###############################################################
#  Generated by:      Cadence Innovus 20.13-s083_1
#  OS:                Linux x86_64(Host ID caddyxtra)
#  Generated on:      Thu Jul  8 16:11:33 2021
#  Design:            user_proj_example
#  Command:           write_lef_abstract -specifyTopLayer 6 -PGPinLayers {5 6} -noCutObs -stripePin results/user_proj_example.lef
###############################################################

VERSION 5.8 ;

BUSBITCHARS "[]" ;
DIVIDERCHAR "/" ;

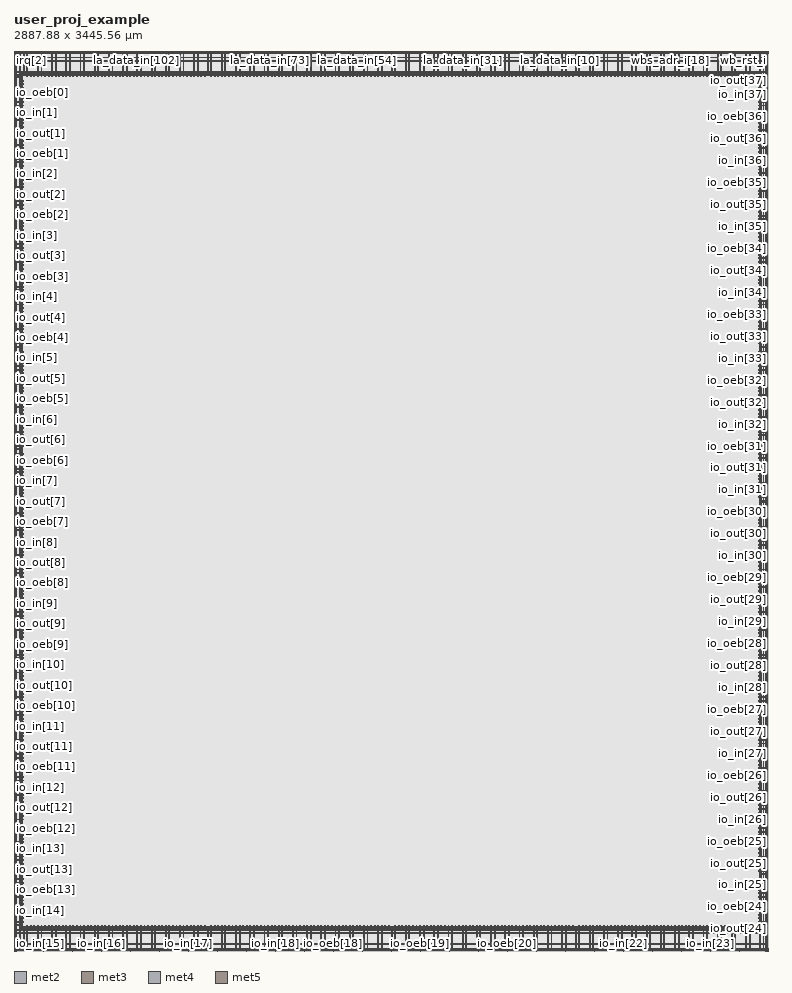
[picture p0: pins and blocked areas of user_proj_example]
MACRO user_proj_example
  CLASS BLOCK ;
  SIZE 2887.880000 BY 3445.560000 ;
  FOREIGN user_proj_example 0.000000 0.000000 ;
  ORIGIN 0 0 ;
  SYMMETRY X Y R90 ;
  PIN wb_clk_i
    DIRECTION INPUT ;
    USE SIGNAL ;
    ANTENNAPARTIALMETALAREA 0.238 LAYER met2  ;
    ANTENNAPARTIALMETALSIDEAREA 1.029 LAYER met2  ;
    ANTENNAPARTIALCUTAREA 0.04 LAYER via2  ;
    ANTENNAPARTIALMETALAREA 4.3968 LAYER met3  ;
    ANTENNAPARTIALMETALSIDEAREA 23.92 LAYER met3  ;
    ANTENNAMODEL OXIDE1 ;
    ANTENNAGATEAREA 1.152 LAYER met3  ;
    ANTENNAMAXAREACAR 6.23974 LAYER met3  ;
    ANTENNAMAXSIDEAREACAR 30.9826 LAYER met3  ;
    ANTENNAMAXCUTCAR 0.0793403 LAYER via3  ;
    PORT
      LAYER met2 ;
        RECT 2887.120000 3445.075000 2887.260000 3445.560000 ;
    END
  END wb_clk_i
  PIN wb_rst_i
    DIRECTION INPUT ;
    USE SIGNAL ;
    ANTENNAPARTIALMETALAREA 6.1835 LAYER met2  ;
    ANTENNAPARTIALMETALSIDEAREA 30.6915 LAYER met2  ;
    ANTENNAMODEL OXIDE1 ;
    ANTENNAGATEAREA 0.2475 LAYER met2  ;
    ANTENNAMAXAREACAR 26.3535 LAYER met2  ;
    ANTENNAMAXSIDEAREACAR 127.879 LAYER met2  ;
    ANTENNAMAXCUTCAR 0.207677 LAYER via2  ;
    PORT
      LAYER met2 ;
        RECT 2881.600000 3445.075000 2881.740000 3445.560000 ;
    END
  END wb_rst_i
  PIN wbs_stb_i
    DIRECTION INPUT ;
    USE SIGNAL ;
    ANTENNAPARTIALMETALAREA 2.4471 LAYER met2  ;
    ANTENNAPARTIALMETALSIDEAREA 12.1275 LAYER met2  ;
    ANTENNAMODEL OXIDE1 ;
    ANTENNAGATEAREA 0.2475 LAYER met2  ;
    ANTENNAMAXAREACAR 10.919 LAYER met2  ;
    ANTENNAMAXSIDEAREACAR 52.6263 LAYER met2  ;
    ANTENNAMAXCUTCAR 0.207677 LAYER via2  ;
    PORT
      LAYER met2 ;
        RECT 2863.660000 3445.075000 2863.800000 3445.560000 ;
    END
  END wbs_stb_i
  PIN wbs_cyc_i
    DIRECTION INPUT ;
    USE SIGNAL ;
    ANTENNAPARTIALMETALAREA 2.5759 LAYER met2  ;
    ANTENNAPARTIALMETALSIDEAREA 12.7715 LAYER met2  ;
    ANTENNAMODEL OXIDE1 ;
    ANTENNAGATEAREA 0.2475 LAYER met2  ;
    ANTENNAMAXAREACAR 13.2879 LAYER met2  ;
    ANTENNAMAXSIDEAREACAR 64.3515 LAYER met2  ;
    ANTENNAMAXCUTCAR 0.207677 LAYER via2  ;
    PORT
      LAYER met2 ;
        RECT 2869.640000 3445.075000 2869.780000 3445.560000 ;
    END
  END wbs_cyc_i
  PIN wbs_we_i
    DIRECTION INPUT ;
    USE SIGNAL ;
    ANTENNAPARTIALMETALAREA 2.5393 LAYER met2  ;
    ANTENNAPARTIALMETALSIDEAREA 12.3095 LAYER met2  ;
    ANTENNAMODEL OXIDE1 ;
    ANTENNAGATEAREA 0.126 LAYER met2  ;
    ANTENNAMAXAREACAR 22.6571 LAYER met2  ;
    ANTENNAMAXSIDEAREACAR 103.889 LAYER met2  ;
    ANTENNAPARTIALCUTAREA 0.04 LAYER via2  ;
    ANTENNAMAXCUTCAR 0.725397 LAYER via2  ;
    ANTENNAPARTIALMETALAREA 1.6368 LAYER met3  ;
    ANTENNAPARTIALMETALSIDEAREA 9.2 LAYER met3  ;
    ANTENNAGATEAREA 0.252 LAYER met3  ;
    ANTENNAMAXAREACAR 29.1524 LAYER met3  ;
    ANTENNAMAXSIDEAREACAR 140.397 LAYER met3  ;
    ANTENNAMAXCUTCAR 0.725397 LAYER via3  ;
    PORT
      LAYER met2 ;
        RECT 2858.140000 3445.075000 2858.280000 3445.560000 ;
    END
  END wbs_we_i
  PIN wbs_sel_i[3]
    DIRECTION INPUT ;
    USE SIGNAL ;
    PORT
      LAYER met2 ;
        RECT 2764.300000 3445.075000 2764.440000 3445.560000 ;
    END
  END wbs_sel_i[3]
  PIN wbs_sel_i[2]
    DIRECTION INPUT ;
    USE SIGNAL ;
    PORT
      LAYER met2 ;
        RECT 2787.760000 3445.075000 2787.900000 3445.560000 ;
    END
  END wbs_sel_i[2]
  PIN wbs_sel_i[1]
    DIRECTION INPUT ;
    USE SIGNAL ;
    PORT
      LAYER met2 ;
        RECT 2811.220000 3445.075000 2811.360000 3445.560000 ;
    END
  END wbs_sel_i[1]
  PIN wbs_sel_i[0]
    DIRECTION INPUT ;
    USE SIGNAL ;
    PORT
      LAYER met2 ;
        RECT 2834.680000 3445.075000 2834.820000 3445.560000 ;
    END
  END wbs_sel_i[0]
  PIN wbs_dat_i[31]
    DIRECTION INPUT ;
    USE SIGNAL ;
    ANTENNAPARTIALMETALAREA 2.3827 LAYER met2  ;
    ANTENNAPARTIALMETALSIDEAREA 11.8055 LAYER met2  ;
    ANTENNAMODEL OXIDE1 ;
    ANTENNAGATEAREA 0.126 LAYER met2  ;
    ANTENNAMAXAREACAR 31.0548 LAYER met2  ;
    ANTENNAMAXSIDEAREACAR 149.754 LAYER met2  ;
    ANTENNAMAXCUTCAR 0.407937 LAYER via2  ;
    PORT
      LAYER met2 ;
        RECT 2277.160000 3445.075000 2277.300000 3445.560000 ;
    END
  END wbs_dat_i[31]
  PIN wbs_dat_i[30]
    DIRECTION INPUT ;
    USE SIGNAL ;
    ANTENNAPARTIALMETALAREA 2.4919 LAYER met2  ;
    ANTENNAPARTIALMETALSIDEAREA 12.3515 LAYER met2  ;
    ANTENNAMODEL OXIDE1 ;
    ANTENNAGATEAREA 0.126 LAYER met2  ;
    ANTENNAMAXAREACAR 28.5845 LAYER met2  ;
    ANTENNAMAXSIDEAREACAR 133.508 LAYER met2  ;
    ANTENNAMAXCUTCAR 0.407937 LAYER via2  ;
    PORT
      LAYER met2 ;
        RECT 2294.640000 3445.075000 2294.780000 3445.560000 ;
    END
  END wbs_dat_i[30]
  PIN wbs_dat_i[29]
    DIRECTION INPUT ;
    USE SIGNAL ;
    ANTENNAPARTIALMETALAREA 3.4663 LAYER met2  ;
    ANTENNAPARTIALMETALSIDEAREA 17.2235 LAYER met2  ;
    ANTENNAMODEL OXIDE1 ;
    ANTENNAGATEAREA 0.126 LAYER met2  ;
    ANTENNAMAXAREACAR 53.9436 LAYER met2  ;
    ANTENNAMAXSIDEAREACAR 264.198 LAYER met2  ;
    ANTENNAMAXCUTCAR 0.407937 LAYER via2  ;
    PORT
      LAYER met2 ;
        RECT 2312.120000 3445.075000 2312.260000 3445.560000 ;
    END
  END wbs_dat_i[29]
  PIN wbs_dat_i[28]
    DIRECTION INPUT ;
    USE SIGNAL ;
    ANTENNAPARTIALMETALAREA 2.1111 LAYER met2  ;
    ANTENNAPARTIALMETALSIDEAREA 10.4475 LAYER met2  ;
    ANTENNAMODEL OXIDE1 ;
    ANTENNAGATEAREA 0.126 LAYER met2  ;
    ANTENNAMAXAREACAR 23.1687 LAYER met2  ;
    ANTENNAMAXSIDEAREACAR 102.921 LAYER met2  ;
    ANTENNAMAXCUTCAR 0.407937 LAYER via2  ;
    PORT
      LAYER met2 ;
        RECT 2329.600000 3445.075000 2329.740000 3445.560000 ;
    END
  END wbs_dat_i[28]
  PIN wbs_dat_i[27]
    DIRECTION INPUT ;
    USE SIGNAL ;
    ANTENNAPARTIALMETALAREA 2.2539 LAYER met2  ;
    ANTENNAPARTIALMETALSIDEAREA 11.1615 LAYER met2  ;
    ANTENNAMODEL OXIDE1 ;
    ANTENNAGATEAREA 0.126 LAYER met2  ;
    ANTENNAMAXAREACAR 19.9254 LAYER met2  ;
    ANTENNAMAXSIDEAREACAR 94.6429 LAYER met2  ;
    ANTENNAMAXCUTCAR 0.407937 LAYER via2  ;
    PORT
      LAYER met2 ;
        RECT 2347.540000 3445.075000 2347.680000 3445.560000 ;
    END
  END wbs_dat_i[27]
  PIN wbs_dat_i[26]
    DIRECTION INPUT ;
    USE SIGNAL ;
    ANTENNAPARTIALMETALAREA 2.2539 LAYER met2  ;
    ANTENNAPARTIALMETALSIDEAREA 11.1615 LAYER met2  ;
    ANTENNAMODEL OXIDE1 ;
    ANTENNAGATEAREA 0.126 LAYER met2  ;
    ANTENNAMAXAREACAR 19.9254 LAYER met2  ;
    ANTENNAMAXSIDEAREACAR 94.6429 LAYER met2  ;
    ANTENNAMAXCUTCAR 0.407937 LAYER via2  ;
    PORT
      LAYER met2 ;
        RECT 2365.020000 3445.075000 2365.160000 3445.560000 ;
    END
  END wbs_dat_i[26]
  PIN wbs_dat_i[25]
    DIRECTION INPUT ;
    USE SIGNAL ;
    ANTENNAPARTIALMETALAREA 2.1755 LAYER met2  ;
    ANTENNAPARTIALMETALSIDEAREA 10.7695 LAYER met2  ;
    ANTENNAMODEL OXIDE1 ;
    ANTENNAGATEAREA 0.126 LAYER met2  ;
    ANTENNAMAXAREACAR 23.6798 LAYER met2  ;
    ANTENNAMAXSIDEAREACAR 105.476 LAYER met2  ;
    ANTENNAMAXCUTCAR 0.407937 LAYER via2  ;
    PORT
      LAYER met2 ;
        RECT 2382.500000 3445.075000 2382.640000 3445.560000 ;
    END
  END wbs_dat_i[25]
  PIN wbs_dat_i[24]
    DIRECTION INPUT ;
    USE SIGNAL ;
    ANTENNAPARTIALMETALAREA 2.1111 LAYER met2  ;
    ANTENNAPARTIALMETALSIDEAREA 10.4475 LAYER met2  ;
    ANTENNAMODEL OXIDE1 ;
    ANTENNAGATEAREA 0.126 LAYER met2  ;
    ANTENNAMAXAREACAR 20.7282 LAYER met2  ;
    ANTENNAMAXSIDEAREACAR 91.254 LAYER met2  ;
    ANTENNAMAXCUTCAR 0.407937 LAYER via2  ;
    PORT
      LAYER met2 ;
        RECT 2400.440000 3445.075000 2400.580000 3445.560000 ;
    END
  END wbs_dat_i[24]
  PIN wbs_dat_i[23]
    DIRECTION INPUT ;
    USE SIGNAL ;
    ANTENNAPARTIALMETALAREA 2.1111 LAYER met2  ;
    ANTENNAPARTIALMETALSIDEAREA 10.4475 LAYER met2  ;
    ANTENNAMODEL OXIDE1 ;
    ANTENNAGATEAREA 0.126 LAYER met2  ;
    ANTENNAMAXAREACAR 21.6353 LAYER met2  ;
    ANTENNAMAXSIDEAREACAR 95.254 LAYER met2  ;
    ANTENNAMAXCUTCAR 0.407937 LAYER via2  ;
    PORT
      LAYER met2 ;
        RECT 2417.920000 3445.075000 2418.060000 3445.560000 ;
    END
  END wbs_dat_i[23]
  PIN wbs_dat_i[22]
    DIRECTION INPUT ;
    USE SIGNAL ;
    ANTENNAPARTIALMETALAREA 2.8139 LAYER met2  ;
    ANTENNAPARTIALMETALSIDEAREA 13.9615 LAYER met2  ;
    ANTENNAMODEL OXIDE1 ;
    ANTENNAGATEAREA 0.126 LAYER met2  ;
    ANTENNAMAXAREACAR 27.3179 LAYER met2  ;
    ANTENNAMAXSIDEAREACAR 127.175 LAYER met2  ;
    ANTENNAMAXCUTCAR 0.407937 LAYER via2  ;
    PORT
      LAYER met2 ;
        RECT 2435.400000 3445.075000 2435.540000 3445.560000 ;
    END
  END wbs_dat_i[22]
  PIN wbs_dat_i[21]
    DIRECTION INPUT ;
    USE SIGNAL ;
    ANTENNAPARTIALMETALAREA 2.4919 LAYER met2  ;
    ANTENNAPARTIALMETALSIDEAREA 12.3515 LAYER met2  ;
    ANTENNAMODEL OXIDE1 ;
    ANTENNAGATEAREA 0.126 LAYER met2  ;
    ANTENNAMAXAREACAR 24.2512 LAYER met2  ;
    ANTENNAMAXSIDEAREACAR 111.841 LAYER met2  ;
    ANTENNAMAXCUTCAR 0.407937 LAYER via2  ;
    PORT
      LAYER met2 ;
        RECT 2452.880000 3445.075000 2453.020000 3445.560000 ;
    END
  END wbs_dat_i[21]
  PIN wbs_dat_i[20]
    DIRECTION INPUT ;
    USE SIGNAL ;
    ANTENNAPARTIALMETALAREA 2.5395 LAYER met2  ;
    ANTENNAPARTIALMETALSIDEAREA 12.5895 LAYER met2  ;
    ANTENNAMODEL OXIDE1 ;
    ANTENNAGATEAREA 0.126 LAYER met2  ;
    ANTENNAMAXAREACAR 23.6103 LAYER met2  ;
    ANTENNAMAXSIDEAREACAR 112.532 LAYER met2  ;
    ANTENNAMAXCUTCAR 0.407937 LAYER via2  ;
    PORT
      LAYER met2 ;
        RECT 2470.820000 3445.075000 2470.960000 3445.560000 ;
    END
  END wbs_dat_i[20]
  PIN wbs_dat_i[19]
    DIRECTION INPUT ;
    USE SIGNAL ;
    ANTENNAPARTIALMETALAREA 2.4135 LAYER met2  ;
    ANTENNAPARTIALMETALSIDEAREA 11.9595 LAYER met2  ;
    ANTENNAMODEL OXIDE1 ;
    ANTENNAGATEAREA 0.126 LAYER met2  ;
    ANTENNAMAXAREACAR 23.1179 LAYER met2  ;
    ANTENNAMAXSIDEAREACAR 106.175 LAYER met2  ;
    ANTENNAMAXCUTCAR 0.407937 LAYER via2  ;
    PORT
      LAYER met2 ;
        RECT 2488.300000 3445.075000 2488.440000 3445.560000 ;
    END
  END wbs_dat_i[19]
  PIN wbs_dat_i[18]
    DIRECTION INPUT ;
    USE SIGNAL ;
    ANTENNAPARTIALMETALAREA 2.6515 LAYER met2  ;
    ANTENNAPARTIALMETALSIDEAREA 13.1495 LAYER met2  ;
    ANTENNAMODEL OXIDE1 ;
    ANTENNAGATEAREA 0.126 LAYER met2  ;
    ANTENNAMAXAREACAR 23.477 LAYER met2  ;
    ANTENNAMAXSIDEAREACAR 111.865 LAYER met2  ;
    ANTENNAMAXCUTCAR 0.407937 LAYER via2  ;
    PORT
      LAYER met2 ;
        RECT 2505.780000 3445.075000 2505.920000 3445.560000 ;
    END
  END wbs_dat_i[18]
  PIN wbs_dat_i[17]
    DIRECTION INPUT ;
    USE SIGNAL ;
    ANTENNAPARTIALMETALAREA 2.2539 LAYER met2  ;
    ANTENNAPARTIALMETALSIDEAREA 11.1615 LAYER met2  ;
    ANTENNAMODEL OXIDE1 ;
    ANTENNAGATEAREA 0.126 LAYER met2  ;
    ANTENNAMAXAREACAR 19.9254 LAYER met2  ;
    ANTENNAMAXSIDEAREACAR 94.6429 LAYER met2  ;
    ANTENNAMAXCUTCAR 0.407937 LAYER via2  ;
    PORT
      LAYER met2 ;
        RECT 2523.260000 3445.075000 2523.400000 3445.560000 ;
    END
  END wbs_dat_i[17]
  PIN wbs_dat_i[16]
    DIRECTION INPUT ;
    USE SIGNAL ;
    ANTENNAPARTIALMETALAREA 2.4919 LAYER met2  ;
    ANTENNAPARTIALMETALSIDEAREA 12.3515 LAYER met2  ;
    ANTENNAMODEL OXIDE1 ;
    ANTENNAGATEAREA 0.126 LAYER met2  ;
    ANTENNAMAXAREACAR 26.8067 LAYER met2  ;
    ANTENNAMAXSIDEAREACAR 124.619 LAYER met2  ;
    ANTENNAMAXCUTCAR 0.407937 LAYER via2  ;
    PORT
      LAYER met2 ;
        RECT 2541.200000 3445.075000 2541.340000 3445.560000 ;
    END
  END wbs_dat_i[16]
  PIN wbs_dat_i[15]
    DIRECTION INPUT ;
    USE SIGNAL ;
    ANTENNAPARTIALMETALAREA 2.1111 LAYER met2  ;
    ANTENNAPARTIALMETALSIDEAREA 10.4475 LAYER met2  ;
    ANTENNAMODEL OXIDE1 ;
    ANTENNAGATEAREA 0.126 LAYER met2  ;
    ANTENNAMAXAREACAR 21.6353 LAYER met2  ;
    ANTENNAMAXSIDEAREACAR 95.254 LAYER met2  ;
    ANTENNAMAXCUTCAR 0.407937 LAYER via2  ;
    PORT
      LAYER met2 ;
        RECT 2558.680000 3445.075000 2558.820000 3445.560000 ;
    END
  END wbs_dat_i[15]
  PIN wbs_dat_i[14]
    DIRECTION INPUT ;
    USE SIGNAL ;
    ANTENNAPARTIALMETALAREA 2.7495 LAYER met2  ;
    ANTENNAPARTIALMETALSIDEAREA 13.6395 LAYER met2  ;
    ANTENNAMODEL OXIDE1 ;
    ANTENNAGATEAREA 0.126 LAYER met2  ;
    ANTENNAMAXAREACAR 25.7845 LAYER met2  ;
    ANTENNAMAXSIDEAREACAR 119.508 LAYER met2  ;
    ANTENNAMAXCUTCAR 0.407937 LAYER via2  ;
    PORT
      LAYER met2 ;
        RECT 2576.160000 3445.075000 2576.300000 3445.560000 ;
    END
  END wbs_dat_i[14]
  PIN wbs_dat_i[13]
    DIRECTION INPUT ;
    USE SIGNAL ;
    ANTENNAPARTIALMETALAREA 2.1111 LAYER met2  ;
    ANTENNAPARTIALMETALSIDEAREA 10.4475 LAYER met2  ;
    ANTENNAMODEL OXIDE1 ;
    ANTENNAGATEAREA 0.126 LAYER met2  ;
    ANTENNAMAXAREACAR 25.2131 LAYER met2  ;
    ANTENNAMAXSIDEAREACAR 113.143 LAYER met2  ;
    ANTENNAMAXCUTCAR 0.407937 LAYER via2  ;
    PORT
      LAYER met2 ;
        RECT 2594.100000 3445.075000 2594.240000 3445.560000 ;
    END
  END wbs_dat_i[13]
  PIN wbs_dat_i[12]
    DIRECTION INPUT ;
    USE SIGNAL ;
    ANTENNAPARTIALMETALAREA 2.2399 LAYER met2  ;
    ANTENNAPARTIALMETALSIDEAREA 11.0915 LAYER met2  ;
    ANTENNAMODEL OXIDE1 ;
    ANTENNAGATEAREA 0.126 LAYER met2  ;
    ANTENNAMAXAREACAR 29.8131 LAYER met2  ;
    ANTENNAMAXSIDEAREACAR 136.143 LAYER met2  ;
    ANTENNAMAXCUTCAR 0.407937 LAYER via2  ;
    PORT
      LAYER met2 ;
        RECT 2611.580000 3445.075000 2611.720000 3445.560000 ;
    END
  END wbs_dat_i[12]
  PIN wbs_dat_i[11]
    DIRECTION INPUT ;
    USE SIGNAL ;
    ANTENNAPARTIALMETALAREA 2.1111 LAYER met2  ;
    ANTENNAPARTIALMETALSIDEAREA 10.4475 LAYER met2  ;
    ANTENNAMODEL OXIDE1 ;
    ANTENNAGATEAREA 0.126 LAYER met2  ;
    ANTENNAMAXAREACAR 21.1242 LAYER met2  ;
    ANTENNAMAXSIDEAREACAR 92.6984 LAYER met2  ;
    ANTENNAMAXCUTCAR 0.407937 LAYER via2  ;
    PORT
      LAYER met2 ;
        RECT 2629.060000 3445.075000 2629.200000 3445.560000 ;
    END
  END wbs_dat_i[11]
  PIN wbs_dat_i[10]
    DIRECTION INPUT ;
    USE SIGNAL ;
    ANTENNAPARTIALMETALAREA 2.4919 LAYER met2  ;
    ANTENNAPARTIALMETALSIDEAREA 12.3515 LAYER met2  ;
    ANTENNAMODEL OXIDE1 ;
    ANTENNAGATEAREA 0.126 LAYER met2  ;
    ANTENNAMAXAREACAR 30.7992 LAYER met2  ;
    ANTENNAMAXSIDEAREACAR 148.476 LAYER met2  ;
    ANTENNAMAXCUTCAR 0.407937 LAYER via2  ;
    PORT
      LAYER met2 ;
        RECT 2646.540000 3445.075000 2646.680000 3445.560000 ;
    END
  END wbs_dat_i[10]
  PIN wbs_dat_i[9]
    DIRECTION INPUT ;
    USE SIGNAL ;
    ANTENNAPARTIALMETALAREA 2.1111 LAYER met2  ;
    ANTENNAPARTIALMETALSIDEAREA 10.4475 LAYER met2  ;
    ANTENNAMODEL OXIDE1 ;
    ANTENNAGATEAREA 0.126 LAYER met2  ;
    ANTENNAMAXAREACAR 23.6798 LAYER met2  ;
    ANTENNAMAXSIDEAREACAR 105.476 LAYER met2  ;
    ANTENNAMAXCUTCAR 0.407937 LAYER via2  ;
    PORT
      LAYER met2 ;
        RECT 2664.480000 3445.075000 2664.620000 3445.560000 ;
    END
  END wbs_dat_i[9]
  PIN wbs_dat_i[8]
    DIRECTION INPUT ;
    USE SIGNAL ;
    ANTENNAPARTIALMETALAREA 2.1111 LAYER met2  ;
    ANTENNAPARTIALMETALSIDEAREA 10.4475 LAYER met2  ;
    ANTENNAMODEL OXIDE1 ;
    ANTENNAGATEAREA 0.126 LAYER met2  ;
    ANTENNAMAXAREACAR 22.6575 LAYER met2  ;
    ANTENNAMAXSIDEAREACAR 100.365 LAYER met2  ;
    ANTENNAMAXCUTCAR 0.407937 LAYER via2  ;
    PORT
      LAYER met2 ;
        RECT 2681.960000 3445.075000 2682.100000 3445.560000 ;
    END
  END wbs_dat_i[8]
  PIN wbs_dat_i[7]
    DIRECTION INPUT ;
    USE SIGNAL ;
    ANTENNAPARTIALMETALAREA 2.1111 LAYER met2  ;
    ANTENNAPARTIALMETALSIDEAREA 10.4475 LAYER met2  ;
    ANTENNAMODEL OXIDE1 ;
    ANTENNAGATEAREA 0.126 LAYER met2  ;
    ANTENNAMAXAREACAR 28.5242 LAYER met2  ;
    ANTENNAMAXSIDEAREACAR 129.698 LAYER met2  ;
    ANTENNAMAXCUTCAR 0.407937 LAYER via2  ;
    PORT
      LAYER met2 ;
        RECT 2699.440000 3445.075000 2699.580000 3445.560000 ;
    END
  END wbs_dat_i[7]
  PIN wbs_dat_i[6]
    DIRECTION INPUT ;
    USE SIGNAL ;
    ANTENNAPARTIALMETALAREA 2.6207 LAYER met2  ;
    ANTENNAPARTIALMETALSIDEAREA 12.9955 LAYER met2  ;
    ANTENNAMODEL OXIDE1 ;
    ANTENNAGATEAREA 0.126 LAYER met2  ;
    ANTENNAMAXAREACAR 26.8067 LAYER met2  ;
    ANTENNAMAXSIDEAREACAR 124.619 LAYER met2  ;
    ANTENNAMAXCUTCAR 0.407937 LAYER via2  ;
    PORT
      LAYER met2 ;
        RECT 2717.380000 3445.075000 2717.520000 3445.560000 ;
    END
  END wbs_dat_i[6]
  PIN wbs_dat_i[5]
    DIRECTION INPUT ;
    USE SIGNAL ;
    ANTENNAPARTIALMETALAREA 2.1111 LAYER met2  ;
    ANTENNAPARTIALMETALSIDEAREA 10.4475 LAYER met2  ;
    ANTENNAMODEL OXIDE1 ;
    ANTENNAGATEAREA 0.126 LAYER met2  ;
    ANTENNAMAXAREACAR 22.1464 LAYER met2  ;
    ANTENNAMAXSIDEAREACAR 97.8095 LAYER met2  ;
    ANTENNAMAXCUTCAR 0.407937 LAYER via2  ;
    PORT
      LAYER met2 ;
        RECT 2734.860000 3445.075000 2735.000000 3445.560000 ;
    END
  END wbs_dat_i[5]
  PIN wbs_dat_i[4]
    DIRECTION INPUT ;
    USE SIGNAL ;
    ANTENNAPARTIALMETALAREA 2.1111 LAYER met2  ;
    ANTENNAPARTIALMETALSIDEAREA 10.4475 LAYER met2  ;
    ANTENNAMODEL OXIDE1 ;
    ANTENNAGATEAREA 0.126 LAYER met2  ;
    ANTENNAMAXAREACAR 21.6353 LAYER met2  ;
    ANTENNAMAXSIDEAREACAR 95.254 LAYER met2  ;
    ANTENNAMAXCUTCAR 0.407937 LAYER via2  ;
    PORT
      LAYER met2 ;
        RECT 2752.340000 3445.075000 2752.480000 3445.560000 ;
    END
  END wbs_dat_i[4]
  PIN wbs_dat_i[3]
    DIRECTION INPUT ;
    USE SIGNAL ;
    ANTENNAPARTIALMETALAREA 6.1079 LAYER met2  ;
    ANTENNAPARTIALMETALSIDEAREA 30.3135 LAYER met2  ;
    ANTENNAMODEL OXIDE1 ;
    ANTENNAGATEAREA 0.252 LAYER met2  ;
    ANTENNAMAXAREACAR 55.1405 LAYER met2  ;
    ANTENNAMAXSIDEAREACAR 265.339 LAYER met2  ;
    ANTENNAMAXCUTCAR 0.586508 LAYER via2  ;
    PORT
      LAYER met2 ;
        RECT 2775.800000 3445.075000 2775.940000 3445.560000 ;
    END
  END wbs_dat_i[3]
  PIN wbs_dat_i[2]
    DIRECTION INPUT ;
    USE SIGNAL ;
    ANTENNAPARTIALMETALAREA 5.5583 LAYER met2  ;
    ANTENNAPARTIALMETALSIDEAREA 27.4575 LAYER met2  ;
    ANTENNAMODEL OXIDE1 ;
    ANTENNAGATEAREA 0.252 LAYER met2  ;
    ANTENNAMAXAREACAR 34.3373 LAYER met2  ;
    ANTENNAMAXSIDEAREACAR 158.296 LAYER met2  ;
    ANTENNAMAXCUTCAR 0.407937 LAYER via2  ;
    PORT
      LAYER met2 ;
        RECT 2799.260000 3445.075000 2799.400000 3445.560000 ;
    END
  END wbs_dat_i[2]
  PIN wbs_dat_i[1]
    DIRECTION INPUT ;
    USE SIGNAL ;
    ANTENNAPARTIALMETALAREA 5.6583 LAYER met2  ;
    ANTENNAPARTIALMETALSIDEAREA 27.9475 LAYER met2  ;
    ANTENNAMODEL OXIDE1 ;
    ANTENNAGATEAREA 0.747 LAYER met2  ;
    ANTENNAMAXAREACAR 63.3128 LAYER met2  ;
    ANTENNAMAXSIDEAREACAR 310.584 LAYER met2  ;
    ANTENNAMAXCUTCAR 0.586508 LAYER via2  ;
    PORT
      LAYER met2 ;
        RECT 2822.720000 3445.075000 2822.860000 3445.560000 ;
    END
  END wbs_dat_i[1]
  PIN wbs_dat_i[0]
    DIRECTION INPUT ;
    USE SIGNAL ;
    ANTENNAPARTIALMETALAREA 6.6027 LAYER met2  ;
    ANTENNAPARTIALMETALSIDEAREA 32.6795 LAYER met2  ;
    ANTENNAMODEL OXIDE1 ;
    ANTENNAGATEAREA 1.368 LAYER met2  ;
    ANTENNAMAXAREACAR 19.5075 LAYER met2  ;
    ANTENNAMAXSIDEAREACAR 92.6703 LAYER met2  ;
    ANTENNAMAXCUTCAR 0.407937 LAYER via2  ;
    PORT
      LAYER met2 ;
        RECT 2846.180000 3445.075000 2846.320000 3445.560000 ;
    END
  END wbs_dat_i[0]
  PIN wbs_adr_i[31]
    DIRECTION INPUT ;
    USE SIGNAL ;
    ANTENNAPARTIALMETALAREA 2.3755 LAYER met2  ;
    ANTENNAPARTIALMETALSIDEAREA 11.6515 LAYER met2  ;
    ANTENNAMODEL OXIDE1 ;
    ANTENNAGATEAREA 0.126 LAYER met2  ;
    ANTENNAMAXAREACAR 21.6187 LAYER met2  ;
    ANTENNAMAXSIDEAREACAR 99.0714 LAYER met2  ;
    ANTENNAMAXCUTCAR 0.407937 LAYER via2  ;
    PORT
      LAYER met2 ;
        RECT 2282.680000 3445.075000 2282.820000 3445.560000 ;
    END
  END wbs_adr_i[31]
  PIN wbs_adr_i[30]
    DIRECTION INPUT ;
    USE SIGNAL ;
    ANTENNAPARTIALMETALAREA 2.2539 LAYER met2  ;
    ANTENNAPARTIALMETALSIDEAREA 11.1615 LAYER met2  ;
    ANTENNAMODEL OXIDE1 ;
    ANTENNAGATEAREA 0.126 LAYER met2  ;
    ANTENNAMAXAREACAR 40.2833 LAYER met2  ;
    ANTENNAMAXSIDEAREACAR 193.365 LAYER met2  ;
    ANTENNAMAXCUTCAR 0.407937 LAYER via2  ;
    PORT
      LAYER met2 ;
        RECT 2300.620000 3445.075000 2300.760000 3445.560000 ;
    END
  END wbs_adr_i[30]
  PIN wbs_adr_i[29]
    DIRECTION INPUT ;
    USE SIGNAL ;
    ANTENNAPARTIALMETALAREA 2.4471 LAYER met2  ;
    ANTENNAPARTIALMETALSIDEAREA 12.1275 LAYER met2  ;
    ANTENNAMODEL OXIDE1 ;
    ANTENNAGATEAREA 0.2475 LAYER met2  ;
    ANTENNAMAXAREACAR 10.9034 LAYER met2  ;
    ANTENNAMAXSIDEAREACAR 52.0727 LAYER met2  ;
    ANTENNAMAXCUTCAR 0.207677 LAYER via2  ;
    PORT
      LAYER met2 ;
        RECT 2318.100000 3445.075000 2318.240000 3445.560000 ;
    END
  END wbs_adr_i[29]
  PIN wbs_adr_i[28]
    DIRECTION INPUT ;
    USE SIGNAL ;
    ANTENNAPARTIALMETALAREA 2.3491 LAYER met2  ;
    ANTENNAPARTIALMETALSIDEAREA 11.6375 LAYER met2  ;
    ANTENNAMODEL OXIDE1 ;
    ANTENNAGATEAREA 0.2475 LAYER met2  ;
    ANTENNAMAXAREACAR 20.0469 LAYER met2  ;
    ANTENNAMAXSIDEAREACAR 98.202 LAYER met2  ;
    ANTENNAMAXCUTCAR 0.207677 LAYER via2  ;
    PORT
      LAYER met2 ;
        RECT 2335.580000 3445.075000 2335.720000 3445.560000 ;
    END
  END wbs_adr_i[28]
  PIN wbs_adr_i[27]
    DIRECTION INPUT ;
    USE SIGNAL ;
    ANTENNAPARTIALMETALAREA 2.2327 LAYER met2  ;
    ANTENNAPARTIALMETALSIDEAREA 10.9375 LAYER met2  ;
    ANTENNAMODEL OXIDE1 ;
    ANTENNAGATEAREA 0.126 LAYER met2  ;
    ANTENNAMAXAREACAR 23.3643 LAYER met2  ;
    ANTENNAMAXSIDEAREACAR 99.0556 LAYER met2  ;
    ANTENNAMAXCUTCAR 0.407937 LAYER via2  ;
    PORT
      LAYER met2 ;
        RECT 2353.520000 3445.075000 2353.660000 3445.560000 ;
    END
  END wbs_adr_i[27]
  PIN wbs_adr_i[26]
    DIRECTION INPUT ;
    USE SIGNAL ;
    ANTENNAPARTIALMETALAREA 2.3491 LAYER met2  ;
    ANTENNAPARTIALMETALSIDEAREA 11.6375 LAYER met2  ;
    ANTENNAMODEL OXIDE1 ;
    ANTENNAGATEAREA 0.126 LAYER met2  ;
    ANTENNAMAXAREACAR 42.5274 LAYER met2  ;
    ANTENNAMAXSIDEAREACAR 200.865 LAYER met2  ;
    ANTENNAMAXCUTCAR 0.407937 LAYER via2  ;
    PORT
      LAYER met2 ;
        RECT 2371.000000 3445.075000 2371.140000 3445.560000 ;
    END
  END wbs_adr_i[26]
  PIN wbs_adr_i[25]
    DIRECTION INPUT ;
    USE SIGNAL ;
    ANTENNAPARTIALMETALAREA 2.1111 LAYER met2  ;
    ANTENNAPARTIALMETALSIDEAREA 10.4475 LAYER met2  ;
    ANTENNAMODEL OXIDE1 ;
    ANTENNAGATEAREA 0.126 LAYER met2  ;
    ANTENNAMAXAREACAR 22.948 LAYER met2  ;
    ANTENNAMAXSIDEAREACAR 97.3095 LAYER met2  ;
    ANTENNAMAXCUTCAR 0.407937 LAYER via2  ;
    PORT
      LAYER met2 ;
        RECT 2388.480000 3445.075000 2388.620000 3445.560000 ;
    END
  END wbs_adr_i[25]
  PIN wbs_adr_i[24]
    DIRECTION INPUT ;
    USE SIGNAL ;
    ANTENNAPARTIALMETALAREA 2.3755 LAYER met2  ;
    ANTENNAPARTIALMETALSIDEAREA 11.6515 LAYER met2  ;
    ANTENNAMODEL OXIDE1 ;
    ANTENNAGATEAREA 0.126 LAYER met2  ;
    ANTENNAMAXAREACAR 28.9425 LAYER met2  ;
    ANTENNAMAXSIDEAREACAR 138.167 LAYER met2  ;
    ANTENNAMAXCUTCAR 0.407937 LAYER via2  ;
    PORT
      LAYER met2 ;
        RECT 2405.960000 3445.075000 2406.100000 3445.560000 ;
    END
  END wbs_adr_i[24]
  PIN wbs_adr_i[23]
    DIRECTION INPUT ;
    USE SIGNAL ;
    ANTENNAPARTIALMETALAREA 2.2327 LAYER met2  ;
    ANTENNAPARTIALMETALSIDEAREA 10.9375 LAYER met2  ;
    ANTENNAMODEL OXIDE1 ;
    ANTENNAGATEAREA 0.126 LAYER met2  ;
    ANTENNAMAXAREACAR 33.1131 LAYER met2  ;
    ANTENNAMAXSIDEAREACAR 147.198 LAYER met2  ;
    ANTENNAMAXCUTCAR 0.407937 LAYER via2  ;
    PORT
      LAYER met2 ;
        RECT 2423.900000 3445.075000 2424.040000 3445.560000 ;
    END
  END wbs_adr_i[23]
  PIN wbs_adr_i[22]
    DIRECTION INPUT ;
    USE SIGNAL ;
    ANTENNAPARTIALMETALAREA 2.2327 LAYER met2  ;
    ANTENNAPARTIALMETALSIDEAREA 10.9375 LAYER met2  ;
    ANTENNAMODEL OXIDE1 ;
    ANTENNAGATEAREA 0.126 LAYER met2  ;
    ANTENNAMAXAREACAR 44.7183 LAYER met2  ;
    ANTENNAMAXSIDEAREACAR 201.381 LAYER met2  ;
    ANTENNAMAXCUTCAR 0.407937 LAYER via2  ;
    PORT
      LAYER met2 ;
        RECT 2441.380000 3445.075000 2441.520000 3445.560000 ;
    END
  END wbs_adr_i[22]
  PIN wbs_adr_i[21]
    DIRECTION INPUT ;
    USE SIGNAL ;
    ANTENNAPARTIALMETALAREA 2.3755 LAYER met2  ;
    ANTENNAPARTIALMETALSIDEAREA 11.6515 LAYER met2  ;
    ANTENNAMODEL OXIDE1 ;
    ANTENNAGATEAREA 0.126 LAYER met2  ;
    ANTENNAMAXAREACAR 20.8798 LAYER met2  ;
    ANTENNAMAXSIDEAREACAR 98.3889 LAYER met2  ;
    ANTENNAMAXCUTCAR 0.407937 LAYER via2  ;
    PORT
      LAYER met2 ;
        RECT 2458.860000 3445.075000 2459.000000 3445.560000 ;
    END
  END wbs_adr_i[21]
  PIN wbs_adr_i[20]
    DIRECTION INPUT ;
    USE SIGNAL ;
    ANTENNAPARTIALMETALAREA 2.5115 LAYER met2  ;
    ANTENNAPARTIALMETALSIDEAREA 12.4495 LAYER met2  ;
    ANTENNAMODEL OXIDE1 ;
    ANTENNAGATEAREA 0.126 LAYER met2  ;
    ANTENNAMAXAREACAR 26.3214 LAYER met2  ;
    ANTENNAMAXSIDEAREACAR 114.778 LAYER met2  ;
    ANTENNAMAXCUTCAR 0.407937 LAYER via2  ;
    PORT
      LAYER met2 ;
        RECT 2476.340000 3445.075000 2476.480000 3445.560000 ;
    END
  END wbs_adr_i[20]
  PIN wbs_adr_i[19]
    DIRECTION INPUT ;
    USE SIGNAL ;
    ANTENNAPARTIALMETALAREA 2.1851 LAYER met2  ;
    ANTENNAPARTIALMETALSIDEAREA 10.6995 LAYER met2  ;
    ANTENNAMODEL OXIDE1 ;
    ANTENNAGATEAREA 0.126 LAYER met2  ;
    ANTENNAMAXAREACAR 33.7575 LAYER met2  ;
    ANTENNAMAXSIDEAREACAR 150.421 LAYER met2  ;
    ANTENNAMAXCUTCAR 0.407937 LAYER via2  ;
    PORT
      LAYER met2 ;
        RECT 2494.280000 3445.075000 2494.420000 3445.560000 ;
    END
  END wbs_adr_i[19]
  PIN wbs_adr_i[18]
    DIRECTION INPUT ;
    USE SIGNAL ;
    ANTENNAPARTIALMETALAREA 2.6875 LAYER met2  ;
    ANTENNAPARTIALMETALSIDEAREA 13.0935 LAYER met2  ;
    ANTENNAMODEL OXIDE1 ;
    ANTENNAGATEAREA 0.126 LAYER met2  ;
    ANTENNAMAXAREACAR 36.0187 LAYER met2  ;
    ANTENNAMAXSIDEAREACAR 172.611 LAYER met2  ;
    ANTENNAMAXCUTCAR 0.407937 LAYER via2  ;
    PORT
      LAYER met2 ;
        RECT 2511.760000 3445.075000 2511.900000 3445.560000 ;
    END
  END wbs_adr_i[18]
  PIN wbs_adr_i[17]
    DIRECTION INPUT ;
    USE SIGNAL ;
    ANTENNAPARTIALMETALAREA 2.4231 LAYER met2  ;
    ANTENNAPARTIALMETALSIDEAREA 11.8895 LAYER met2  ;
    ANTENNAMODEL OXIDE1 ;
    ANTENNAGATEAREA 0.126 LAYER met2  ;
    ANTENNAMAXAREACAR 31.3591 LAYER met2  ;
    ANTENNAMAXSIDEAREACAR 144.087 LAYER met2  ;
    ANTENNAMAXCUTCAR 0.407937 LAYER via2  ;
    PORT
      LAYER met2 ;
        RECT 2529.240000 3445.075000 2529.380000 3445.560000 ;
    END
  END wbs_adr_i[17]
  PIN wbs_adr_i[16]
    DIRECTION INPUT ;
    USE SIGNAL ;
    ANTENNAPARTIALMETALAREA 2.5253 LAYER met2  ;
    ANTENNAPARTIALMETALSIDEAREA 12.4005 LAYER met2  ;
    ANTENNAMODEL OXIDE1 ;
    ANTENNAGATEAREA 0.126 LAYER met2  ;
    ANTENNAMAXAREACAR 22.0687 LAYER met2  ;
    ANTENNAMAXSIDEAREACAR 104.333 LAYER met2  ;
    ANTENNAMAXCUTCAR 0.407937 LAYER via2  ;
    PORT
      LAYER met2 ;
        RECT 2547.180000 3445.075000 2547.320000 3445.560000 ;
    END
  END wbs_adr_i[16]
  PIN wbs_adr_i[15]
    DIRECTION INPUT ;
    USE SIGNAL ;
    ANTENNAPARTIALMETALAREA 2.1111 LAYER met2  ;
    ANTENNAPARTIALMETALSIDEAREA 10.4475 LAYER met2  ;
    ANTENNAMODEL OXIDE1 ;
    ANTENNAGATEAREA 0.126 LAYER met2  ;
    ANTENNAMAXAREACAR 81.3214 LAYER met2  ;
    ANTENNAMAXSIDEAREACAR 389.778 LAYER met2  ;
    ANTENNAMAXCUTCAR 0.407937 LAYER via2  ;
    PORT
      LAYER met2 ;
        RECT 2564.660000 3445.075000 2564.800000 3445.560000 ;
    END
  END wbs_adr_i[15]
  PIN wbs_adr_i[14]
    DIRECTION INPUT ;
    USE SIGNAL ;
    ANTENNAPARTIALMETALAREA 2.2327 LAYER met2  ;
    ANTENNAPARTIALMETALSIDEAREA 10.9375 LAYER met2  ;
    ANTENNAMODEL OXIDE1 ;
    ANTENNAGATEAREA 0.126 LAYER met2  ;
    ANTENNAMAXAREACAR 22.4948 LAYER met2  ;
    ANTENNAMAXSIDEAREACAR 94.6429 LAYER met2  ;
    ANTENNAMAXCUTCAR 0.407937 LAYER via2  ;
    PORT
      LAYER met2 ;
        RECT 2582.140000 3445.075000 2582.280000 3445.560000 ;
    END
  END wbs_adr_i[14]
  PIN wbs_adr_i[13]
    DIRECTION INPUT ;
    USE SIGNAL ;
    ANTENNAPARTIALMETALAREA 3.0517 LAYER met2  ;
    ANTENNAPARTIALMETALSIDEAREA 15.0325 LAYER met2  ;
    ANTENNAMODEL OXIDE1 ;
    ANTENNAGATEAREA 0.126 LAYER met2  ;
    ANTENNAMAXAREACAR 62.4651 LAYER met2  ;
    ANTENNAMAXSIDEAREACAR 298.571 LAYER met2  ;
    ANTENNAMAXCUTCAR 0.407937 LAYER via2  ;
    PORT
      LAYER met2 ;
        RECT 2599.620000 3445.075000 2599.760000 3445.560000 ;
    END
  END wbs_adr_i[13]
  PIN wbs_adr_i[12]
    DIRECTION INPUT ;
    USE SIGNAL ;
    ANTENNAPARTIALMETALAREA 2.3827 LAYER met2  ;
    ANTENNAPARTIALMETALSIDEAREA 11.8055 LAYER met2  ;
    ANTENNAMODEL OXIDE1 ;
    ANTENNAGATEAREA 0.126 LAYER met2  ;
    ANTENNAMAXAREACAR 21.8556 LAYER met2  ;
    ANTENNAMAXSIDEAREACAR 101.349 LAYER met2  ;
    ANTENNAMAXCUTCAR 0.407937 LAYER via2  ;
    PORT
      LAYER met2 ;
        RECT 2617.560000 3445.075000 2617.700000 3445.560000 ;
    END
  END wbs_adr_i[12]
  PIN wbs_adr_i[11]
    DIRECTION INPUT ;
    USE SIGNAL ;
    ANTENNAPARTIALMETALAREA 2.3013 LAYER met2  ;
    ANTENNAPARTIALMETALSIDEAREA 11.2805 LAYER met2  ;
    ANTENNAMODEL OXIDE1 ;
    ANTENNAGATEAREA 0.126 LAYER met2  ;
    ANTENNAMAXAREACAR 30.5909 LAYER met2  ;
    ANTENNAMAXSIDEAREACAR 134.587 LAYER met2  ;
    ANTENNAMAXCUTCAR 0.407937 LAYER via2  ;
    PORT
      LAYER met2 ;
        RECT 2635.040000 3445.075000 2635.180000 3445.560000 ;
    END
  END wbs_adr_i[11]
  PIN wbs_adr_i[10]
    DIRECTION INPUT ;
    USE SIGNAL ;
    ANTENNAPARTIALMETALAREA 2.2327 LAYER met2  ;
    ANTENNAPARTIALMETALSIDEAREA 10.9375 LAYER met2  ;
    ANTENNAMODEL OXIDE1 ;
    ANTENNAGATEAREA 0.126 LAYER met2  ;
    ANTENNAMAXAREACAR 21.5052 LAYER met2  ;
    ANTENNAMAXSIDEAREACAR 94.881 LAYER met2  ;
    ANTENNAMAXCUTCAR 0.407937 LAYER via2  ;
    PORT
      LAYER met2 ;
        RECT 2652.520000 3445.075000 2652.660000 3445.560000 ;
    END
  END wbs_adr_i[10]
  PIN wbs_adr_i[9]
    DIRECTION INPUT ;
    USE SIGNAL ;
    ANTENNAPARTIALMETALAREA 2.2803 LAYER met2  ;
    ANTENNAPARTIALMETALSIDEAREA 11.1755 LAYER met2  ;
    ANTENNAMODEL OXIDE1 ;
    ANTENNAGATEAREA 0.126 LAYER met2  ;
    ANTENNAMAXAREACAR 33.6758 LAYER met2  ;
    ANTENNAMAXSIDEAREACAR 161.833 LAYER met2  ;
    ANTENNAMAXCUTCAR 0.407937 LAYER via2  ;
    PORT
      LAYER met2 ;
        RECT 2670.000000 3445.075000 2670.140000 3445.560000 ;
    END
  END wbs_adr_i[9]
  PIN wbs_adr_i[8]
    DIRECTION INPUT ;
    USE SIGNAL ;
    ANTENNAPARTIALMETALAREA 2.3755 LAYER met2  ;
    ANTENNAPARTIALMETALSIDEAREA 11.6515 LAYER met2  ;
    ANTENNAMODEL OXIDE1 ;
    ANTENNAGATEAREA 0.126 LAYER met2  ;
    ANTENNAMAXAREACAR 20.8798 LAYER met2  ;
    ANTENNAMAXSIDEAREACAR 98.3889 LAYER met2  ;
    ANTENNAMAXCUTCAR 0.407937 LAYER via2  ;
    PORT
      LAYER met2 ;
        RECT 2687.940000 3445.075000 2688.080000 3445.560000 ;
    END
  END wbs_adr_i[8]
  PIN wbs_adr_i[7]
    DIRECTION INPUT ;
    USE SIGNAL ;
    ANTENNAPARTIALMETALAREA 2.1587 LAYER met2  ;
    ANTENNAPARTIALMETALSIDEAREA 10.6855 LAYER met2  ;
    ANTENNAMODEL OXIDE1 ;
    ANTENNAGATEAREA 0.2475 LAYER met2  ;
    ANTENNAMAXAREACAR 22.6627 LAYER met2  ;
    ANTENNAMAXSIDEAREACAR 106.065 LAYER met2  ;
    ANTENNAMAXCUTCAR 0.207677 LAYER via2  ;
    PORT
      LAYER met2 ;
        RECT 2705.420000 3445.075000 2705.560000 3445.560000 ;
    END
  END wbs_adr_i[7]
  PIN wbs_adr_i[6]
    DIRECTION INPUT ;
    USE SIGNAL ;
    ANTENNAPARTIALMETALAREA 2.1111 LAYER met2  ;
    ANTENNAPARTIALMETALSIDEAREA 10.4475 LAYER met2  ;
    ANTENNAMODEL OXIDE1 ;
    ANTENNAGATEAREA 0.2475 LAYER met2  ;
    ANTENNAMAXAREACAR 11.8065 LAYER met2  ;
    ANTENNAMAXSIDEAREACAR 51.1677 LAYER met2  ;
    ANTENNAMAXCUTCAR 0.207677 LAYER via2  ;
    PORT
      LAYER met2 ;
        RECT 2722.900000 3445.075000 2723.040000 3445.560000 ;
    END
  END wbs_adr_i[6]
  PIN wbs_adr_i[5]
    DIRECTION INPUT ;
    USE SIGNAL ;
    ANTENNAPARTIALMETALAREA 2.1851 LAYER met2  ;
    ANTENNAPARTIALMETALSIDEAREA 10.6995 LAYER met2  ;
    ANTENNAMODEL OXIDE1 ;
    ANTENNAGATEAREA 0.2475 LAYER met2  ;
    ANTENNAMAXAREACAR 10.798 LAYER met2  ;
    ANTENNAMAXSIDEAREACAR 47.1232 LAYER met2  ;
    ANTENNAMAXCUTCAR 0.207677 LAYER via2  ;
    PORT
      LAYER met2 ;
        RECT 2740.840000 3445.075000 2740.980000 3445.560000 ;
    END
  END wbs_adr_i[5]
  PIN wbs_adr_i[4]
    DIRECTION INPUT ;
    USE SIGNAL ;
    ANTENNAPARTIALMETALAREA 3.0419 LAYER met2  ;
    ANTENNAPARTIALMETALSIDEAREA 14.9835 LAYER met2  ;
    ANTENNAMODEL OXIDE1 ;
    ANTENNAGATEAREA 0.3735 LAYER met2  ;
    ANTENNAMAXAREACAR 37.4463 LAYER met2  ;
    ANTENNAMAXSIDEAREACAR 167.093 LAYER met2  ;
    ANTENNAMAXCUTCAR 0.586508 LAYER via2  ;
    PORT
      LAYER met2 ;
        RECT 2758.320000 3445.075000 2758.460000 3445.560000 ;
    END
  END wbs_adr_i[4]
  PIN wbs_adr_i[3]
    DIRECTION INPUT ;
    USE SIGNAL ;
    ANTENNAPARTIALMETALAREA 3.3871 LAYER met2  ;
    ANTENNAPARTIALMETALSIDEAREA 16.7195 LAYER met2  ;
    ANTENNAMODEL OXIDE1 ;
    ANTENNAGATEAREA 0.8685 LAYER met2  ;
    ANTENNAMAXAREACAR 9.69365 LAYER met2  ;
    ANTENNAMAXSIDEAREACAR 40.7599 LAYER met2  ;
    ANTENNAMAXCUTCAR 0.289606 LAYER via2  ;
    PORT
      LAYER met2 ;
        RECT 2781.780000 3445.075000 2781.920000 3445.560000 ;
    END
  END wbs_adr_i[3]
  PIN wbs_adr_i[2]
    DIRECTION INPUT ;
    USE SIGNAL ;
    ANTENNAPARTIALMETALAREA 5.3163 LAYER met2  ;
    ANTENNAPARTIALMETALSIDEAREA 25.9035 LAYER met2  ;
    ANTENNAMODEL OXIDE1 ;
    ANTENNAGATEAREA 1.5225 LAYER met2  ;
    ANTENNAMAXAREACAR 36.5799 LAYER met2  ;
    ANTENNAMAXSIDEAREACAR 173.053 LAYER met2  ;
    ANTENNAMAXCUTCAR 0.765079 LAYER via2  ;
    PORT
      LAYER met2 ;
        RECT 2805.240000 3445.075000 2805.380000 3445.560000 ;
    END
  END wbs_adr_i[2]
  PIN wbs_adr_i[1]
    DIRECTION INPUT ;
    USE SIGNAL ;
    ANTENNAPARTIALMETALAREA 2.2327 LAYER met2  ;
    ANTENNAPARTIALMETALSIDEAREA 10.9375 LAYER met2  ;
    ANTENNAMODEL OXIDE1 ;
    ANTENNAGATEAREA 0.126 LAYER met2  ;
    ANTENNAMAXAREACAR 23.7357 LAYER met2  ;
    ANTENNAMAXSIDEAREACAR 105.516 LAYER met2  ;
    ANTENNAMAXCUTCAR 0.407937 LAYER via2  ;
    PORT
      LAYER met2 ;
        RECT 2828.700000 3445.075000 2828.840000 3445.560000 ;
    END
  END wbs_adr_i[1]
  PIN wbs_adr_i[0]
    DIRECTION INPUT ;
    USE SIGNAL ;
    ANTENNAPARTIALMETALAREA 4.8413 LAYER met2  ;
    ANTENNAPARTIALMETALSIDEAREA 23.7545 LAYER met2  ;
    ANTENNAMODEL OXIDE1 ;
    ANTENNAGATEAREA 0.4995 LAYER met2  ;
    ANTENNAMAXAREACAR 32.9947 LAYER met2  ;
    ANTENNAMAXSIDEAREACAR 151.267 LAYER met2  ;
    ANTENNAMAXCUTCAR 0.586508 LAYER via2  ;
    PORT
      LAYER met2 ;
        RECT 2852.160000 3445.075000 2852.300000 3445.560000 ;
    END
  END wbs_adr_i[0]
  PIN wbs_ack_o
    DIRECTION OUTPUT ;
    USE SIGNAL ;
    ANTENNADIFFAREA 0.429 LAYER met2  ;
    ANTENNAPARTIALMETALAREA 4.8707 LAYER met2  ;
    ANTENNAPARTIALMETALSIDEAREA 23.9015 LAYER met2  ;
    ANTENNAMODEL OXIDE1 ;
    ANTENNAGATEAREA 0.3735 LAYER met2  ;
    ANTENNAMAXAREACAR 39.3248 LAYER met2  ;
    ANTENNAMAXSIDEAREACAR 190.093 LAYER met2  ;
    ANTENNAMAXCUTCAR 0.586508 LAYER via2  ;
    PORT
      LAYER met2 ;
        RECT 2875.620000 3445.075000 2875.760000 3445.560000 ;
    END
  END wbs_ack_o
  PIN wbs_dat_o[31]
    DIRECTION OUTPUT ;
    USE SIGNAL ;
    ANTENNADIFFAREA 0.429 LAYER met2  ;
    ANTENNAPARTIALMETALAREA 4.2795 LAYER met2  ;
    ANTENNAPARTIALMETALSIDEAREA 21.1715 LAYER met2  ;
    PORT
      LAYER met2 ;
        RECT 2271.180000 3445.075000 2271.320000 3445.560000 ;
    END
  END wbs_dat_o[31]
  PIN wbs_dat_o[30]
    DIRECTION OUTPUT ;
    USE SIGNAL ;
    ANTENNADIFFAREA 0.429 LAYER met2  ;
    ANTENNAPARTIALMETALAREA 3.0111 LAYER met2  ;
    ANTENNAPARTIALMETALSIDEAREA 14.8295 LAYER met2  ;
    PORT
      LAYER met2 ;
        RECT 2288.660000 3445.075000 2288.800000 3445.560000 ;
    END
  END wbs_dat_o[30]
  PIN wbs_dat_o[29]
    DIRECTION OUTPUT ;
    USE SIGNAL ;
    ANTENNADIFFAREA 0.429 LAYER met2  ;
    ANTENNAPARTIALMETALAREA 3.4913 LAYER met2  ;
    ANTENNAPARTIALMETALSIDEAREA 17.2305 LAYER met2  ;
    PORT
      LAYER met2 ;
        RECT 2306.140000 3445.075000 2306.280000 3445.560000 ;
    END
  END wbs_dat_o[29]
  PIN wbs_dat_o[28]
    DIRECTION OUTPUT ;
    USE SIGNAL ;
    ANTENNADIFFAREA 0.429 LAYER met2  ;
    ANTENNAPARTIALMETALAREA 3.1275 LAYER met2  ;
    ANTENNAPARTIALMETALSIDEAREA 15.5295 LAYER met2  ;
    PORT
      LAYER met2 ;
        RECT 2324.080000 3445.075000 2324.220000 3445.560000 ;
    END
  END wbs_dat_o[28]
  PIN wbs_dat_o[27]
    DIRECTION OUTPUT ;
    USE SIGNAL ;
    ANTENNADIFFAREA 0.429 LAYER met2  ;
    ANTENNAPARTIALMETALAREA 5.9651 LAYER met2  ;
    ANTENNAPARTIALMETALSIDEAREA 29.5995 LAYER met2  ;
    PORT
      LAYER met2 ;
        RECT 2341.560000 3445.075000 2341.700000 3445.560000 ;
    END
  END wbs_dat_o[27]
  PIN wbs_dat_o[26]
    DIRECTION OUTPUT ;
    USE SIGNAL ;
    ANTENNADIFFAREA 0.429 LAYER met2  ;
    ANTENNAPARTIALMETALAREA 3.5725 LAYER met2  ;
    ANTENNAPARTIALMETALSIDEAREA 17.6365 LAYER met2  ;
    PORT
      LAYER met2 ;
        RECT 2359.040000 3445.075000 2359.180000 3445.560000 ;
    END
  END wbs_dat_o[26]
  PIN wbs_dat_o[25]
    DIRECTION OUTPUT ;
    USE SIGNAL ;
    ANTENNADIFFAREA 0.429 LAYER met2  ;
    ANTENNAPARTIALMETALAREA 2.2327 LAYER met2  ;
    ANTENNAPARTIALMETALSIDEAREA 10.9375 LAYER met2  ;
    PORT
      LAYER met2 ;
        RECT 2376.980000 3445.075000 2377.120000 3445.560000 ;
    END
  END wbs_dat_o[25]
  PIN wbs_dat_o[24]
    DIRECTION OUTPUT ;
    USE SIGNAL ;
    ANTENNADIFFAREA 0.429 LAYER met2  ;
    ANTENNAPARTIALMETALAREA 2.4091 LAYER met2  ;
    ANTENNAPARTIALMETALSIDEAREA 11.8195 LAYER met2  ;
    PORT
      LAYER met2 ;
        RECT 2394.460000 3445.075000 2394.600000 3445.560000 ;
    END
  END wbs_dat_o[24]
  PIN wbs_dat_o[23]
    DIRECTION OUTPUT ;
    USE SIGNAL ;
    ANTENNADIFFAREA 0.429 LAYER met2  ;
    ANTENNAPARTIALMETALAREA 3.8231 LAYER met2  ;
    ANTENNAPARTIALMETALSIDEAREA 18.8895 LAYER met2  ;
    PORT
      LAYER met2 ;
        RECT 2411.940000 3445.075000 2412.080000 3445.560000 ;
    END
  END wbs_dat_o[23]
  PIN wbs_dat_o[22]
    DIRECTION OUTPUT ;
    USE SIGNAL ;
    ANTENNADIFFAREA 0.429 LAYER met2  ;
    ANTENNAPARTIALMETALAREA 5.4765 LAYER met2  ;
    ANTENNAPARTIALMETALSIDEAREA 27.1565 LAYER met2  ;
    PORT
      LAYER met2 ;
        RECT 2429.420000 3445.075000 2429.560000 3445.560000 ;
    END
  END wbs_dat_o[22]
  PIN wbs_dat_o[21]
    DIRECTION OUTPUT ;
    USE SIGNAL ;
    ANTENNADIFFAREA 0.429 LAYER met2  ;
    ANTENNAPARTIALMETALAREA 2.7423 LAYER met2  ;
    ANTENNAPARTIALMETALSIDEAREA 13.4855 LAYER met2  ;
    PORT
      LAYER met2 ;
        RECT 2447.360000 3445.075000 2447.500000 3445.560000 ;
    END
  END wbs_dat_o[21]
  PIN wbs_dat_o[20]
    DIRECTION OUTPUT ;
    USE SIGNAL ;
    ANTENNADIFFAREA 0.429 LAYER met2  ;
    ANTENNAPARTIALMETALAREA 7.1103 LAYER met2  ;
    ANTENNAPARTIALMETALSIDEAREA 35.3255 LAYER met2  ;
    PORT
      LAYER met2 ;
        RECT 2464.840000 3445.075000 2464.980000 3445.560000 ;
    END
  END wbs_dat_o[20]
  PIN wbs_dat_o[19]
    DIRECTION OUTPUT ;
    USE SIGNAL ;
    ANTENNADIFFAREA 0.429 LAYER met2  ;
    ANTENNAPARTIALMETALAREA 4.1087 LAYER met2  ;
    ANTENNAPARTIALMETALSIDEAREA 20.3175 LAYER met2  ;
    PORT
      LAYER met2 ;
        RECT 2482.320000 3445.075000 2482.460000 3445.560000 ;
    END
  END wbs_dat_o[19]
  PIN wbs_dat_o[18]
    DIRECTION OUTPUT ;
    USE SIGNAL ;
    ANTENNADIFFAREA 0.429 LAYER met2  ;
    ANTENNAPARTIALMETALAREA 7.2573 LAYER met2  ;
    ANTENNAPARTIALMETALSIDEAREA 36.0605 LAYER met2  ;
    PORT
      LAYER met2 ;
        RECT 2499.800000 3445.075000 2499.940000 3445.560000 ;
    END
  END wbs_dat_o[18]
  PIN wbs_dat_o[17]
    DIRECTION OUTPUT ;
    USE SIGNAL ;
    ANTENNADIFFAREA 0.429 LAYER met2  ;
    ANTENNAPARTIALMETALAREA 6.4747 LAYER met2  ;
    ANTENNAPARTIALMETALSIDEAREA 32.1475 LAYER met2  ;
    PORT
      LAYER met2 ;
        RECT 2517.740000 3445.075000 2517.880000 3445.560000 ;
    END
  END wbs_dat_o[17]
  PIN wbs_dat_o[16]
    DIRECTION OUTPUT ;
    USE SIGNAL ;
    ANTENNADIFFAREA 0.429 LAYER met2  ;
    ANTENNAPARTIALMETALAREA 6.5319 LAYER met2  ;
    ANTENNAPARTIALMETALSIDEAREA 32.3155 LAYER met2  ;
    PORT
      LAYER met2 ;
        RECT 2535.220000 3445.075000 2535.360000 3445.560000 ;
    END
  END wbs_dat_o[16]
  PIN wbs_dat_o[15]
    DIRECTION OUTPUT ;
    USE SIGNAL ;
    ANTENNADIFFAREA 0.429 LAYER met2  ;
    ANTENNAPARTIALMETALAREA 4.5231 LAYER met2  ;
    ANTENNAPARTIALMETALSIDEAREA 22.3895 LAYER met2  ;
    PORT
      LAYER met2 ;
        RECT 2552.700000 3445.075000 2552.840000 3445.560000 ;
    END
  END wbs_dat_o[15]
  PIN wbs_dat_o[14]
    DIRECTION OUTPUT ;
    USE SIGNAL ;
    ANTENNADIFFAREA 0.429 LAYER met2  ;
    ANTENNAPARTIALMETALAREA 3.2403 LAYER met2  ;
    ANTENNAPARTIALMETALSIDEAREA 15.7395 LAYER met2  ;
    PORT
      LAYER met2 ;
        RECT 2570.640000 3445.075000 2570.780000 3445.560000 ;
    END
  END wbs_dat_o[14]
  PIN wbs_dat_o[13]
    DIRECTION OUTPUT ;
    USE SIGNAL ;
    ANTENNADIFFAREA 0.429 LAYER met2  ;
    ANTENNAPARTIALMETALAREA 4.2375 LAYER met2  ;
    ANTENNAPARTIALMETALSIDEAREA 20.9615 LAYER met2  ;
    PORT
      LAYER met2 ;
        RECT 2588.120000 3445.075000 2588.260000 3445.560000 ;
    END
  END wbs_dat_o[13]
  PIN wbs_dat_o[12]
    DIRECTION OUTPUT ;
    USE SIGNAL ;
    ANTENNADIFFAREA 0.429 LAYER met2  ;
    ANTENNAPARTIALMETALAREA 2.6688 LAYER met2  ;
    ANTENNAPARTIALMETALSIDEAREA 13.118 LAYER met2  ;
    PORT
      LAYER met2 ;
        RECT 2605.600000 3445.075000 2605.740000 3445.560000 ;
    END
  END wbs_dat_o[12]
  PIN wbs_dat_o[11]
    DIRECTION OUTPUT ;
    USE SIGNAL ;
    ANTENNADIFFAREA 0.429 LAYER met2  ;
    ANTENNAPARTIALMETALAREA 4.5175 LAYER met2  ;
    ANTENNAPARTIALMETALSIDEAREA 22.3615 LAYER met2  ;
    PORT
      LAYER met2 ;
        RECT 2623.080000 3445.075000 2623.220000 3445.560000 ;
    END
  END wbs_dat_o[11]
  PIN wbs_dat_o[10]
    DIRECTION OUTPUT ;
    USE SIGNAL ;
    ANTENNADIFFAREA 0.429 LAYER met2  ;
    ANTENNAPARTIALMETALAREA 5.9791 LAYER met2  ;
    ANTENNAPARTIALMETALSIDEAREA 29.6695 LAYER met2  ;
    PORT
      LAYER met2 ;
        RECT 2641.020000 3445.075000 2641.160000 3445.560000 ;
    END
  END wbs_dat_o[10]
  PIN wbs_dat_o[9]
    DIRECTION OUTPUT ;
    USE SIGNAL ;
    ANTENNAPARTIALMETALAREA 0.7826 LAYER met2  ;
    ANTENNAPARTIALMETALSIDEAREA 3.752 LAYER met2  ;
    ANTENNAPARTIALCUTAREA 0.04 LAYER via2  ;
    ANTENNAPARTIALMETALAREA 1.20625 LAYER met3  ;
    ANTENNAPARTIALMETALSIDEAREA 6.888 LAYER met3  ;
    ANTENNAPARTIALCUTAREA 0.04 LAYER via3  ;
    ANTENNADIFFAREA 0.429 LAYER met4  ;
    ANTENNAPARTIALMETALAREA 6.8256 LAYER met4  ;
    ANTENNAPARTIALMETALSIDEAREA 37.344 LAYER met4  ;
    PORT
      LAYER met2 ;
        RECT 2658.500000 3445.075000 2658.640000 3445.560000 ;
    END
  END wbs_dat_o[9]
  PIN wbs_dat_o[8]
    DIRECTION OUTPUT ;
    USE SIGNAL ;
    ANTENNAPARTIALMETALAREA 0.5479 LAYER met2  ;
    ANTENNAPARTIALMETALSIDEAREA 2.4605 LAYER met2  ;
    ANTENNAPARTIALCUTAREA 0.04 LAYER via2  ;
    ANTENNAPARTIALMETALAREA 0.331 LAYER met3  ;
    ANTENNAPARTIALMETALSIDEAREA 2.232 LAYER met3  ;
    ANTENNAPARTIALCUTAREA 0.04 LAYER via3  ;
    ANTENNADIFFAREA 0.429 LAYER met4  ;
    ANTENNAPARTIALMETALAREA 1.2168 LAYER met4  ;
    ANTENNAPARTIALMETALSIDEAREA 6.96 LAYER met4  ;
    PORT
      LAYER met2 ;
        RECT 2675.980000 3445.075000 2676.120000 3445.560000 ;
    END
  END wbs_dat_o[8]
  PIN wbs_dat_o[7]
    DIRECTION OUTPUT ;
    USE SIGNAL ;
    ANTENNADIFFAREA 0.3406 LAYER met2  ;
    ANTENNAPARTIALMETALAREA 7.4407 LAYER met2  ;
    ANTENNAPARTIALMETALSIDEAREA 36.9775 LAYER met2  ;
    PORT
      LAYER met2 ;
        RECT 2693.460000 3445.075000 2693.600000 3445.560000 ;
    END
  END wbs_dat_o[7]
  PIN wbs_dat_o[6]
    DIRECTION OUTPUT ;
    USE SIGNAL ;
    ANTENNAPARTIALMETALAREA 6.5684 LAYER met2  ;
    ANTENNAPARTIALMETALSIDEAREA 32.445 LAYER met2  ;
    ANTENNAPARTIALCUTAREA 0.04 LAYER via2  ;
    ANTENNADIFFAREA 0.429 LAYER met3  ;
    ANTENNAPARTIALMETALAREA 6.7428 LAYER met3  ;
    ANTENNAPARTIALMETALSIDEAREA 36.432 LAYER met3  ;
    PORT
      LAYER met2 ;
        RECT 2711.400000 3445.075000 2711.540000 3445.560000 ;
    END
  END wbs_dat_o[6]
  PIN wbs_dat_o[5]
    DIRECTION OUTPUT ;
    USE SIGNAL ;
    ANTENNADIFFAREA 0.3406 LAYER met2  ;
    ANTENNAPARTIALMETALAREA 2.9943 LAYER met2  ;
    ANTENNAPARTIALMETALSIDEAREA 14.7455 LAYER met2  ;
    PORT
      LAYER met2 ;
        RECT 2728.880000 3445.075000 2729.020000 3445.560000 ;
    END
  END wbs_dat_o[5]
  PIN wbs_dat_o[4]
    DIRECTION OUTPUT ;
    USE SIGNAL ;
    ANTENNADIFFAREA 0.3406 LAYER met2  ;
    ANTENNAPARTIALMETALAREA 3.1159 LAYER met2  ;
    ANTENNAPARTIALMETALSIDEAREA 15.2355 LAYER met2  ;
    PORT
      LAYER met2 ;
        RECT 2746.360000 3445.075000 2746.500000 3445.560000 ;
    END
  END wbs_dat_o[4]
  PIN wbs_dat_o[3]
    DIRECTION OUTPUT ;
    USE SIGNAL ;
    ANTENNADIFFAREA 0.3406 LAYER met2  ;
    ANTENNAPARTIALMETALAREA 6.8023 LAYER met2  ;
    ANTENNAPARTIALMETALSIDEAREA 33.7855 LAYER met2  ;
    PORT
      LAYER met2 ;
        RECT 2769.820000 3445.075000 2769.960000 3445.560000 ;
    END
  END wbs_dat_o[3]
  PIN wbs_dat_o[2]
    DIRECTION OUTPUT ;
    USE SIGNAL ;
    ANTENNADIFFAREA 0.3406 LAYER met2  ;
    ANTENNAPARTIALMETALAREA 5.2173 LAYER met2  ;
    ANTENNAPARTIALMETALSIDEAREA 25.7425 LAYER met2  ;
    PORT
      LAYER met2 ;
        RECT 2793.280000 3445.075000 2793.420000 3445.560000 ;
    END
  END wbs_dat_o[2]
  PIN wbs_dat_o[1]
    DIRECTION OUTPUT ;
    USE SIGNAL ;
    ANTENNADIFFAREA 0.3406 LAYER met2  ;
    ANTENNAPARTIALMETALAREA 5.6723 LAYER met2  ;
    ANTENNAPARTIALMETALSIDEAREA 28.0175 LAYER met2  ;
    PORT
      LAYER met2 ;
        RECT 2816.740000 3445.075000 2816.880000 3445.560000 ;
    END
  END wbs_dat_o[1]
  PIN wbs_dat_o[0]
    DIRECTION OUTPUT ;
    USE SIGNAL ;
    ANTENNADIFFAREA 0.3406 LAYER met2  ;
    ANTENNAPARTIALMETALAREA 0.7781 LAYER met2  ;
    ANTENNAPARTIALMETALSIDEAREA 3.6645 LAYER met2  ;
    PORT
      LAYER met2 ;
        RECT 2840.200000 3445.075000 2840.340000 3445.560000 ;
    END
  END wbs_dat_o[0]
  PIN la_data_in[127]
    DIRECTION INPUT ;
    USE SIGNAL ;
    PORT
      LAYER met2 ;
        RECT 29.140000 3445.075000 29.280000 3445.560000 ;
    END
  END la_data_in[127]
  PIN la_data_in[126]
    DIRECTION INPUT ;
    USE SIGNAL ;
    PORT
      LAYER met2 ;
        RECT 47.080000 3445.075000 47.220000 3445.560000 ;
    END
  END la_data_in[126]
  PIN la_data_in[125]
    DIRECTION INPUT ;
    USE SIGNAL ;
    PORT
      LAYER met2 ;
        RECT 64.560000 3445.075000 64.700000 3445.560000 ;
    END
  END la_data_in[125]
  PIN la_data_in[124]
    DIRECTION INPUT ;
    USE SIGNAL ;
    PORT
      LAYER met2 ;
        RECT 82.040000 3445.075000 82.180000 3445.560000 ;
    END
  END la_data_in[124]
  PIN la_data_in[123]
    DIRECTION INPUT ;
    USE SIGNAL ;
    PORT
      LAYER met2 ;
        RECT 99.520000 3445.075000 99.660000 3445.560000 ;
    END
  END la_data_in[123]
  PIN la_data_in[122]
    DIRECTION INPUT ;
    USE SIGNAL ;
    PORT
      LAYER met2 ;
        RECT 117.460000 3445.075000 117.600000 3445.560000 ;
    END
  END la_data_in[122]
  PIN la_data_in[121]
    DIRECTION INPUT ;
    USE SIGNAL ;
    PORT
      LAYER met2 ;
        RECT 134.940000 3445.075000 135.080000 3445.560000 ;
    END
  END la_data_in[121]
  PIN la_data_in[120]
    DIRECTION INPUT ;
    USE SIGNAL ;
    PORT
      LAYER met2 ;
        RECT 152.420000 3445.075000 152.560000 3445.560000 ;
    END
  END la_data_in[120]
  PIN la_data_in[119]
    DIRECTION INPUT ;
    USE SIGNAL ;
    PORT
      LAYER met2 ;
        RECT 169.900000 3445.075000 170.040000 3445.560000 ;
    END
  END la_data_in[119]
  PIN la_data_in[118]
    DIRECTION INPUT ;
    USE SIGNAL ;
    PORT
      LAYER met2 ;
        RECT 187.840000 3445.075000 187.980000 3445.560000 ;
    END
  END la_data_in[118]
  PIN la_data_in[117]
    DIRECTION INPUT ;
    USE SIGNAL ;
    PORT
      LAYER met2 ;
        RECT 205.320000 3445.075000 205.460000 3445.560000 ;
    END
  END la_data_in[117]
  PIN la_data_in[116]
    DIRECTION INPUT ;
    USE SIGNAL ;
    PORT
      LAYER met2 ;
        RECT 222.800000 3445.075000 222.940000 3445.560000 ;
    END
  END la_data_in[116]
  PIN la_data_in[115]
    DIRECTION INPUT ;
    USE SIGNAL ;
    PORT
      LAYER met2 ;
        RECT 240.740000 3445.075000 240.880000 3445.560000 ;
    END
  END la_data_in[115]
  PIN la_data_in[114]
    DIRECTION INPUT ;
    USE SIGNAL ;
    PORT
      LAYER met2 ;
        RECT 258.220000 3445.075000 258.360000 3445.560000 ;
    END
  END la_data_in[114]
  PIN la_data_in[113]
    DIRECTION INPUT ;
    USE SIGNAL ;
    PORT
      LAYER met2 ;
        RECT 275.700000 3445.075000 275.840000 3445.560000 ;
    END
  END la_data_in[113]
  PIN la_data_in[112]
    DIRECTION INPUT ;
    USE SIGNAL ;
    PORT
      LAYER met2 ;
        RECT 293.180000 3445.075000 293.320000 3445.560000 ;
    END
  END la_data_in[112]
  PIN la_data_in[111]
    DIRECTION INPUT ;
    USE SIGNAL ;
    PORT
      LAYER met2 ;
        RECT 311.120000 3445.075000 311.260000 3445.560000 ;
    END
  END la_data_in[111]
  PIN la_data_in[110]
    DIRECTION INPUT ;
    USE SIGNAL ;
    PORT
      LAYER met2 ;
        RECT 328.600000 3445.075000 328.740000 3445.560000 ;
    END
  END la_data_in[110]
  PIN la_data_in[109]
    DIRECTION INPUT ;
    USE SIGNAL ;
    PORT
      LAYER met2 ;
        RECT 346.080000 3445.075000 346.220000 3445.560000 ;
    END
  END la_data_in[109]
  PIN la_data_in[108]
    DIRECTION INPUT ;
    USE SIGNAL ;
    PORT
      LAYER met2 ;
        RECT 364.020000 3445.075000 364.160000 3445.560000 ;
    END
  END la_data_in[108]
  PIN la_data_in[107]
    DIRECTION INPUT ;
    USE SIGNAL ;
    PORT
      LAYER met2 ;
        RECT 381.500000 3445.075000 381.640000 3445.560000 ;
    END
  END la_data_in[107]
  PIN la_data_in[106]
    DIRECTION INPUT ;
    USE SIGNAL ;
    PORT
      LAYER met2 ;
        RECT 398.980000 3445.075000 399.120000 3445.560000 ;
    END
  END la_data_in[106]
  PIN la_data_in[105]
    DIRECTION INPUT ;
    USE SIGNAL ;
    PORT
      LAYER met2 ;
        RECT 416.460000 3445.075000 416.600000 3445.560000 ;
    END
  END la_data_in[105]
  PIN la_data_in[104]
    DIRECTION INPUT ;
    USE SIGNAL ;
    PORT
      LAYER met2 ;
        RECT 434.400000 3445.075000 434.540000 3445.560000 ;
    END
  END la_data_in[104]
  PIN la_data_in[103]
    DIRECTION INPUT ;
    USE SIGNAL ;
    PORT
      LAYER met2 ;
        RECT 451.880000 3445.075000 452.020000 3445.560000 ;
    END
  END la_data_in[103]
  PIN la_data_in[102]
    DIRECTION INPUT ;
    USE SIGNAL ;
    PORT
      LAYER met2 ;
        RECT 469.360000 3445.075000 469.500000 3445.560000 ;
    END
  END la_data_in[102]
  PIN la_data_in[101]
    DIRECTION INPUT ;
    USE SIGNAL ;
    PORT
      LAYER met2 ;
        RECT 486.840000 3445.075000 486.980000 3445.560000 ;
    END
  END la_data_in[101]
  PIN la_data_in[100]
    DIRECTION INPUT ;
    USE SIGNAL ;
    PORT
      LAYER met2 ;
        RECT 504.780000 3445.075000 504.920000 3445.560000 ;
    END
  END la_data_in[100]
  PIN la_data_in[99]
    DIRECTION INPUT ;
    USE SIGNAL ;
    PORT
      LAYER met2 ;
        RECT 522.260000 3445.075000 522.400000 3445.560000 ;
    END
  END la_data_in[99]
  PIN la_data_in[98]
    DIRECTION INPUT ;
    USE SIGNAL ;
    PORT
      LAYER met2 ;
        RECT 539.740000 3445.075000 539.880000 3445.560000 ;
    END
  END la_data_in[98]
  PIN la_data_in[97]
    DIRECTION INPUT ;
    USE SIGNAL ;
    PORT
      LAYER met2 ;
        RECT 557.680000 3445.075000 557.820000 3445.560000 ;
    END
  END la_data_in[97]
  PIN la_data_in[96]
    DIRECTION INPUT ;
    USE SIGNAL ;
    ANTENNAPARTIALMETALAREA 4.8365 LAYER met2  ;
    ANTENNAPARTIALMETALSIDEAREA 23.8385 LAYER met2  ;
    ANTENNAMODEL OXIDE1 ;
    ANTENNAGATEAREA 0.159 LAYER met2  ;
    ANTENNAMAXAREACAR 33.528 LAYER met2  ;
    ANTENNAMAXSIDEAREACAR 156.39 LAYER met2  ;
    ANTENNAMAXCUTCAR 0.32327 LAYER via2  ;
    PORT
      LAYER met2 ;
        RECT 575.160000 3445.075000 575.300000 3445.560000 ;
    END
  END la_data_in[96]
  PIN la_data_in[95]
    DIRECTION INPUT ;
    USE SIGNAL ;
    PORT
      LAYER met2 ;
        RECT 592.640000 3445.075000 592.780000 3445.560000 ;
    END
  END la_data_in[95]
  PIN la_data_in[94]
    DIRECTION INPUT ;
    USE SIGNAL ;
    PORT
      LAYER met2 ;
        RECT 610.120000 3445.075000 610.260000 3445.560000 ;
    END
  END la_data_in[94]
  PIN la_data_in[93]
    DIRECTION INPUT ;
    USE SIGNAL ;
    PORT
      LAYER met2 ;
        RECT 628.060000 3445.075000 628.200000 3445.560000 ;
    END
  END la_data_in[93]
  PIN la_data_in[92]
    DIRECTION INPUT ;
    USE SIGNAL ;
    PORT
      LAYER met2 ;
        RECT 645.540000 3445.075000 645.680000 3445.560000 ;
    END
  END la_data_in[92]
  PIN la_data_in[91]
    DIRECTION INPUT ;
    USE SIGNAL ;
    PORT
      LAYER met2 ;
        RECT 663.020000 3445.075000 663.160000 3445.560000 ;
    END
  END la_data_in[91]
  PIN la_data_in[90]
    DIRECTION INPUT ;
    USE SIGNAL ;
    PORT
      LAYER met2 ;
        RECT 680.500000 3445.075000 680.640000 3445.560000 ;
    END
  END la_data_in[90]
  PIN la_data_in[89]
    DIRECTION INPUT ;
    USE SIGNAL ;
    PORT
      LAYER met2 ;
        RECT 698.440000 3445.075000 698.580000 3445.560000 ;
    END
  END la_data_in[89]
  PIN la_data_in[88]
    DIRECTION INPUT ;
    USE SIGNAL ;
    PORT
      LAYER met2 ;
        RECT 715.920000 3445.075000 716.060000 3445.560000 ;
    END
  END la_data_in[88]
  PIN la_data_in[87]
    DIRECTION INPUT ;
    USE SIGNAL ;
    PORT
      LAYER met2 ;
        RECT 733.400000 3445.075000 733.540000 3445.560000 ;
    END
  END la_data_in[87]
  PIN la_data_in[86]
    DIRECTION INPUT ;
    USE SIGNAL ;
    PORT
      LAYER met2 ;
        RECT 751.340000 3445.075000 751.480000 3445.560000 ;
    END
  END la_data_in[86]
  PIN la_data_in[85]
    DIRECTION INPUT ;
    USE SIGNAL ;
    PORT
      LAYER met2 ;
        RECT 768.820000 3445.075000 768.960000 3445.560000 ;
    END
  END la_data_in[85]
  PIN la_data_in[84]
    DIRECTION INPUT ;
    USE SIGNAL ;
    PORT
      LAYER met2 ;
        RECT 786.300000 3445.075000 786.440000 3445.560000 ;
    END
  END la_data_in[84]
  PIN la_data_in[83]
    DIRECTION INPUT ;
    USE SIGNAL ;
    PORT
      LAYER met2 ;
        RECT 803.780000 3445.075000 803.920000 3445.560000 ;
    END
  END la_data_in[83]
  PIN la_data_in[82]
    DIRECTION INPUT ;
    USE SIGNAL ;
    PORT
      LAYER met2 ;
        RECT 821.720000 3445.075000 821.860000 3445.560000 ;
    END
  END la_data_in[82]
  PIN la_data_in[81]
    DIRECTION INPUT ;
    USE SIGNAL ;
    PORT
      LAYER met2 ;
        RECT 839.200000 3445.075000 839.340000 3445.560000 ;
    END
  END la_data_in[81]
  PIN la_data_in[80]
    DIRECTION INPUT ;
    USE SIGNAL ;
    PORT
      LAYER met2 ;
        RECT 856.680000 3445.075000 856.820000 3445.560000 ;
    END
  END la_data_in[80]
  PIN la_data_in[79]
    DIRECTION INPUT ;
    USE SIGNAL ;
    PORT
      LAYER met2 ;
        RECT 874.160000 3445.075000 874.300000 3445.560000 ;
    END
  END la_data_in[79]
  PIN la_data_in[78]
    DIRECTION INPUT ;
    USE SIGNAL ;
    PORT
      LAYER met2 ;
        RECT 892.100000 3445.075000 892.240000 3445.560000 ;
    END
  END la_data_in[78]
  PIN la_data_in[77]
    DIRECTION INPUT ;
    USE SIGNAL ;
    PORT
      LAYER met2 ;
        RECT 909.580000 3445.075000 909.720000 3445.560000 ;
    END
  END la_data_in[77]
  PIN la_data_in[76]
    DIRECTION INPUT ;
    USE SIGNAL ;
    PORT
      LAYER met2 ;
        RECT 927.060000 3445.075000 927.200000 3445.560000 ;
    END
  END la_data_in[76]
  PIN la_data_in[75]
    DIRECTION INPUT ;
    USE SIGNAL ;
    PORT
      LAYER met2 ;
        RECT 945.000000 3445.075000 945.140000 3445.560000 ;
    END
  END la_data_in[75]
  PIN la_data_in[74]
    DIRECTION INPUT ;
    USE SIGNAL ;
    PORT
      LAYER met2 ;
        RECT 962.480000 3445.075000 962.620000 3445.560000 ;
    END
  END la_data_in[74]
  PIN la_data_in[73]
    DIRECTION INPUT ;
    USE SIGNAL ;
    PORT
      LAYER met2 ;
        RECT 979.960000 3445.075000 980.100000 3445.560000 ;
    END
  END la_data_in[73]
  PIN la_data_in[72]
    DIRECTION INPUT ;
    USE SIGNAL ;
    PORT
      LAYER met2 ;
        RECT 997.440000 3445.075000 997.580000 3445.560000 ;
    END
  END la_data_in[72]
  PIN la_data_in[71]
    DIRECTION INPUT ;
    USE SIGNAL ;
    PORT
      LAYER met2 ;
        RECT 1015.380000 3445.075000 1015.520000 3445.560000 ;
    END
  END la_data_in[71]
  PIN la_data_in[70]
    DIRECTION INPUT ;
    USE SIGNAL ;
    PORT
      LAYER met2 ;
        RECT 1032.860000 3445.075000 1033.000000 3445.560000 ;
    END
  END la_data_in[70]
  PIN la_data_in[69]
    DIRECTION INPUT ;
    USE SIGNAL ;
    PORT
      LAYER met2 ;
        RECT 1050.340000 3445.075000 1050.480000 3445.560000 ;
    END
  END la_data_in[69]
  PIN la_data_in[68]
    DIRECTION INPUT ;
    USE SIGNAL ;
    PORT
      LAYER met2 ;
        RECT 1067.820000 3445.075000 1067.960000 3445.560000 ;
    END
  END la_data_in[68]
  PIN la_data_in[67]
    DIRECTION INPUT ;
    USE SIGNAL ;
    PORT
      LAYER met2 ;
        RECT 1085.760000 3445.075000 1085.900000 3445.560000 ;
    END
  END la_data_in[67]
  PIN la_data_in[66]
    DIRECTION INPUT ;
    USE SIGNAL ;
    PORT
      LAYER met2 ;
        RECT 1103.240000 3445.075000 1103.380000 3445.560000 ;
    END
  END la_data_in[66]
  PIN la_data_in[65]
    DIRECTION INPUT ;
    USE SIGNAL ;
    PORT
      LAYER met2 ;
        RECT 1120.720000 3445.075000 1120.860000 3445.560000 ;
    END
  END la_data_in[65]
  PIN la_data_in[64]
    DIRECTION INPUT ;
    USE SIGNAL ;
    PORT
      LAYER met2 ;
        RECT 1138.660000 3445.075000 1138.800000 3445.560000 ;
    END
  END la_data_in[64]
  PIN la_data_in[63]
    DIRECTION INPUT ;
    USE SIGNAL ;
    PORT
      LAYER met2 ;
        RECT 1156.140000 3445.075000 1156.280000 3445.560000 ;
    END
  END la_data_in[63]
  PIN la_data_in[62]
    DIRECTION INPUT ;
    USE SIGNAL ;
    PORT
      LAYER met2 ;
        RECT 1173.620000 3445.075000 1173.760000 3445.560000 ;
    END
  END la_data_in[62]
  PIN la_data_in[61]
    DIRECTION INPUT ;
    USE SIGNAL ;
    PORT
      LAYER met2 ;
        RECT 1191.100000 3445.075000 1191.240000 3445.560000 ;
    END
  END la_data_in[61]
  PIN la_data_in[60]
    DIRECTION INPUT ;
    USE SIGNAL ;
    PORT
      LAYER met2 ;
        RECT 1209.040000 3445.075000 1209.180000 3445.560000 ;
    END
  END la_data_in[60]
  PIN la_data_in[59]
    DIRECTION INPUT ;
    USE SIGNAL ;
    PORT
      LAYER met2 ;
        RECT 1226.520000 3445.075000 1226.660000 3445.560000 ;
    END
  END la_data_in[59]
  PIN la_data_in[58]
    DIRECTION INPUT ;
    USE SIGNAL ;
    PORT
      LAYER met2 ;
        RECT 1244.000000 3445.075000 1244.140000 3445.560000 ;
    END
  END la_data_in[58]
  PIN la_data_in[57]
    DIRECTION INPUT ;
    USE SIGNAL ;
    PORT
      LAYER met2 ;
        RECT 1261.480000 3445.075000 1261.620000 3445.560000 ;
    END
  END la_data_in[57]
  PIN la_data_in[56]
    DIRECTION INPUT ;
    USE SIGNAL ;
    PORT
      LAYER met2 ;
        RECT 1279.420000 3445.075000 1279.560000 3445.560000 ;
    END
  END la_data_in[56]
  PIN la_data_in[55]
    DIRECTION INPUT ;
    USE SIGNAL ;
    PORT
      LAYER met2 ;
        RECT 1296.900000 3445.075000 1297.040000 3445.560000 ;
    END
  END la_data_in[55]
  PIN la_data_in[54]
    DIRECTION INPUT ;
    USE SIGNAL ;
    PORT
      LAYER met2 ;
        RECT 1314.380000 3445.075000 1314.520000 3445.560000 ;
    END
  END la_data_in[54]
  PIN la_data_in[53]
    DIRECTION INPUT ;
    USE SIGNAL ;
    PORT
      LAYER met2 ;
        RECT 1332.320000 3445.075000 1332.460000 3445.560000 ;
    END
  END la_data_in[53]
  PIN la_data_in[52]
    DIRECTION INPUT ;
    USE SIGNAL ;
    PORT
      LAYER met2 ;
        RECT 1349.800000 3445.075000 1349.940000 3445.560000 ;
    END
  END la_data_in[52]
  PIN la_data_in[51]
    DIRECTION INPUT ;
    USE SIGNAL ;
    PORT
      LAYER met2 ;
        RECT 1367.280000 3445.075000 1367.420000 3445.560000 ;
    END
  END la_data_in[51]
  PIN la_data_in[50]
    DIRECTION INPUT ;
    USE SIGNAL ;
    PORT
      LAYER met2 ;
        RECT 1384.760000 3445.075000 1384.900000 3445.560000 ;
    END
  END la_data_in[50]
  PIN la_data_in[49]
    DIRECTION INPUT ;
    USE SIGNAL ;
    PORT
      LAYER met2 ;
        RECT 1402.700000 3445.075000 1402.840000 3445.560000 ;
    END
  END la_data_in[49]
  PIN la_data_in[48]
    DIRECTION INPUT ;
    USE SIGNAL ;
    PORT
      LAYER met2 ;
        RECT 1420.180000 3445.075000 1420.320000 3445.560000 ;
    END
  END la_data_in[48]
  PIN la_data_in[47]
    DIRECTION INPUT ;
    USE SIGNAL ;
    PORT
      LAYER met2 ;
        RECT 1437.660000 3445.075000 1437.800000 3445.560000 ;
    END
  END la_data_in[47]
  PIN la_data_in[46]
    DIRECTION INPUT ;
    USE SIGNAL ;
    PORT
      LAYER met2 ;
        RECT 1455.600000 3445.075000 1455.740000 3445.560000 ;
    END
  END la_data_in[46]
  PIN la_data_in[45]
    DIRECTION INPUT ;
    USE SIGNAL ;
    PORT
      LAYER met2 ;
        RECT 1473.080000 3445.075000 1473.220000 3445.560000 ;
    END
  END la_data_in[45]
  PIN la_data_in[44]
    DIRECTION INPUT ;
    USE SIGNAL ;
    PORT
      LAYER met2 ;
        RECT 1490.560000 3445.075000 1490.700000 3445.560000 ;
    END
  END la_data_in[44]
  PIN la_data_in[43]
    DIRECTION INPUT ;
    USE SIGNAL ;
    PORT
      LAYER met2 ;
        RECT 1508.040000 3445.075000 1508.180000 3445.560000 ;
    END
  END la_data_in[43]
  PIN la_data_in[42]
    DIRECTION INPUT ;
    USE SIGNAL ;
    PORT
      LAYER met2 ;
        RECT 1525.980000 3445.075000 1526.120000 3445.560000 ;
    END
  END la_data_in[42]
  PIN la_data_in[41]
    DIRECTION INPUT ;
    USE SIGNAL ;
    PORT
      LAYER met2 ;
        RECT 1543.460000 3445.075000 1543.600000 3445.560000 ;
    END
  END la_data_in[41]
  PIN la_data_in[40]
    DIRECTION INPUT ;
    USE SIGNAL ;
    PORT
      LAYER met2 ;
        RECT 1560.940000 3445.075000 1561.080000 3445.560000 ;
    END
  END la_data_in[40]
  PIN la_data_in[39]
    DIRECTION INPUT ;
    USE SIGNAL ;
    PORT
      LAYER met2 ;
        RECT 1578.420000 3445.075000 1578.560000 3445.560000 ;
    END
  END la_data_in[39]
  PIN la_data_in[38]
    DIRECTION INPUT ;
    USE SIGNAL ;
    PORT
      LAYER met2 ;
        RECT 1596.360000 3445.075000 1596.500000 3445.560000 ;
    END
  END la_data_in[38]
  PIN la_data_in[37]
    DIRECTION INPUT ;
    USE SIGNAL ;
    ANTENNAPARTIALMETALAREA 0.3234 LAYER met2  ;
    ANTENNAPARTIALMETALSIDEAREA 1.456 LAYER met2  ;
    ANTENNAPARTIALCUTAREA 0.04 LAYER via2  ;
    ANTENNAPARTIALMETALAREA 100.195 LAYER met3  ;
    ANTENNAPARTIALMETALSIDEAREA 534.84 LAYER met3  ;
    ANTENNAPARTIALCUTAREA 0.04 LAYER via3  ;
    ANTENNAPARTIALMETALAREA 3.6192 LAYER met4  ;
    ANTENNAPARTIALMETALSIDEAREA 21.184 LAYER met4  ;
    ANTENNAMODEL OXIDE1 ;
    ANTENNAGATEAREA 0.1965 LAYER met4  ;
    ANTENNAMAXAREACAR 38.2738 LAYER met4  ;
    ANTENNAMAXSIDEAREACAR 209.13 LAYER met4  ;
    ANTENNAMAXCUTCAR 0.668702 LAYER via4  ;
    PORT
      LAYER met2 ;
        RECT 1613.840000 3445.075000 1613.980000 3445.560000 ;
    END
  END la_data_in[37]
  PIN la_data_in[36]
    DIRECTION INPUT ;
    USE SIGNAL ;
    ANTENNAPARTIALMETALAREA 1.9059 LAYER met2  ;
    ANTENNAPARTIALMETALSIDEAREA 9.2505 LAYER met2  ;
    ANTENNAPARTIALCUTAREA 0.04 LAYER via2  ;
    ANTENNAPARTIALMETALAREA 1.68925 LAYER met3  ;
    ANTENNAPARTIALMETALSIDEAREA 9.464 LAYER met3  ;
    ANTENNAPARTIALCUTAREA 0.04 LAYER via3  ;
    ANTENNAPARTIALMETALAREA 4.4466 LAYER met4  ;
    ANTENNAPARTIALMETALSIDEAREA 24.656 LAYER met4  ;
    ANTENNAMODEL OXIDE1 ;
    ANTENNAGATEAREA 0.159 LAYER met4  ;
    ANTENNAMAXAREACAR 67.5588 LAYER met4  ;
    ANTENNAMAXSIDEAREACAR 360.415 LAYER met4  ;
    ANTENNAMAXCUTCAR 0.826415 LAYER via4  ;
    PORT
      LAYER met2 ;
        RECT 1631.320000 3445.075000 1631.460000 3445.560000 ;
    END
  END la_data_in[36]
  PIN la_data_in[35]
    DIRECTION INPUT ;
    USE SIGNAL ;
    ANTENNAPARTIALMETALAREA 7.2992 LAYER met2  ;
    ANTENNAPARTIALMETALSIDEAREA 36.099 LAYER met2  ;
    ANTENNAPARTIALCUTAREA 0.04 LAYER via2  ;
    ANTENNAPARTIALMETALAREA 10.612 LAYER met3  ;
    ANTENNAPARTIALMETALSIDEAREA 57.064 LAYER met3  ;
    ANTENNAPARTIALCUTAREA 0.04 LAYER via3  ;
    ANTENNAPARTIALMETALAREA 5.1786 LAYER met4  ;
    ANTENNAPARTIALMETALSIDEAREA 28.56 LAYER met4  ;
    ANTENNAMODEL OXIDE1 ;
    ANTENNAGATEAREA 0.213 LAYER met4  ;
    ANTENNAMAXAREACAR 69.5089 LAYER met4  ;
    ANTENNAMAXSIDEAREACAR 369.451 LAYER met4  ;
    ANTENNAMAXCUTCAR 0.616901 LAYER via4  ;
    PORT
      LAYER met2 ;
        RECT 1649.260000 3445.075000 1649.400000 3445.560000 ;
    END
  END la_data_in[35]
  PIN la_data_in[34]
    DIRECTION INPUT ;
    USE SIGNAL ;
    ANTENNAPARTIALMETALAREA 3.9532 LAYER met2  ;
    ANTENNAPARTIALMETALSIDEAREA 19.369 LAYER met2  ;
    ANTENNAPARTIALCUTAREA 0.04 LAYER via2  ;
    ANTENNAPARTIALMETALAREA 72.682 LAYER met3  ;
    ANTENNAPARTIALMETALSIDEAREA 388.104 LAYER met3  ;
    ANTENNAPARTIALCUTAREA 0.04 LAYER via3  ;
    ANTENNAPARTIALMETALAREA 0.6516 LAYER met4  ;
    ANTENNAPARTIALMETALSIDEAREA 4.416 LAYER met4  ;
    ANTENNAMODEL OXIDE1 ;
    ANTENNAGATEAREA 0.213 LAYER met4  ;
    ANTENNAMAXAREACAR 26.8793 LAYER met4  ;
    ANTENNAMAXSIDEAREACAR 143.667 LAYER met4  ;
    ANTENNAMAXCUTCAR 0.616901 LAYER via4  ;
    PORT
      LAYER met2 ;
        RECT 1666.740000 3445.075000 1666.880000 3445.560000 ;
    END
  END la_data_in[34]
  PIN la_data_in[33]
    DIRECTION INPUT ;
    USE SIGNAL ;
    ANTENNAPARTIALMETALAREA 8.6053 LAYER met2  ;
    ANTENNAPARTIALMETALSIDEAREA 42.6825 LAYER met2  ;
    ANTENNAMODEL OXIDE1 ;
    ANTENNAGATEAREA 0.1965 LAYER met2  ;
    ANTENNAMAXAREACAR 56.3471 LAYER met2  ;
    ANTENNAMAXSIDEAREACAR 274.682 LAYER met2  ;
    ANTENNAMAXCUTCAR 0.261578 LAYER via2  ;
    PORT
      LAYER met2 ;
        RECT 1684.220000 3445.075000 1684.360000 3445.560000 ;
    END
  END la_data_in[33]
  PIN la_data_in[32]
    DIRECTION INPUT ;
    USE SIGNAL ;
    ANTENNAPARTIALMETALAREA 7.63 LAYER met2  ;
    ANTENNAPARTIALMETALSIDEAREA 37.786 LAYER met2  ;
    ANTENNAMODEL OXIDE1 ;
    ANTENNAGATEAREA 0.315 LAYER met2  ;
    ANTENNAMAXAREACAR 28.139 LAYER met2  ;
    ANTENNAMAXSIDEAREACAR 134.903 LAYER met2  ;
    ANTENNAMAXCUTCAR 0.163175 LAYER via2  ;
    PORT
      LAYER met2 ;
        RECT 1701.700000 3445.075000 1701.840000 3445.560000 ;
    END
  END la_data_in[32]
  PIN la_data_in[31]
    DIRECTION INPUT ;
    USE SIGNAL ;
    ANTENNAPARTIALMETALAREA 9.0522 LAYER met2  ;
    ANTENNAPARTIALMETALSIDEAREA 44.982 LAYER met2  ;
    ANTENNAPARTIALCUTAREA 0.04 LAYER via2  ;
    ANTENNAPARTIALMETALAREA 78.43 LAYER met3  ;
    ANTENNAPARTIALMETALSIDEAREA 418.76 LAYER met3  ;
    ANTENNAPARTIALCUTAREA 0.04 LAYER via3  ;
    ANTENNAPARTIALMETALAREA 0.6516 LAYER met4  ;
    ANTENNAPARTIALMETALSIDEAREA 4.416 LAYER met4  ;
    ANTENNAMODEL OXIDE1 ;
    ANTENNAGATEAREA 0.315 LAYER met4  ;
    ANTENNAMAXAREACAR 7.81587 LAYER met4  ;
    ANTENNAMAXSIDEAREACAR 39.3111 LAYER met4  ;
    ANTENNAMAXCUTCAR 0.417143 LAYER via4  ;
    PORT
      LAYER met2 ;
        RECT 1719.640000 3445.075000 1719.780000 3445.560000 ;
    END
  END la_data_in[31]
  PIN la_data_in[30]
    DIRECTION INPUT ;
    USE SIGNAL ;
    ANTENNAPARTIALMETALAREA 0.3668 LAYER met2  ;
    ANTENNAPARTIALMETALSIDEAREA 1.673 LAYER met2  ;
    ANTENNAPARTIALCUTAREA 0.04 LAYER via2  ;
    ANTENNAPARTIALMETALAREA 89.248 LAYER met3  ;
    ANTENNAPARTIALMETALSIDEAREA 476.456 LAYER met3  ;
    ANTENNAPARTIALCUTAREA 0.04 LAYER via3  ;
    ANTENNAPARTIALMETALAREA 4.9152 LAYER met4  ;
    ANTENNAPARTIALMETALSIDEAREA 28.096 LAYER met4  ;
    ANTENNAMODEL OXIDE1 ;
    ANTENNAGATEAREA 0.315 LAYER met4  ;
    ANTENNAMAXAREACAR 29.4552 LAYER met4  ;
    ANTENNAMAXSIDEAREACAR 158.232 LAYER met4  ;
    ANTENNAMAXCUTCAR 0.417143 LAYER via4  ;
    PORT
      LAYER met2 ;
        RECT 1737.120000 3445.075000 1737.260000 3445.560000 ;
    END
  END la_data_in[30]
  PIN la_data_in[29]
    DIRECTION INPUT ;
    USE SIGNAL ;
    ANTENNAPARTIALMETALAREA 0.2346 LAYER met2  ;
    ANTENNAPARTIALMETALSIDEAREA 0.987 LAYER met2  ;
    ANTENNAPARTIALCUTAREA 0.04 LAYER via2  ;
    ANTENNAPARTIALMETALAREA 156.57 LAYER met3  ;
    ANTENNAPARTIALMETALSIDEAREA 835.976 LAYER met3  ;
    ANTENNAPARTIALCUTAREA 0.04 LAYER via3  ;
    ANTENNAPARTIALMETALAREA 4.9728 LAYER met4  ;
    ANTENNAPARTIALMETALSIDEAREA 26.992 LAYER met4  ;
    ANTENNAMODEL OXIDE1 ;
    ANTENNAGATEAREA 0.495 LAYER met4  ;
    ANTENNAMAXAREACAR 23.6446 LAYER met4  ;
    ANTENNAMAXSIDEAREACAR 126.44 LAYER met4  ;
    ANTENNAMAXCUTCAR 0.265455 LAYER via4  ;
    PORT
      LAYER met2 ;
        RECT 1754.600000 3445.075000 1754.740000 3445.560000 ;
    END
  END la_data_in[29]
  PIN la_data_in[28]
    DIRECTION INPUT ;
    USE SIGNAL ;
    ANTENNAPARTIALMETALAREA 5.3996 LAYER met2  ;
    ANTENNAPARTIALMETALSIDEAREA 26.719 LAYER met2  ;
    ANTENNAPARTIALCUTAREA 0.04 LAYER via2  ;
    ANTENNAPARTIALMETALAREA 180.648 LAYER met3  ;
    ANTENNAPARTIALMETALSIDEAREA 964.392 LAYER met3  ;
    ANTENNAPARTIALCUTAREA 0.04 LAYER via3  ;
    ANTENNAPARTIALMETALAREA 0.6516 LAYER met4  ;
    ANTENNAPARTIALMETALSIDEAREA 4.416 LAYER met4  ;
    ANTENNAMODEL OXIDE1 ;
    ANTENNAGATEAREA 0.495 LAYER met4  ;
    ANTENNAMAXAREACAR 15.579 LAYER met4  ;
    ANTENNAMAXSIDEAREACAR 80.6242 LAYER met4  ;
    ANTENNAMAXCUTCAR 0.265455 LAYER via4  ;
    PORT
      LAYER met2 ;
        RECT 1772.080000 3445.075000 1772.220000 3445.560000 ;
    END
  END la_data_in[28]
  PIN la_data_in[27]
    DIRECTION INPUT ;
    USE SIGNAL ;
    ANTENNAPARTIALMETALAREA 1.0204 LAYER met2  ;
    ANTENNAPARTIALMETALSIDEAREA 4.823 LAYER met2  ;
    ANTENNAPARTIALCUTAREA 0.04 LAYER via2  ;
    ANTENNAPARTIALMETALAREA 57.232 LAYER met3  ;
    ANTENNAPARTIALMETALSIDEAREA 305.704 LAYER met3  ;
    ANTENNAPARTIALCUTAREA 0.04 LAYER via3  ;
    ANTENNAPARTIALMETALAREA 1.5828 LAYER met4  ;
    ANTENNAPARTIALMETALSIDEAREA 8.912 LAYER met4  ;
    ANTENNAMODEL OXIDE1 ;
    ANTENNAGATEAREA 0.576 LAYER met4  ;
    ANTENNAMAXAREACAR 10.4494 LAYER met4  ;
    ANTENNAMAXSIDEAREACAR 52.3446 LAYER met4  ;
    ANTENNAMAXCUTCAR 0.228125 LAYER via4  ;
    PORT
      LAYER met2 ;
        RECT 1790.020000 3445.075000 1790.160000 3445.560000 ;
    END
  END la_data_in[27]
  PIN la_data_in[26]
    DIRECTION INPUT ;
    USE SIGNAL ;
    ANTENNAPARTIALMETALAREA 10.1708 LAYER met2  ;
    ANTENNAPARTIALMETALSIDEAREA 50.372 LAYER met2  ;
    ANTENNAMODEL OXIDE1 ;
    ANTENNAGATEAREA 1.152 LAYER met2  ;
    ANTENNAMAXAREACAR 11.1847 LAYER met2  ;
    ANTENNAMAXSIDEAREACAR 53.6983 LAYER met2  ;
    ANTENNAMAXCUTCAR 0.0446181 LAYER via2  ;
    PORT
      LAYER met2 ;
        RECT 1807.500000 3445.075000 1807.640000 3445.560000 ;
    END
  END la_data_in[26]
  PIN la_data_in[25]
    DIRECTION INPUT ;
    USE SIGNAL ;
    ANTENNAPARTIALMETALAREA 3.9904 LAYER met2  ;
    ANTENNAPARTIALMETALSIDEAREA 19.824 LAYER met2  ;
    ANTENNAMODEL OXIDE1 ;
    ANTENNAGATEAREA 1.152 LAYER met2  ;
    ANTENNAMAXAREACAR 14.876 LAYER met2  ;
    ANTENNAMAXSIDEAREACAR 72.4622 LAYER met2  ;
    ANTENNAMAXCUTCAR 0.0446181 LAYER via2  ;
    PORT
      LAYER met2 ;
        RECT 1824.980000 3445.075000 1825.120000 3445.560000 ;
    END
  END la_data_in[25]
  PIN la_data_in[24]
    DIRECTION INPUT ;
    USE SIGNAL ;
    ANTENNAPARTIALMETALAREA 1.5226 LAYER met2  ;
    ANTENNAPARTIALMETALSIDEAREA 7.259 LAYER met2  ;
    ANTENNAPARTIALCUTAREA 0.04 LAYER via2  ;
    ANTENNAPARTIALMETALAREA 0.745 LAYER met3  ;
    ANTENNAPARTIALMETALSIDEAREA 4.44 LAYER met3  ;
    ANTENNAPARTIALCUTAREA 0.04 LAYER via3  ;
    ANTENNAPARTIALMETALAREA 1.8684 LAYER met4  ;
    ANTENNAPARTIALMETALSIDEAREA 11.376 LAYER met4  ;
    ANTENNAMODEL OXIDE1 ;
    ANTENNAGATEAREA 1.152 LAYER met4  ;
    ANTENNAMAXAREACAR 6.48635 LAYER met4  ;
    ANTENNAMAXSIDEAREACAR 33.0825 LAYER met4  ;
    ANTENNAMAXCUTCAR 0.114063 LAYER via4  ;
    PORT
      LAYER met2 ;
        RECT 1842.920000 3445.075000 1843.060000 3445.560000 ;
    END
  END la_data_in[24]
  PIN la_data_in[23]
    DIRECTION INPUT ;
    USE SIGNAL ;
    ANTENNAPARTIALMETALAREA 1.5566 LAYER met2  ;
    ANTENNAPARTIALMETALSIDEAREA 7.504 LAYER met2  ;
    ANTENNAPARTIALCUTAREA 0.04 LAYER via2  ;
    ANTENNAPARTIALMETALAREA 101.251 LAYER met3  ;
    ANTENNAPARTIALMETALSIDEAREA 540.472 LAYER met3  ;
    ANTENNAPARTIALCUTAREA 0.04 LAYER via3  ;
    ANTENNAPARTIALMETALAREA 0.6516 LAYER met4  ;
    ANTENNAPARTIALMETALSIDEAREA 4.416 LAYER met4  ;
    ANTENNAMODEL OXIDE1 ;
    ANTENNAGATEAREA 1.152 LAYER met4  ;
    ANTENNAMAXAREACAR 8.09694 LAYER met4  ;
    ANTENNAMAXSIDEAREACAR 40.3108 LAYER met4  ;
    ANTENNAMAXCUTCAR 0.114063 LAYER via4  ;
    PORT
      LAYER met2 ;
        RECT 1860.400000 3445.075000 1860.540000 3445.560000 ;
    END
  END la_data_in[23]
  PIN la_data_in[22]
    DIRECTION INPUT ;
    USE SIGNAL ;
    ANTENNAPARTIALMETALAREA 0.1386 LAYER met2  ;
    ANTENNAPARTIALMETALSIDEAREA 0.532 LAYER met2  ;
    ANTENNAPARTIALCUTAREA 0.04 LAYER via2  ;
    ANTENNAPARTIALMETALAREA 287.818 LAYER met3  ;
    ANTENNAPARTIALMETALSIDEAREA 1535.5 LAYER met3  ;
    ANTENNAPARTIALCUTAREA 0.04 LAYER via3  ;
    ANTENNAPARTIALMETALAREA 0.6516 LAYER met4  ;
    ANTENNAPARTIALMETALSIDEAREA 4.416 LAYER met4  ;
    ANTENNAMODEL OXIDE1 ;
    ANTENNAGATEAREA 1.152 LAYER met4  ;
    ANTENNAMAXAREACAR 8.57463 LAYER met4  ;
    ANTENNAMAXSIDEAREACAR 42.9019 LAYER met4  ;
    ANTENNAMAXCUTCAR 0.114063 LAYER via4  ;
    PORT
      LAYER met2 ;
        RECT 1877.880000 3445.075000 1878.020000 3445.560000 ;
    END
  END la_data_in[22]
  PIN la_data_in[21]
    DIRECTION INPUT ;
    USE SIGNAL ;
    ANTENNAPARTIALMETALAREA 5.4782 LAYER met2  ;
    ANTENNAPARTIALMETALSIDEAREA 27.027 LAYER met2  ;
    ANTENNAMODEL OXIDE1 ;
    ANTENNAGATEAREA 0.315 LAYER met2  ;
    ANTENNAMAXAREACAR 19.8863 LAYER met2  ;
    ANTENNAMAXSIDEAREACAR 95.1667 LAYER met2  ;
    ANTENNAMAXCUTCAR 0.163175 LAYER via2  ;
    PORT
      LAYER met2 ;
        RECT 1895.360000 3445.075000 1895.500000 3445.560000 ;
    END
  END la_data_in[21]
  PIN la_data_in[20]
    DIRECTION INPUT ;
    USE SIGNAL ;
    ANTENNAPARTIALMETALAREA 6.5994 LAYER met2  ;
    ANTENNAPARTIALMETALSIDEAREA 32.718 LAYER met2  ;
    ANTENNAPARTIALCUTAREA 0.04 LAYER via2  ;
    ANTENNAPARTIALMETALAREA 6.679 LAYER met3  ;
    ANTENNAPARTIALMETALSIDEAREA 36.088 LAYER met3  ;
    ANTENNAPARTIALCUTAREA 0.04 LAYER via3  ;
    ANTENNAPARTIALMETALAREA 5.1786 LAYER met4  ;
    ANTENNAPARTIALMETALSIDEAREA 28.56 LAYER met4  ;
    ANTENNAMODEL OXIDE1 ;
    ANTENNAGATEAREA 0.213 LAYER met4  ;
    ANTENNAMAXAREACAR 29.5277 LAYER met4  ;
    ANTENNAMAXSIDEAREACAR 156.549 LAYER met4  ;
    ANTENNAMAXCUTCAR 0.616901 LAYER via4  ;
    PORT
      LAYER met2 ;
        RECT 1913.300000 3445.075000 1913.440000 3445.560000 ;
    END
  END la_data_in[20]
  PIN la_data_in[19]
    DIRECTION INPUT ;
    USE SIGNAL ;
    ANTENNAPARTIALMETALAREA 11.3206 LAYER met2  ;
    ANTENNAPARTIALMETALSIDEAREA 56.357 LAYER met2  ;
    ANTENNAMODEL OXIDE1 ;
    ANTENNAGATEAREA 0.213 LAYER met2  ;
    ANTENNAMAXAREACAR 54.6563 LAYER met2  ;
    ANTENNAMAXSIDEAREACAR 268.261 LAYER met2  ;
    ANTENNAMAXCUTCAR 0.241315 LAYER via2  ;
    PORT
      LAYER met2 ;
        RECT 1930.780000 3445.075000 1930.920000 3445.560000 ;
    END
  END la_data_in[19]
  PIN la_data_in[18]
    DIRECTION INPUT ;
    USE SIGNAL ;
    ANTENNAPARTIALMETALAREA 0.4088 LAYER met2  ;
    ANTENNAPARTIALMETALSIDEAREA 1.883 LAYER met2  ;
    ANTENNAPARTIALCUTAREA 0.04 LAYER via2  ;
    ANTENNAPARTIALMETALAREA 101.482 LAYER met3  ;
    ANTENNAPARTIALMETALSIDEAREA 541.704 LAYER met3  ;
    ANTENNAPARTIALCUTAREA 0.04 LAYER via3  ;
    ANTENNAPARTIALMETALAREA 12.4824 LAYER met4  ;
    ANTENNAPARTIALMETALSIDEAREA 67.984 LAYER met4  ;
    ANTENNAMODEL OXIDE1 ;
    ANTENNAGATEAREA 0.213 LAYER met4  ;
    ANTENNAMAXAREACAR 78.4836 LAYER met4  ;
    ANTENNAMAXSIDEAREACAR 417.92 LAYER met4  ;
    ANTENNAMAXCUTCAR 0.616901 LAYER via4  ;
    PORT
      LAYER met2 ;
        RECT 1948.260000 3445.075000 1948.400000 3445.560000 ;
    END
  END la_data_in[18]
  PIN la_data_in[17]
    DIRECTION INPUT ;
    USE SIGNAL ;
    ANTENNAPARTIALMETALAREA 6.5225 LAYER met2  ;
    ANTENNAPARTIALMETALSIDEAREA 32.144 LAYER met2  ;
    ANTENNAPARTIALCUTAREA 0.04 LAYER via2  ;
    ANTENNAPARTIALMETALAREA 93.595 LAYER met3  ;
    ANTENNAPARTIALMETALSIDEAREA 499.64 LAYER met3  ;
    ANTENNAPARTIALCUTAREA 0.04 LAYER via3  ;
    ANTENNAPARTIALMETALAREA 0.6516 LAYER met4  ;
    ANTENNAPARTIALMETALSIDEAREA 4.416 LAYER met4  ;
    ANTENNAMODEL OXIDE1 ;
    ANTENNAGATEAREA 0.1965 LAYER met4  ;
    ANTENNAMAXAREACAR 21.5532 LAYER met4  ;
    ANTENNAMAXSIDEAREACAR 110.514 LAYER met4  ;
    ANTENNAMAXCUTCAR 0.668702 LAYER via4  ;
    PORT
      LAYER met2 ;
        RECT 1965.740000 3445.075000 1965.880000 3445.560000 ;
    END
  END la_data_in[17]
  PIN la_data_in[16]
    DIRECTION INPUT ;
    USE SIGNAL ;
    ANTENNAPARTIALMETALAREA 2.631 LAYER met2  ;
    ANTENNAPARTIALMETALSIDEAREA 13.027 LAYER met2  ;
    ANTENNAMODEL OXIDE1 ;
    ANTENNAGATEAREA 0.159 LAYER met2  ;
    ANTENNAMAXAREACAR 34.7871 LAYER met2  ;
    ANTENNAMAXSIDEAREACAR 165.009 LAYER met2  ;
    ANTENNAMAXCUTCAR 0.32327 LAYER via2  ;
    PORT
      LAYER met2 ;
        RECT 1983.680000 3445.075000 1983.820000 3445.560000 ;
    END
  END la_data_in[16]
  PIN la_data_in[15]
    DIRECTION INPUT ;
    USE SIGNAL ;
    ANTENNAPARTIALMETALAREA 8.2742 LAYER met2  ;
    ANTENNAPARTIALMETALSIDEAREA 41.125 LAYER met2  ;
    ANTENNAMODEL OXIDE1 ;
    ANTENNAGATEAREA 1.152 LAYER met2  ;
    ANTENNAMAXAREACAR 7.76404 LAYER met2  ;
    ANTENNAMAXSIDEAREACAR 36.7999 LAYER met2  ;
    ANTENNAMAXCUTCAR 0.0446181 LAYER via2  ;
    PORT
      LAYER met2 ;
        RECT 2001.160000 3445.075000 2001.300000 3445.560000 ;
    END
  END la_data_in[15]
  PIN la_data_in[14]
    DIRECTION INPUT ;
    USE SIGNAL ;
    ANTENNAPARTIALMETALAREA 8.3006 LAYER met2  ;
    ANTENNAPARTIALMETALSIDEAREA 41.139 LAYER met2  ;
    ANTENNAMODEL OXIDE1 ;
    ANTENNAGATEAREA 1.152 LAYER met2  ;
    ANTENNAMAXAREACAR 7.74364 LAYER met2  ;
    ANTENNAMAXSIDEAREACAR 36.6541 LAYER met2  ;
    ANTENNAMAXCUTCAR 0.0446181 LAYER via2  ;
    PORT
      LAYER met2 ;
        RECT 2018.640000 3445.075000 2018.780000 3445.560000 ;
    END
  END la_data_in[14]
  PIN la_data_in[13]
    DIRECTION INPUT ;
    USE SIGNAL ;
    ANTENNAPARTIALMETALAREA 7.556 LAYER met2  ;
    ANTENNAPARTIALMETALSIDEAREA 37.534 LAYER met2  ;
    ANTENNAMODEL OXIDE1 ;
    ANTENNAGATEAREA 1.152 LAYER met2  ;
    ANTENNAMAXAREACAR 7.19651 LAYER met2  ;
    ANTENNAMAXSIDEAREACAR 33.9622 LAYER met2  ;
    ANTENNAMAXCUTCAR 0.0446181 LAYER via2  ;
    PORT
      LAYER met2 ;
        RECT 2036.580000 3445.075000 2036.720000 3445.560000 ;
    END
  END la_data_in[13]
  PIN la_data_in[12]
    DIRECTION INPUT ;
    USE SIGNAL ;
    ANTENNAPARTIALMETALAREA 9.3826 LAYER met2  ;
    ANTENNAPARTIALMETALSIDEAREA 46.634 LAYER met2  ;
    ANTENNAPARTIALCUTAREA 0.04 LAYER via2  ;
    ANTENNAPARTIALMETALAREA 22.2298 LAYER met3  ;
    ANTENNAPARTIALMETALSIDEAREA 119.496 LAYER met3  ;
    ANTENNAPARTIALCUTAREA 0.04 LAYER via3  ;
    ANTENNAPARTIALMETALAREA 0.6516 LAYER met4  ;
    ANTENNAPARTIALMETALSIDEAREA 4.416 LAYER met4  ;
    ANTENNAMODEL OXIDE1 ;
    ANTENNAGATEAREA 0.1965 LAYER met4  ;
    ANTENNAMAXAREACAR 22.798 LAYER met4  ;
    ANTENNAMAXSIDEAREACAR 115.17 LAYER met4  ;
    ANTENNAMAXCUTCAR 0.668702 LAYER via4  ;
    PORT
      LAYER met2 ;
        RECT 2054.060000 3445.075000 2054.200000 3445.560000 ;
    END
  END la_data_in[12]
  PIN la_data_in[11]
    DIRECTION INPUT ;
    USE SIGNAL ;
    ANTENNAPARTIALMETALAREA 8.2779 LAYER met2  ;
    ANTENNAPARTIALMETALSIDEAREA 41.1635 LAYER met2  ;
    ANTENNAMODEL OXIDE1 ;
    ANTENNAGATEAREA 0.1965 LAYER met2  ;
    ANTENNAMAXAREACAR 44.8672 LAYER met2  ;
    ANTENNAMAXSIDEAREACAR 215.634 LAYER met2  ;
    ANTENNAMAXCUTCAR 0.261578 LAYER via2  ;
    PORT
      LAYER met2 ;
        RECT 2071.540000 3445.075000 2071.680000 3445.560000 ;
    END
  END la_data_in[11]
  PIN la_data_in[10]
    DIRECTION INPUT ;
    USE SIGNAL ;
    ANTENNAPARTIALMETALAREA 9.4856 LAYER met2  ;
    ANTENNAPARTIALMETALSIDEAREA 47.418 LAYER met2  ;
    ANTENNAMODEL OXIDE1 ;
    ANTENNAGATEAREA 1.152 LAYER met2  ;
    ANTENNAMAXAREACAR 57.7354 LAYER met2  ;
    ANTENNAMAXSIDEAREACAR 286.862 LAYER met2  ;
    ANTENNAMAXCUTCAR 0.0446181 LAYER via2  ;
    PORT
      LAYER met2 ;
        RECT 2089.020000 3445.075000 2089.160000 3445.560000 ;
    END
  END la_data_in[10]
  PIN la_data_in[9]
    DIRECTION INPUT ;
    USE SIGNAL ;
    ANTENNAPARTIALMETALAREA 2.1004 LAYER met2  ;
    ANTENNAPARTIALMETALSIDEAREA 10.374 LAYER met2  ;
    ANTENNAMODEL OXIDE1 ;
    ANTENNAGATEAREA 1.152 LAYER met2  ;
    ANTENNAMAXAREACAR 32.116 LAYER met2  ;
    ANTENNAMAXSIDEAREACAR 158.662 LAYER met2  ;
    ANTENNAMAXCUTCAR 0.0446181 LAYER via2  ;
    PORT
      LAYER met2 ;
        RECT 2106.960000 3445.075000 2107.100000 3445.560000 ;
    END
  END la_data_in[9]
  PIN la_data_in[8]
    DIRECTION INPUT ;
    USE SIGNAL ;
    ANTENNAPARTIALMETALAREA 2.6716 LAYER met2  ;
    ANTENNAPARTIALMETALSIDEAREA 13.23 LAYER met2  ;
    ANTENNAMODEL OXIDE1 ;
    ANTENNAGATEAREA 0.495 LAYER met2  ;
    ANTENNAMAXAREACAR 28.1586 LAYER met2  ;
    ANTENNAMAXSIDEAREACAR 138.781 LAYER met2  ;
    ANTENNAMAXCUTCAR 0.103838 LAYER via2  ;
    PORT
      LAYER met2 ;
        RECT 2124.440000 3445.075000 2124.580000 3445.560000 ;
    END
  END la_data_in[8]
  PIN la_data_in[7]
    DIRECTION INPUT ;
    USE SIGNAL ;
    ANTENNAPARTIALMETALAREA 10.4886 LAYER met2  ;
    ANTENNAPARTIALMETALSIDEAREA 52.164 LAYER met2  ;
    ANTENNAPARTIALCUTAREA 0.04 LAYER via2  ;
    ANTENNAPARTIALMETALAREA 13.0908 LAYER met3  ;
    ANTENNAPARTIALMETALSIDEAREA 70.288 LAYER met3  ;
    ANTENNAMODEL OXIDE1 ;
    ANTENNAGATEAREA 0.1965 LAYER met3  ;
    ANTENNAMAXAREACAR 84.8519 LAYER met3  ;
    ANTENNAMAXSIDEAREACAR 440.361 LAYER met3  ;
    ANTENNAMAXCUTCAR 0.46514 LAYER via3  ;
    PORT
      LAYER met2 ;
        RECT 2141.920000 3445.075000 2142.060000 3445.560000 ;
    END
  END la_data_in[7]
  PIN la_data_in[6]
    DIRECTION INPUT ;
    USE SIGNAL ;
    ANTENNAPARTIALMETALAREA 10.6208 LAYER met2  ;
    ANTENNAPARTIALMETALSIDEAREA 52.976 LAYER met2  ;
    ANTENNAMODEL OXIDE1 ;
    ANTENNAGATEAREA 0.495 LAYER met2  ;
    ANTENNAMAXAREACAR 22.464 LAYER met2  ;
    ANTENNAMAXSIDEAREACAR 109.415 LAYER met2  ;
    ANTENNAMAXCUTCAR 0.103838 LAYER via2  ;
    PORT
      LAYER met2 ;
        RECT 2159.400000 3445.075000 2159.540000 3445.560000 ;
    END
  END la_data_in[6]
  PIN la_data_in[5]
    DIRECTION INPUT ;
    USE SIGNAL ;
    ANTENNAPARTIALMETALAREA 10.6684 LAYER met2  ;
    ANTENNAPARTIALMETALSIDEAREA 53.214 LAYER met2  ;
    ANTENNAMODEL OXIDE1 ;
    ANTENNAGATEAREA 0.495 LAYER met2  ;
    ANTENNAMAXAREACAR 21.9648 LAYER met2  ;
    ANTENNAMAXSIDEAREACAR 108.946 LAYER met2  ;
    ANTENNAMAXCUTCAR 0.103838 LAYER via2  ;
    PORT
      LAYER met2 ;
        RECT 2177.340000 3445.075000 2177.480000 3445.560000 ;
    END
  END la_data_in[5]
  PIN la_data_in[4]
    DIRECTION INPUT ;
    USE SIGNAL ;
    ANTENNAPARTIALMETALAREA 11.4928 LAYER met2  ;
    ANTENNAPARTIALMETALSIDEAREA 57.218 LAYER met2  ;
    ANTENNAMODEL OXIDE1 ;
    ANTENNAGATEAREA 0.495 LAYER met2  ;
    ANTENNAMAXAREACAR 24.3816 LAYER met2  ;
    ANTENNAMAXSIDEAREACAR 120.656 LAYER met2  ;
    ANTENNAMAXCUTCAR 0.103838 LAYER via2  ;
    PORT
      LAYER met2 ;
        RECT 2194.820000 3445.075000 2194.960000 3445.560000 ;
    END
  END la_data_in[4]
  PIN la_data_in[3]
    DIRECTION INPUT ;
    USE SIGNAL ;
    ANTENNAPARTIALMETALAREA 10.3812 LAYER met2  ;
    ANTENNAPARTIALMETALSIDEAREA 51.66 LAYER met2  ;
    ANTENNAMODEL OXIDE1 ;
    ANTENNAGATEAREA 0.315 LAYER met2  ;
    ANTENNAMAXAREACAR 34.0663 LAYER met2  ;
    ANTENNAMAXSIDEAREACAR 166.656 LAYER met2  ;
    ANTENNAMAXCUTCAR 0.163175 LAYER via2  ;
    PORT
      LAYER met2 ;
        RECT 2212.300000 3445.075000 2212.440000 3445.560000 ;
    END
  END la_data_in[3]
  PIN la_data_in[2]
    DIRECTION INPUT ;
    USE SIGNAL ;
    ANTENNAPARTIALMETALAREA 10.2998 LAYER met2  ;
    ANTENNAPARTIALMETALSIDEAREA 51.135 LAYER met2  ;
    ANTENNAMODEL OXIDE1 ;
    ANTENNAGATEAREA 0.315 LAYER met2  ;
    ANTENNAMAXAREACAR 33.8079 LAYER met2  ;
    ANTENNAMAXSIDEAREACAR 164.989 LAYER met2  ;
    ANTENNAMAXCUTCAR 0.163175 LAYER via2  ;
    PORT
      LAYER met2 ;
        RECT 2230.240000 3445.075000 2230.380000 3445.560000 ;
    END
  END la_data_in[2]
  PIN la_data_in[1]
    DIRECTION INPUT ;
    USE SIGNAL ;
    ANTENNAPARTIALMETALAREA 10.716 LAYER met2  ;
    ANTENNAPARTIALMETALSIDEAREA 53.452 LAYER met2  ;
    ANTENNAMODEL OXIDE1 ;
    ANTENNAGATEAREA 0.495 LAYER met2  ;
    ANTENNAMAXAREACAR 71.4455 LAYER met2  ;
    ANTENNAMAXSIDEAREACAR 355.215 LAYER met2  ;
    ANTENNAMAXCUTCAR 0.103838 LAYER via2  ;
    PORT
      LAYER met2 ;
        RECT 2247.720000 3445.075000 2247.860000 3445.560000 ;
    END
  END la_data_in[1]
  PIN la_data_in[0]
    DIRECTION INPUT ;
    USE SIGNAL ;
    ANTENNAPARTIALMETALAREA 3.5814 LAYER met2  ;
    ANTENNAPARTIALMETALSIDEAREA 17.661 LAYER met2  ;
    ANTENNAMODEL OXIDE1 ;
    ANTENNAGATEAREA 0.213 LAYER met2  ;
    ANTENNAMAXAREACAR 20.6728 LAYER met2  ;
    ANTENNAMAXSIDEAREACAR 98.0258 LAYER met2  ;
    ANTENNAMAXCUTCAR 0.241315 LAYER via2  ;
    PORT
      LAYER met2 ;
        RECT 2265.200000 3445.075000 2265.340000 3445.560000 ;
    END
  END la_data_in[0]
  PIN la_data_out[127]
    DIRECTION OUTPUT ;
    USE SIGNAL ;
    ANTENNAPARTIALMETALAREA 1.7303 LAYER met2  ;
    ANTENNAPARTIALMETALSIDEAREA 8.5435 LAYER met2  ;
    PORT
      LAYER met2 ;
        RECT 23.620000 3445.075000 23.760000 3445.560000 ;
    END
  END la_data_out[127]
  PIN la_data_out[126]
    DIRECTION OUTPUT ;
    USE SIGNAL ;
    ANTENNAPARTIALMETALAREA 1.7303 LAYER met2  ;
    ANTENNAPARTIALMETALSIDEAREA 8.5435 LAYER met2  ;
    PORT
      LAYER met2 ;
        RECT 41.100000 3445.075000 41.240000 3445.560000 ;
    END
  END la_data_out[126]
  PIN la_data_out[125]
    DIRECTION OUTPUT ;
    USE SIGNAL ;
    ANTENNAPARTIALMETALAREA 1.7303 LAYER met2  ;
    ANTENNAPARTIALMETALSIDEAREA 8.5435 LAYER met2  ;
    PORT
      LAYER met2 ;
        RECT 58.580000 3445.075000 58.720000 3445.560000 ;
    END
  END la_data_out[125]
  PIN la_data_out[124]
    DIRECTION OUTPUT ;
    USE SIGNAL ;
    ANTENNAPARTIALMETALAREA 1.8731 LAYER met2  ;
    ANTENNAPARTIALMETALSIDEAREA 9.2575 LAYER met2  ;
    PORT
      LAYER met2 ;
        RECT 76.060000 3445.075000 76.200000 3445.560000 ;
    END
  END la_data_out[124]
  PIN la_data_out[123]
    DIRECTION OUTPUT ;
    USE SIGNAL ;
    ANTENNAPARTIALMETALAREA 1.8731 LAYER met2  ;
    ANTENNAPARTIALMETALSIDEAREA 9.2575 LAYER met2  ;
    PORT
      LAYER met2 ;
        RECT 94.000000 3445.075000 94.140000 3445.560000 ;
    END
  END la_data_out[123]
  PIN la_data_out[122]
    DIRECTION OUTPUT ;
    USE SIGNAL ;
    ANTENNAPARTIALMETALAREA 1.8731 LAYER met2  ;
    ANTENNAPARTIALMETALSIDEAREA 9.2575 LAYER met2  ;
    PORT
      LAYER met2 ;
        RECT 111.480000 3445.075000 111.620000 3445.560000 ;
    END
  END la_data_out[122]
  PIN la_data_out[121]
    DIRECTION OUTPUT ;
    USE SIGNAL ;
    ANTENNAPARTIALMETALAREA 1.7303 LAYER met2  ;
    ANTENNAPARTIALMETALSIDEAREA 8.5435 LAYER met2  ;
    PORT
      LAYER met2 ;
        RECT 128.960000 3445.075000 129.100000 3445.560000 ;
    END
  END la_data_out[121]
  PIN la_data_out[120]
    DIRECTION OUTPUT ;
    USE SIGNAL ;
    ANTENNAPARTIALMETALAREA 1.8731 LAYER met2  ;
    ANTENNAPARTIALMETALSIDEAREA 9.2575 LAYER met2  ;
    PORT
      LAYER met2 ;
        RECT 146.440000 3445.075000 146.580000 3445.560000 ;
    END
  END la_data_out[120]
  PIN la_data_out[119]
    DIRECTION OUTPUT ;
    USE SIGNAL ;
    ANTENNAPARTIALMETALAREA 1.8731 LAYER met2  ;
    ANTENNAPARTIALMETALSIDEAREA 9.2575 LAYER met2  ;
    PORT
      LAYER met2 ;
        RECT 164.380000 3445.075000 164.520000 3445.560000 ;
    END
  END la_data_out[119]
  PIN la_data_out[118]
    DIRECTION OUTPUT ;
    USE SIGNAL ;
    ANTENNAPARTIALMETALAREA 1.8731 LAYER met2  ;
    ANTENNAPARTIALMETALSIDEAREA 9.2575 LAYER met2  ;
    PORT
      LAYER met2 ;
        RECT 181.860000 3445.075000 182.000000 3445.560000 ;
    END
  END la_data_out[118]
  PIN la_data_out[117]
    DIRECTION OUTPUT ;
    USE SIGNAL ;
    ANTENNAPARTIALMETALAREA 1.8731 LAYER met2  ;
    ANTENNAPARTIALMETALSIDEAREA 9.2575 LAYER met2  ;
    PORT
      LAYER met2 ;
        RECT 199.340000 3445.075000 199.480000 3445.560000 ;
    END
  END la_data_out[117]
  PIN la_data_out[116]
    DIRECTION OUTPUT ;
    USE SIGNAL ;
    ANTENNAPARTIALMETALAREA 1.8731 LAYER met2  ;
    ANTENNAPARTIALMETALSIDEAREA 9.2575 LAYER met2  ;
    PORT
      LAYER met2 ;
        RECT 217.280000 3445.075000 217.420000 3445.560000 ;
    END
  END la_data_out[116]
  PIN la_data_out[115]
    DIRECTION OUTPUT ;
    USE SIGNAL ;
    ANTENNAPARTIALMETALAREA 1.8731 LAYER met2  ;
    ANTENNAPARTIALMETALSIDEAREA 9.2575 LAYER met2  ;
    PORT
      LAYER met2 ;
        RECT 234.760000 3445.075000 234.900000 3445.560000 ;
    END
  END la_data_out[115]
  PIN la_data_out[114]
    DIRECTION OUTPUT ;
    USE SIGNAL ;
    ANTENNAPARTIALMETALAREA 1.8731 LAYER met2  ;
    ANTENNAPARTIALMETALSIDEAREA 9.2575 LAYER met2  ;
    PORT
      LAYER met2 ;
        RECT 252.240000 3445.075000 252.380000 3445.560000 ;
    END
  END la_data_out[114]
  PIN la_data_out[113]
    DIRECTION OUTPUT ;
    USE SIGNAL ;
    ANTENNAPARTIALMETALAREA 1.9375 LAYER met2  ;
    ANTENNAPARTIALMETALSIDEAREA 9.5795 LAYER met2  ;
    PORT
      LAYER met2 ;
        RECT 269.720000 3445.075000 269.860000 3445.560000 ;
    END
  END la_data_out[113]
  PIN la_data_out[112]
    DIRECTION OUTPUT ;
    USE SIGNAL ;
    ANTENNAPARTIALMETALAREA 1.8731 LAYER met2  ;
    ANTENNAPARTIALMETALSIDEAREA 9.2575 LAYER met2  ;
    PORT
      LAYER met2 ;
        RECT 287.660000 3445.075000 287.800000 3445.560000 ;
    END
  END la_data_out[112]
  PIN la_data_out[111]
    DIRECTION OUTPUT ;
    USE SIGNAL ;
    ANTENNAPARTIALMETALAREA 1.8731 LAYER met2  ;
    ANTENNAPARTIALMETALSIDEAREA 9.2575 LAYER met2  ;
    PORT
      LAYER met2 ;
        RECT 305.140000 3445.075000 305.280000 3445.560000 ;
    END
  END la_data_out[111]
  PIN la_data_out[110]
    DIRECTION OUTPUT ;
    USE SIGNAL ;
    ANTENNAPARTIALMETALAREA 2.2665 LAYER met2  ;
    ANTENNAPARTIALMETALSIDEAREA 11.2245 LAYER met2  ;
    PORT
      LAYER met2 ;
        RECT 322.620000 3445.075000 322.760000 3445.560000 ;
    END
  END la_data_out[110]
  PIN la_data_out[109]
    DIRECTION OUTPUT ;
    USE SIGNAL ;
    ANTENNAPARTIALMETALAREA 1.8731 LAYER met2  ;
    ANTENNAPARTIALMETALSIDEAREA 9.2575 LAYER met2  ;
    PORT
      LAYER met2 ;
        RECT 340.100000 3445.075000 340.240000 3445.560000 ;
    END
  END la_data_out[109]
  PIN la_data_out[108]
    DIRECTION OUTPUT ;
    USE SIGNAL ;
    ANTENNAPARTIALMETALAREA 1.8731 LAYER met2  ;
    ANTENNAPARTIALMETALSIDEAREA 9.2575 LAYER met2  ;
    PORT
      LAYER met2 ;
        RECT 358.040000 3445.075000 358.180000 3445.560000 ;
    END
  END la_data_out[108]
  PIN la_data_out[107]
    DIRECTION OUTPUT ;
    USE SIGNAL ;
    ANTENNAPARTIALMETALAREA 1.7947 LAYER met2  ;
    ANTENNAPARTIALMETALSIDEAREA 8.8655 LAYER met2  ;
    PORT
      LAYER met2 ;
        RECT 375.520000 3445.075000 375.660000 3445.560000 ;
    END
  END la_data_out[107]
  PIN la_data_out[106]
    DIRECTION OUTPUT ;
    USE SIGNAL ;
    ANTENNAPARTIALMETALAREA 1.7303 LAYER met2  ;
    ANTENNAPARTIALMETALSIDEAREA 8.5435 LAYER met2  ;
    PORT
      LAYER met2 ;
        RECT 393.000000 3445.075000 393.140000 3445.560000 ;
    END
  END la_data_out[106]
  PIN la_data_out[105]
    DIRECTION OUTPUT ;
    USE SIGNAL ;
    ANTENNAPARTIALMETALAREA 1.8731 LAYER met2  ;
    ANTENNAPARTIALMETALSIDEAREA 9.2575 LAYER met2  ;
    PORT
      LAYER met2 ;
        RECT 410.940000 3445.075000 411.080000 3445.560000 ;
    END
  END la_data_out[105]
  PIN la_data_out[104]
    DIRECTION OUTPUT ;
    USE SIGNAL ;
    ANTENNAPARTIALMETALAREA 1.8731 LAYER met2  ;
    ANTENNAPARTIALMETALSIDEAREA 9.2575 LAYER met2  ;
    PORT
      LAYER met2 ;
        RECT 428.420000 3445.075000 428.560000 3445.560000 ;
    END
  END la_data_out[104]
  PIN la_data_out[103]
    DIRECTION OUTPUT ;
    USE SIGNAL ;
    ANTENNAPARTIALMETALAREA 1.8731 LAYER met2  ;
    ANTENNAPARTIALMETALSIDEAREA 9.2575 LAYER met2  ;
    PORT
      LAYER met2 ;
        RECT 445.900000 3445.075000 446.040000 3445.560000 ;
    END
  END la_data_out[103]
  PIN la_data_out[102]
    DIRECTION OUTPUT ;
    USE SIGNAL ;
    ANTENNAPARTIALMETALAREA 1.8731 LAYER met2  ;
    ANTENNAPARTIALMETALSIDEAREA 9.2575 LAYER met2  ;
    PORT
      LAYER met2 ;
        RECT 463.380000 3445.075000 463.520000 3445.560000 ;
    END
  END la_data_out[102]
  PIN la_data_out[101]
    DIRECTION OUTPUT ;
    USE SIGNAL ;
    ANTENNAPARTIALMETALAREA 1.8731 LAYER met2  ;
    ANTENNAPARTIALMETALSIDEAREA 9.2575 LAYER met2  ;
    PORT
      LAYER met2 ;
        RECT 481.320000 3445.075000 481.460000 3445.560000 ;
    END
  END la_data_out[101]
  PIN la_data_out[100]
    DIRECTION OUTPUT ;
    USE SIGNAL ;
    ANTENNAPARTIALMETALAREA 1.8731 LAYER met2  ;
    ANTENNAPARTIALMETALSIDEAREA 9.2575 LAYER met2  ;
    PORT
      LAYER met2 ;
        RECT 498.800000 3445.075000 498.940000 3445.560000 ;
    END
  END la_data_out[100]
  PIN la_data_out[99]
    DIRECTION OUTPUT ;
    USE SIGNAL ;
    ANTENNAPARTIALMETALAREA 1.8731 LAYER met2  ;
    ANTENNAPARTIALMETALSIDEAREA 9.2575 LAYER met2  ;
    PORT
      LAYER met2 ;
        RECT 516.280000 3445.075000 516.420000 3445.560000 ;
    END
  END la_data_out[99]
  PIN la_data_out[98]
    DIRECTION OUTPUT ;
    USE SIGNAL ;
    ANTENNAPARTIALMETALAREA 1.8731 LAYER met2  ;
    ANTENNAPARTIALMETALSIDEAREA 9.2575 LAYER met2  ;
    PORT
      LAYER met2 ;
        RECT 533.760000 3445.075000 533.900000 3445.560000 ;
    END
  END la_data_out[98]
  PIN la_data_out[97]
    DIRECTION OUTPUT ;
    USE SIGNAL ;
    ANTENNAPARTIALMETALAREA 1.7303 LAYER met2  ;
    ANTENNAPARTIALMETALSIDEAREA 8.5435 LAYER met2  ;
    PORT
      LAYER met2 ;
        RECT 551.700000 3445.075000 551.840000 3445.560000 ;
    END
  END la_data_out[97]
  PIN la_data_out[96]
    DIRECTION OUTPUT ;
    USE SIGNAL ;
    ANTENNAPARTIALMETALAREA 1.7303 LAYER met2  ;
    ANTENNAPARTIALMETALSIDEAREA 8.5435 LAYER met2  ;
    PORT
      LAYER met2 ;
        RECT 569.180000 3445.075000 569.320000 3445.560000 ;
    END
  END la_data_out[96]
  PIN la_data_out[95]
    DIRECTION OUTPUT ;
    USE SIGNAL ;
    ANTENNAPARTIALMETALAREA 1.7303 LAYER met2  ;
    ANTENNAPARTIALMETALSIDEAREA 8.5435 LAYER met2  ;
    PORT
      LAYER met2 ;
        RECT 586.660000 3445.075000 586.800000 3445.560000 ;
    END
  END la_data_out[95]
  PIN la_data_out[94]
    DIRECTION OUTPUT ;
    USE SIGNAL ;
    ANTENNAPARTIALMETALAREA 1.9375 LAYER met2  ;
    ANTENNAPARTIALMETALSIDEAREA 9.5795 LAYER met2  ;
    PORT
      LAYER met2 ;
        RECT 604.600000 3445.075000 604.740000 3445.560000 ;
    END
  END la_data_out[94]
  PIN la_data_out[93]
    DIRECTION OUTPUT ;
    USE SIGNAL ;
    ANTENNAPARTIALMETALAREA 1.7303 LAYER met2  ;
    ANTENNAPARTIALMETALSIDEAREA 8.5435 LAYER met2  ;
    PORT
      LAYER met2 ;
        RECT 622.080000 3445.075000 622.220000 3445.560000 ;
    END
  END la_data_out[93]
  PIN la_data_out[92]
    DIRECTION OUTPUT ;
    USE SIGNAL ;
    ANTENNAPARTIALMETALAREA 1.7303 LAYER met2  ;
    ANTENNAPARTIALMETALSIDEAREA 8.5435 LAYER met2  ;
    PORT
      LAYER met2 ;
        RECT 639.560000 3445.075000 639.700000 3445.560000 ;
    END
  END la_data_out[92]
  PIN la_data_out[91]
    DIRECTION OUTPUT ;
    USE SIGNAL ;
    ANTENNAPARTIALMETALAREA 2.0523 LAYER met2  ;
    ANTENNAPARTIALMETALSIDEAREA 10.1535 LAYER met2  ;
    PORT
      LAYER met2 ;
        RECT 657.040000 3445.075000 657.180000 3445.560000 ;
    END
  END la_data_out[91]
  PIN la_data_out[90]
    DIRECTION OUTPUT ;
    USE SIGNAL ;
    ANTENNAPARTIALMETALAREA 1.8731 LAYER met2  ;
    ANTENNAPARTIALMETALSIDEAREA 9.2575 LAYER met2  ;
    PORT
      LAYER met2 ;
        RECT 674.980000 3445.075000 675.120000 3445.560000 ;
    END
  END la_data_out[90]
  PIN la_data_out[89]
    DIRECTION OUTPUT ;
    USE SIGNAL ;
    ANTENNAPARTIALMETALAREA 1.7303 LAYER met2  ;
    ANTENNAPARTIALMETALSIDEAREA 8.5435 LAYER met2  ;
    PORT
      LAYER met2 ;
        RECT 692.460000 3445.075000 692.600000 3445.560000 ;
    END
  END la_data_out[89]
  PIN la_data_out[88]
    DIRECTION OUTPUT ;
    USE SIGNAL ;
    ANTENNAPARTIALMETALAREA 1.7303 LAYER met2  ;
    ANTENNAPARTIALMETALSIDEAREA 8.5435 LAYER met2  ;
    PORT
      LAYER met2 ;
        RECT 709.940000 3445.075000 710.080000 3445.560000 ;
    END
  END la_data_out[88]
  PIN la_data_out[87]
    DIRECTION OUTPUT ;
    USE SIGNAL ;
    ANTENNAPARTIALMETALAREA 1.7303 LAYER met2  ;
    ANTENNAPARTIALMETALSIDEAREA 8.5435 LAYER met2  ;
    PORT
      LAYER met2 ;
        RECT 727.880000 3445.075000 728.020000 3445.560000 ;
    END
  END la_data_out[87]
  PIN la_data_out[86]
    DIRECTION OUTPUT ;
    USE SIGNAL ;
    ANTENNAPARTIALMETALAREA 1.9375 LAYER met2  ;
    ANTENNAPARTIALMETALSIDEAREA 9.5795 LAYER met2  ;
    PORT
      LAYER met2 ;
        RECT 745.360000 3445.075000 745.500000 3445.560000 ;
    END
  END la_data_out[86]
  PIN la_data_out[85]
    DIRECTION OUTPUT ;
    USE SIGNAL ;
    ANTENNAPARTIALMETALAREA 1.7303 LAYER met2  ;
    ANTENNAPARTIALMETALSIDEAREA 8.5435 LAYER met2  ;
    PORT
      LAYER met2 ;
        RECT 762.840000 3445.075000 762.980000 3445.560000 ;
    END
  END la_data_out[85]
  PIN la_data_out[84]
    DIRECTION OUTPUT ;
    USE SIGNAL ;
    ANTENNAPARTIALMETALAREA 1.7303 LAYER met2  ;
    ANTENNAPARTIALMETALSIDEAREA 8.5435 LAYER met2  ;
    PORT
      LAYER met2 ;
        RECT 780.320000 3445.075000 780.460000 3445.560000 ;
    END
  END la_data_out[84]
  PIN la_data_out[83]
    DIRECTION OUTPUT ;
    USE SIGNAL ;
    ANTENNAPARTIALMETALAREA 1.8731 LAYER met2  ;
    ANTENNAPARTIALMETALSIDEAREA 9.2575 LAYER met2  ;
    PORT
      LAYER met2 ;
        RECT 798.260000 3445.075000 798.400000 3445.560000 ;
    END
  END la_data_out[83]
  PIN la_data_out[82]
    DIRECTION OUTPUT ;
    USE SIGNAL ;
    ANTENNAPARTIALMETALAREA 1.7303 LAYER met2  ;
    ANTENNAPARTIALMETALSIDEAREA 8.5435 LAYER met2  ;
    PORT
      LAYER met2 ;
        RECT 815.740000 3445.075000 815.880000 3445.560000 ;
    END
  END la_data_out[82]
  PIN la_data_out[81]
    DIRECTION OUTPUT ;
    USE SIGNAL ;
    ANTENNAPARTIALMETALAREA 1.7303 LAYER met2  ;
    ANTENNAPARTIALMETALSIDEAREA 8.5435 LAYER met2  ;
    PORT
      LAYER met2 ;
        RECT 833.220000 3445.075000 833.360000 3445.560000 ;
    END
  END la_data_out[81]
  PIN la_data_out[80]
    DIRECTION OUTPUT ;
    USE SIGNAL ;
    ANTENNAPARTIALMETALAREA 1.7303 LAYER met2  ;
    ANTENNAPARTIALMETALSIDEAREA 8.5435 LAYER met2  ;
    PORT
      LAYER met2 ;
        RECT 850.700000 3445.075000 850.840000 3445.560000 ;
    END
  END la_data_out[80]
  PIN la_data_out[79]
    DIRECTION OUTPUT ;
    USE SIGNAL ;
    ANTENNAPARTIALMETALAREA 1.9375 LAYER met2  ;
    ANTENNAPARTIALMETALSIDEAREA 9.5795 LAYER met2  ;
    PORT
      LAYER met2 ;
        RECT 868.640000 3445.075000 868.780000 3445.560000 ;
    END
  END la_data_out[79]
  PIN la_data_out[78]
    DIRECTION OUTPUT ;
    USE SIGNAL ;
    ANTENNAPARTIALMETALAREA 1.7303 LAYER met2  ;
    ANTENNAPARTIALMETALSIDEAREA 8.5435 LAYER met2  ;
    PORT
      LAYER met2 ;
        RECT 886.120000 3445.075000 886.260000 3445.560000 ;
    END
  END la_data_out[78]
  PIN la_data_out[77]
    DIRECTION OUTPUT ;
    USE SIGNAL ;
    ANTENNAPARTIALMETALAREA 1.7303 LAYER met2  ;
    ANTENNAPARTIALMETALSIDEAREA 8.5435 LAYER met2  ;
    PORT
      LAYER met2 ;
        RECT 903.600000 3445.075000 903.740000 3445.560000 ;
    END
  END la_data_out[77]
  PIN la_data_out[76]
    DIRECTION OUTPUT ;
    USE SIGNAL ;
    ANTENNAPARTIALMETALAREA 1.7303 LAYER met2  ;
    ANTENNAPARTIALMETALSIDEAREA 8.5435 LAYER met2  ;
    PORT
      LAYER met2 ;
        RECT 921.540000 3445.075000 921.680000 3445.560000 ;
    END
  END la_data_out[76]
  PIN la_data_out[75]
    DIRECTION OUTPUT ;
    USE SIGNAL ;
    ANTENNAPARTIALMETALAREA 1.8731 LAYER met2  ;
    ANTENNAPARTIALMETALSIDEAREA 9.2575 LAYER met2  ;
    PORT
      LAYER met2 ;
        RECT 939.020000 3445.075000 939.160000 3445.560000 ;
    END
  END la_data_out[75]
  PIN la_data_out[74]
    DIRECTION OUTPUT ;
    USE SIGNAL ;
    ANTENNAPARTIALMETALAREA 1.7303 LAYER met2  ;
    ANTENNAPARTIALMETALSIDEAREA 8.5435 LAYER met2  ;
    PORT
      LAYER met2 ;
        RECT 956.500000 3445.075000 956.640000 3445.560000 ;
    END
  END la_data_out[74]
  PIN la_data_out[73]
    DIRECTION OUTPUT ;
    USE SIGNAL ;
    ANTENNAPARTIALMETALAREA 1.9375 LAYER met2  ;
    ANTENNAPARTIALMETALSIDEAREA 9.5795 LAYER met2  ;
    PORT
      LAYER met2 ;
        RECT 973.980000 3445.075000 974.120000 3445.560000 ;
    END
  END la_data_out[73]
  PIN la_data_out[72]
    DIRECTION OUTPUT ;
    USE SIGNAL ;
    ANTENNAPARTIALMETALAREA 1.7303 LAYER met2  ;
    ANTENNAPARTIALMETALSIDEAREA 8.5435 LAYER met2  ;
    PORT
      LAYER met2 ;
        RECT 991.920000 3445.075000 992.060000 3445.560000 ;
    END
  END la_data_out[72]
  PIN la_data_out[71]
    DIRECTION OUTPUT ;
    USE SIGNAL ;
    ANTENNAPARTIALMETALAREA 1.9375 LAYER met2  ;
    ANTENNAPARTIALMETALSIDEAREA 9.5795 LAYER met2  ;
    PORT
      LAYER met2 ;
        RECT 1009.400000 3445.075000 1009.540000 3445.560000 ;
    END
  END la_data_out[71]
  PIN la_data_out[70]
    DIRECTION OUTPUT ;
    USE SIGNAL ;
    ANTENNAPARTIALMETALAREA 2.2434 LAYER met2  ;
    ANTENNAPARTIALMETALSIDEAREA 11.109 LAYER met2  ;
    PORT
      LAYER met2 ;
        RECT 1026.880000 3445.075000 1027.020000 3445.560000 ;
    END
  END la_data_out[70]
  PIN la_data_out[69]
    DIRECTION OUTPUT ;
    USE SIGNAL ;
    ANTENNAPARTIALMETALAREA 1.7303 LAYER met2  ;
    ANTENNAPARTIALMETALSIDEAREA 8.5435 LAYER met2  ;
    PORT
      LAYER met2 ;
        RECT 1044.360000 3445.075000 1044.500000 3445.560000 ;
    END
  END la_data_out[69]
  PIN la_data_out[68]
    DIRECTION OUTPUT ;
    USE SIGNAL ;
    ANTENNAPARTIALMETALAREA 1.8731 LAYER met2  ;
    ANTENNAPARTIALMETALSIDEAREA 9.2575 LAYER met2  ;
    PORT
      LAYER met2 ;
        RECT 1062.300000 3445.075000 1062.440000 3445.560000 ;
    END
  END la_data_out[68]
  PIN la_data_out[67]
    DIRECTION OUTPUT ;
    USE SIGNAL ;
    ANTENNAPARTIALMETALAREA 1.7947 LAYER met2  ;
    ANTENNAPARTIALMETALSIDEAREA 8.8655 LAYER met2  ;
    PORT
      LAYER met2 ;
        RECT 1079.780000 3445.075000 1079.920000 3445.560000 ;
    END
  END la_data_out[67]
  PIN la_data_out[66]
    DIRECTION OUTPUT ;
    USE SIGNAL ;
    ANTENNAPARTIALMETALAREA 1.7303 LAYER met2  ;
    ANTENNAPARTIALMETALSIDEAREA 8.5435 LAYER met2  ;
    PORT
      LAYER met2 ;
        RECT 1097.260000 3445.075000 1097.400000 3445.560000 ;
    END
  END la_data_out[66]
  PIN la_data_out[65]
    DIRECTION OUTPUT ;
    USE SIGNAL ;
    ANTENNAPARTIALMETALAREA 1.7303 LAYER met2  ;
    ANTENNAPARTIALMETALSIDEAREA 8.5435 LAYER met2  ;
    PORT
      LAYER met2 ;
        RECT 1115.200000 3445.075000 1115.340000 3445.560000 ;
    END
  END la_data_out[65]
  PIN la_data_out[64]
    DIRECTION OUTPUT ;
    USE SIGNAL ;
    ANTENNAPARTIALMETALAREA 1.9375 LAYER met2  ;
    ANTENNAPARTIALMETALSIDEAREA 9.5795 LAYER met2  ;
    PORT
      LAYER met2 ;
        RECT 1132.680000 3445.075000 1132.820000 3445.560000 ;
    END
  END la_data_out[64]
  PIN la_data_out[63]
    DIRECTION OUTPUT ;
    USE SIGNAL ;
    ANTENNAPARTIALMETALAREA 1.7303 LAYER met2  ;
    ANTENNAPARTIALMETALSIDEAREA 8.5435 LAYER met2  ;
    PORT
      LAYER met2 ;
        RECT 1150.160000 3445.075000 1150.300000 3445.560000 ;
    END
  END la_data_out[63]
  PIN la_data_out[62]
    DIRECTION OUTPUT ;
    USE SIGNAL ;
    ANTENNAPARTIALMETALAREA 1.7303 LAYER met2  ;
    ANTENNAPARTIALMETALSIDEAREA 8.5435 LAYER met2  ;
    PORT
      LAYER met2 ;
        RECT 1167.640000 3445.075000 1167.780000 3445.560000 ;
    END
  END la_data_out[62]
  PIN la_data_out[61]
    DIRECTION OUTPUT ;
    USE SIGNAL ;
    ANTENNAPARTIALMETALAREA 1.7303 LAYER met2  ;
    ANTENNAPARTIALMETALSIDEAREA 8.5435 LAYER met2  ;
    PORT
      LAYER met2 ;
        RECT 1185.580000 3445.075000 1185.720000 3445.560000 ;
    END
  END la_data_out[61]
  PIN la_data_out[60]
    DIRECTION OUTPUT ;
    USE SIGNAL ;
    ANTENNAPARTIALMETALAREA 1.8731 LAYER met2  ;
    ANTENNAPARTIALMETALSIDEAREA 9.2575 LAYER met2  ;
    PORT
      LAYER met2 ;
        RECT 1203.060000 3445.075000 1203.200000 3445.560000 ;
    END
  END la_data_out[60]
  PIN la_data_out[59]
    DIRECTION OUTPUT ;
    USE SIGNAL ;
    ANTENNAPARTIALMETALAREA 1.7303 LAYER met2  ;
    ANTENNAPARTIALMETALSIDEAREA 8.5435 LAYER met2  ;
    PORT
      LAYER met2 ;
        RECT 1220.540000 3445.075000 1220.680000 3445.560000 ;
    END
  END la_data_out[59]
  PIN la_data_out[58]
    DIRECTION OUTPUT ;
    USE SIGNAL ;
    ANTENNAPARTIALMETALAREA 1.7303 LAYER met2  ;
    ANTENNAPARTIALMETALSIDEAREA 8.5435 LAYER met2  ;
    PORT
      LAYER met2 ;
        RECT 1238.020000 3445.075000 1238.160000 3445.560000 ;
    END
  END la_data_out[58]
  PIN la_data_out[57]
    DIRECTION OUTPUT ;
    USE SIGNAL ;
    ANTENNAPARTIALMETALAREA 1.7303 LAYER met2  ;
    ANTENNAPARTIALMETALSIDEAREA 8.5435 LAYER met2  ;
    PORT
      LAYER met2 ;
        RECT 1255.960000 3445.075000 1256.100000 3445.560000 ;
    END
  END la_data_out[57]
  PIN la_data_out[56]
    DIRECTION OUTPUT ;
    USE SIGNAL ;
    ANTENNAPARTIALMETALAREA 1.9375 LAYER met2  ;
    ANTENNAPARTIALMETALSIDEAREA 9.5795 LAYER met2  ;
    PORT
      LAYER met2 ;
        RECT 1273.440000 3445.075000 1273.580000 3445.560000 ;
    END
  END la_data_out[56]
  PIN la_data_out[55]
    DIRECTION OUTPUT ;
    USE SIGNAL ;
    ANTENNAPARTIALMETALAREA 1.7303 LAYER met2  ;
    ANTENNAPARTIALMETALSIDEAREA 8.5435 LAYER met2  ;
    PORT
      LAYER met2 ;
        RECT 1290.920000 3445.075000 1291.060000 3445.560000 ;
    END
  END la_data_out[55]
  PIN la_data_out[54]
    DIRECTION OUTPUT ;
    USE SIGNAL ;
    ANTENNAPARTIALMETALAREA 1.7303 LAYER met2  ;
    ANTENNAPARTIALMETALSIDEAREA 8.5435 LAYER met2  ;
    PORT
      LAYER met2 ;
        RECT 1308.860000 3445.075000 1309.000000 3445.560000 ;
    END
  END la_data_out[54]
  PIN la_data_out[53]
    DIRECTION OUTPUT ;
    USE SIGNAL ;
    ANTENNAPARTIALMETALAREA 1.8731 LAYER met2  ;
    ANTENNAPARTIALMETALSIDEAREA 9.2575 LAYER met2  ;
    PORT
      LAYER met2 ;
        RECT 1326.340000 3445.075000 1326.480000 3445.560000 ;
    END
  END la_data_out[53]
  PIN la_data_out[52]
    DIRECTION OUTPUT ;
    USE SIGNAL ;
    ANTENNAPARTIALMETALAREA 1.7303 LAYER met2  ;
    ANTENNAPARTIALMETALSIDEAREA 8.5435 LAYER met2  ;
    PORT
      LAYER met2 ;
        RECT 1343.820000 3445.075000 1343.960000 3445.560000 ;
    END
  END la_data_out[52]
  PIN la_data_out[51]
    DIRECTION OUTPUT ;
    USE SIGNAL ;
    ANTENNAPARTIALMETALAREA 1.7303 LAYER met2  ;
    ANTENNAPARTIALMETALSIDEAREA 8.5435 LAYER met2  ;
    PORT
      LAYER met2 ;
        RECT 1361.300000 3445.075000 1361.440000 3445.560000 ;
    END
  END la_data_out[51]
  PIN la_data_out[50]
    DIRECTION OUTPUT ;
    USE SIGNAL ;
    ANTENNAPARTIALMETALAREA 1.7303 LAYER met2  ;
    ANTENNAPARTIALMETALSIDEAREA 8.5435 LAYER met2  ;
    PORT
      LAYER met2 ;
        RECT 1379.240000 3445.075000 1379.380000 3445.560000 ;
    END
  END la_data_out[50]
  PIN la_data_out[49]
    DIRECTION OUTPUT ;
    USE SIGNAL ;
    ANTENNAPARTIALMETALAREA 1.9375 LAYER met2  ;
    ANTENNAPARTIALMETALSIDEAREA 9.5795 LAYER met2  ;
    PORT
      LAYER met2 ;
        RECT 1396.720000 3445.075000 1396.860000 3445.560000 ;
    END
  END la_data_out[49]
  PIN la_data_out[48]
    DIRECTION OUTPUT ;
    USE SIGNAL ;
    ANTENNAPARTIALMETALAREA 1.7303 LAYER met2  ;
    ANTENNAPARTIALMETALSIDEAREA 8.5435 LAYER met2  ;
    PORT
      LAYER met2 ;
        RECT 1414.200000 3445.075000 1414.340000 3445.560000 ;
    END
  END la_data_out[48]
  PIN la_data_out[47]
    DIRECTION OUTPUT ;
    USE SIGNAL ;
    ANTENNAPARTIALMETALAREA 1.7303 LAYER met2  ;
    ANTENNAPARTIALMETALSIDEAREA 8.5435 LAYER met2  ;
    PORT
      LAYER met2 ;
        RECT 1431.680000 3445.075000 1431.820000 3445.560000 ;
    END
  END la_data_out[47]
  PIN la_data_out[46]
    DIRECTION OUTPUT ;
    USE SIGNAL ;
    ANTENNAPARTIALMETALAREA 1.7303 LAYER met2  ;
    ANTENNAPARTIALMETALSIDEAREA 8.5435 LAYER met2  ;
    PORT
      LAYER met2 ;
        RECT 1449.620000 3445.075000 1449.760000 3445.560000 ;
    END
  END la_data_out[46]
  PIN la_data_out[45]
    DIRECTION OUTPUT ;
    USE SIGNAL ;
    ANTENNAPARTIALMETALAREA 1.8731 LAYER met2  ;
    ANTENNAPARTIALMETALSIDEAREA 9.2575 LAYER met2  ;
    PORT
      LAYER met2 ;
        RECT 1467.100000 3445.075000 1467.240000 3445.560000 ;
    END
  END la_data_out[45]
  PIN la_data_out[44]
    DIRECTION OUTPUT ;
    USE SIGNAL ;
    ANTENNAPARTIALMETALAREA 1.7303 LAYER met2  ;
    ANTENNAPARTIALMETALSIDEAREA 8.5435 LAYER met2  ;
    PORT
      LAYER met2 ;
        RECT 1484.580000 3445.075000 1484.720000 3445.560000 ;
    END
  END la_data_out[44]
  PIN la_data_out[43]
    DIRECTION OUTPUT ;
    USE SIGNAL ;
    ANTENNAPARTIALMETALAREA 1.7303 LAYER met2  ;
    ANTENNAPARTIALMETALSIDEAREA 8.5435 LAYER met2  ;
    PORT
      LAYER met2 ;
        RECT 1502.520000 3445.075000 1502.660000 3445.560000 ;
    END
  END la_data_out[43]
  PIN la_data_out[42]
    DIRECTION OUTPUT ;
    USE SIGNAL ;
    ANTENNAPARTIALMETALAREA 1.7303 LAYER met2  ;
    ANTENNAPARTIALMETALSIDEAREA 8.5435 LAYER met2  ;
    PORT
      LAYER met2 ;
        RECT 1520.000000 3445.075000 1520.140000 3445.560000 ;
    END
  END la_data_out[42]
  PIN la_data_out[41]
    DIRECTION OUTPUT ;
    USE SIGNAL ;
    ANTENNAPARTIALMETALAREA 1.9375 LAYER met2  ;
    ANTENNAPARTIALMETALSIDEAREA 9.5795 LAYER met2  ;
    PORT
      LAYER met2 ;
        RECT 1537.480000 3445.075000 1537.620000 3445.560000 ;
    END
  END la_data_out[41]
  PIN la_data_out[40]
    DIRECTION OUTPUT ;
    USE SIGNAL ;
    ANTENNAPARTIALMETALAREA 1.7303 LAYER met2  ;
    ANTENNAPARTIALMETALSIDEAREA 8.5435 LAYER met2  ;
    PORT
      LAYER met2 ;
        RECT 1554.960000 3445.075000 1555.100000 3445.560000 ;
    END
  END la_data_out[40]
  PIN la_data_out[39]
    DIRECTION OUTPUT ;
    USE SIGNAL ;
    ANTENNAPARTIALMETALAREA 1.7303 LAYER met2  ;
    ANTENNAPARTIALMETALSIDEAREA 8.5435 LAYER met2  ;
    PORT
      LAYER met2 ;
        RECT 1572.900000 3445.075000 1573.040000 3445.560000 ;
    END
  END la_data_out[39]
  PIN la_data_out[38]
    DIRECTION OUTPUT ;
    USE SIGNAL ;
    ANTENNAPARTIALMETALAREA 1.8731 LAYER met2  ;
    ANTENNAPARTIALMETALSIDEAREA 9.2575 LAYER met2  ;
    PORT
      LAYER met2 ;
        RECT 1590.380000 3445.075000 1590.520000 3445.560000 ;
    END
  END la_data_out[38]
  PIN la_data_out[37]
    DIRECTION OUTPUT ;
    USE SIGNAL ;
    ANTENNAPARTIALMETALAREA 1.7303 LAYER met2  ;
    ANTENNAPARTIALMETALSIDEAREA 8.5435 LAYER met2  ;
    PORT
      LAYER met2 ;
        RECT 1607.860000 3445.075000 1608.000000 3445.560000 ;
    END
  END la_data_out[37]
  PIN la_data_out[36]
    DIRECTION OUTPUT ;
    USE SIGNAL ;
    ANTENNAPARTIALMETALAREA 1.7303 LAYER met2  ;
    ANTENNAPARTIALMETALSIDEAREA 8.5435 LAYER met2  ;
    PORT
      LAYER met2 ;
        RECT 1625.800000 3445.075000 1625.940000 3445.560000 ;
    END
  END la_data_out[36]
  PIN la_data_out[35]
    DIRECTION OUTPUT ;
    USE SIGNAL ;
    ANTENNAPARTIALMETALAREA 1.7303 LAYER met2  ;
    ANTENNAPARTIALMETALSIDEAREA 8.5435 LAYER met2  ;
    PORT
      LAYER met2 ;
        RECT 1643.280000 3445.075000 1643.420000 3445.560000 ;
    END
  END la_data_out[35]
  PIN la_data_out[34]
    DIRECTION OUTPUT ;
    USE SIGNAL ;
    ANTENNAPARTIALMETALAREA 1.8899 LAYER met2  ;
    ANTENNAPARTIALMETALSIDEAREA 9.3415 LAYER met2  ;
    PORT
      LAYER met2 ;
        RECT 1660.760000 3445.075000 1660.900000 3445.560000 ;
    END
  END la_data_out[34]
  PIN la_data_out[33]
    DIRECTION OUTPUT ;
    USE SIGNAL ;
    ANTENNAPARTIALMETALAREA 1.8899 LAYER met2  ;
    ANTENNAPARTIALMETALSIDEAREA 9.3415 LAYER met2  ;
    PORT
      LAYER met2 ;
        RECT 1678.240000 3445.075000 1678.380000 3445.560000 ;
    END
  END la_data_out[33]
  PIN la_data_out[32]
    DIRECTION OUTPUT ;
    USE SIGNAL ;
    ANTENNAPARTIALMETALAREA 1.7303 LAYER met2  ;
    ANTENNAPARTIALMETALSIDEAREA 8.5435 LAYER met2  ;
    PORT
      LAYER met2 ;
        RECT 1696.180000 3445.075000 1696.320000 3445.560000 ;
    END
  END la_data_out[32]
  PIN la_data_out[31]
    DIRECTION OUTPUT ;
    USE SIGNAL ;
    ANTENNAPARTIALMETALAREA 1.7303 LAYER met2  ;
    ANTENNAPARTIALMETALSIDEAREA 8.5435 LAYER met2  ;
    PORT
      LAYER met2 ;
        RECT 1713.660000 3445.075000 1713.800000 3445.560000 ;
    END
  END la_data_out[31]
  PIN la_data_out[30]
    DIRECTION OUTPUT ;
    USE SIGNAL ;
    ANTENNAPARTIALMETALAREA 2.4198 LAYER met2  ;
    ANTENNAPARTIALMETALSIDEAREA 11.991 LAYER met2  ;
    PORT
      LAYER met2 ;
        RECT 1731.140000 3445.075000 1731.280000 3445.560000 ;
    END
  END la_data_out[30]
  PIN la_data_out[29]
    DIRECTION OUTPUT ;
    USE SIGNAL ;
    ANTENNAPARTIALMETALAREA 1.7303 LAYER met2  ;
    ANTENNAPARTIALMETALSIDEAREA 8.5435 LAYER met2  ;
    PORT
      LAYER met2 ;
        RECT 1748.620000 3445.075000 1748.760000 3445.560000 ;
    END
  END la_data_out[29]
  PIN la_data_out[28]
    DIRECTION OUTPUT ;
    USE SIGNAL ;
    ANTENNAPARTIALMETALAREA 1.7303 LAYER met2  ;
    ANTENNAPARTIALMETALSIDEAREA 8.5435 LAYER met2  ;
    PORT
      LAYER met2 ;
        RECT 1766.560000 3445.075000 1766.700000 3445.560000 ;
    END
  END la_data_out[28]
  PIN la_data_out[27]
    DIRECTION OUTPUT ;
    USE SIGNAL ;
    ANTENNAPARTIALMETALAREA 1.8899 LAYER met2  ;
    ANTENNAPARTIALMETALSIDEAREA 9.3415 LAYER met2  ;
    PORT
      LAYER met2 ;
        RECT 1784.040000 3445.075000 1784.180000 3445.560000 ;
    END
  END la_data_out[27]
  PIN la_data_out[26]
    DIRECTION OUTPUT ;
    USE SIGNAL ;
    ANTENNAPARTIALMETALAREA 1.8255 LAYER met2  ;
    ANTENNAPARTIALMETALSIDEAREA 9.0195 LAYER met2  ;
    PORT
      LAYER met2 ;
        RECT 1801.520000 3445.075000 1801.660000 3445.560000 ;
    END
  END la_data_out[26]
  PIN la_data_out[25]
    DIRECTION OUTPUT ;
    USE SIGNAL ;
    ANTENNAPARTIALMETALAREA 1.7303 LAYER met2  ;
    ANTENNAPARTIALMETALSIDEAREA 8.5435 LAYER met2  ;
    PORT
      LAYER met2 ;
        RECT 1819.460000 3445.075000 1819.600000 3445.560000 ;
    END
  END la_data_out[25]
  PIN la_data_out[24]
    DIRECTION OUTPUT ;
    USE SIGNAL ;
    ANTENNAPARTIALMETALAREA 1.7303 LAYER met2  ;
    ANTENNAPARTIALMETALSIDEAREA 8.5435 LAYER met2  ;
    PORT
      LAYER met2 ;
        RECT 1836.940000 3445.075000 1837.080000 3445.560000 ;
    END
  END la_data_out[24]
  PIN la_data_out[23]
    DIRECTION OUTPUT ;
    USE SIGNAL ;
    ANTENNAPARTIALMETALAREA 1.8255 LAYER met2  ;
    ANTENNAPARTIALMETALSIDEAREA 9.0195 LAYER met2  ;
    PORT
      LAYER met2 ;
        RECT 1854.420000 3445.075000 1854.560000 3445.560000 ;
    END
  END la_data_out[23]
  PIN la_data_out[22]
    DIRECTION OUTPUT ;
    USE SIGNAL ;
    ANTENNAPARTIALMETALAREA 1.7303 LAYER met2  ;
    ANTENNAPARTIALMETALSIDEAREA 8.5435 LAYER met2  ;
    PORT
      LAYER met2 ;
        RECT 1871.900000 3445.075000 1872.040000 3445.560000 ;
    END
  END la_data_out[22]
  PIN la_data_out[21]
    DIRECTION OUTPUT ;
    USE SIGNAL ;
    ANTENNAPARTIALMETALAREA 1.7303 LAYER met2  ;
    ANTENNAPARTIALMETALSIDEAREA 8.5435 LAYER met2  ;
    PORT
      LAYER met2 ;
        RECT 1889.840000 3445.075000 1889.980000 3445.560000 ;
    END
  END la_data_out[21]
  PIN la_data_out[20]
    DIRECTION OUTPUT ;
    USE SIGNAL ;
    ANTENNAPARTIALMETALAREA 1.7303 LAYER met2  ;
    ANTENNAPARTIALMETALSIDEAREA 8.5435 LAYER met2  ;
    PORT
      LAYER met2 ;
        RECT 1907.320000 3445.075000 1907.460000 3445.560000 ;
    END
  END la_data_out[20]
  PIN la_data_out[19]
    DIRECTION OUTPUT ;
    USE SIGNAL ;
    ANTENNAPARTIALMETALAREA 1.8899 LAYER met2  ;
    ANTENNAPARTIALMETALSIDEAREA 9.3415 LAYER met2  ;
    PORT
      LAYER met2 ;
        RECT 1924.800000 3445.075000 1924.940000 3445.560000 ;
    END
  END la_data_out[19]
  PIN la_data_out[18]
    DIRECTION OUTPUT ;
    USE SIGNAL ;
    ANTENNAPARTIALMETALAREA 1.7303 LAYER met2  ;
    ANTENNAPARTIALMETALSIDEAREA 8.5435 LAYER met2  ;
    PORT
      LAYER met2 ;
        RECT 1942.280000 3445.075000 1942.420000 3445.560000 ;
    END
  END la_data_out[18]
  PIN la_data_out[17]
    DIRECTION OUTPUT ;
    USE SIGNAL ;
    ANTENNAPARTIALMETALAREA 1.8255 LAYER met2  ;
    ANTENNAPARTIALMETALSIDEAREA 9.0195 LAYER met2  ;
    PORT
      LAYER met2 ;
        RECT 1960.220000 3445.075000 1960.360000 3445.560000 ;
    END
  END la_data_out[17]
  PIN la_data_out[16]
    DIRECTION OUTPUT ;
    USE SIGNAL ;
    ANTENNAPARTIALMETALAREA 1.7303 LAYER met2  ;
    ANTENNAPARTIALMETALSIDEAREA 8.5435 LAYER met2  ;
    PORT
      LAYER met2 ;
        RECT 1977.700000 3445.075000 1977.840000 3445.560000 ;
    END
  END la_data_out[16]
  PIN la_data_out[15]
    DIRECTION OUTPUT ;
    USE SIGNAL ;
    ANTENNAPARTIALMETALAREA 1.8255 LAYER met2  ;
    ANTENNAPARTIALMETALSIDEAREA 9.0195 LAYER met2  ;
    PORT
      LAYER met2 ;
        RECT 1995.180000 3445.075000 1995.320000 3445.560000 ;
    END
  END la_data_out[15]
  PIN la_data_out[14]
    DIRECTION OUTPUT ;
    USE SIGNAL ;
    ANTENNAPARTIALMETALAREA 1.8591 LAYER met2  ;
    ANTENNAPARTIALMETALSIDEAREA 9.1875 LAYER met2  ;
    PORT
      LAYER met2 ;
        RECT 2013.120000 3445.075000 2013.260000 3445.560000 ;
    END
  END la_data_out[14]
  PIN la_data_out[13]
    DIRECTION OUTPUT ;
    USE SIGNAL ;
    ANTENNAPARTIALMETALAREA 1.8255 LAYER met2  ;
    ANTENNAPARTIALMETALSIDEAREA 9.0195 LAYER met2  ;
    PORT
      LAYER met2 ;
        RECT 2030.600000 3445.075000 2030.740000 3445.560000 ;
    END
  END la_data_out[13]
  PIN la_data_out[12]
    DIRECTION OUTPUT ;
    USE SIGNAL ;
    ANTENNAPARTIALMETALAREA 1.7303 LAYER met2  ;
    ANTENNAPARTIALMETALSIDEAREA 8.5435 LAYER met2  ;
    PORT
      LAYER met2 ;
        RECT 2048.080000 3445.075000 2048.220000 3445.560000 ;
    END
  END la_data_out[12]
  PIN la_data_out[11]
    DIRECTION OUTPUT ;
    USE SIGNAL ;
    ANTENNAPARTIALMETALAREA 1.9543 LAYER met2  ;
    ANTENNAPARTIALMETALSIDEAREA 9.6635 LAYER met2  ;
    PORT
      LAYER met2 ;
        RECT 2065.560000 3445.075000 2065.700000 3445.560000 ;
    END
  END la_data_out[11]
  PIN la_data_out[10]
    DIRECTION OUTPUT ;
    USE SIGNAL ;
    ANTENNAPARTIALMETALAREA 1.8255 LAYER met2  ;
    ANTENNAPARTIALMETALSIDEAREA 9.0195 LAYER met2  ;
    PORT
      LAYER met2 ;
        RECT 2083.500000 3445.075000 2083.640000 3445.560000 ;
    END
  END la_data_out[10]
  PIN la_data_out[9]
    DIRECTION OUTPUT ;
    USE SIGNAL ;
    ANTENNAPARTIALMETALAREA 2.0831 LAYER met2  ;
    ANTENNAPARTIALMETALSIDEAREA 10.3075 LAYER met2  ;
    PORT
      LAYER met2 ;
        RECT 2100.980000 3445.075000 2101.120000 3445.560000 ;
    END
  END la_data_out[9]
  PIN la_data_out[8]
    DIRECTION OUTPUT ;
    USE SIGNAL ;
    ANTENNAPARTIALMETALAREA 1.8255 LAYER met2  ;
    ANTENNAPARTIALMETALSIDEAREA 9.0195 LAYER met2  ;
    PORT
      LAYER met2 ;
        RECT 2118.460000 3445.075000 2118.600000 3445.560000 ;
    END
  END la_data_out[8]
  PIN la_data_out[7]
    DIRECTION OUTPUT ;
    USE SIGNAL ;
    ANTENNAPARTIALMETALAREA 1.7303 LAYER met2  ;
    ANTENNAPARTIALMETALSIDEAREA 8.5435 LAYER met2  ;
    PORT
      LAYER met2 ;
        RECT 2135.940000 3445.075000 2136.080000 3445.560000 ;
    END
  END la_data_out[7]
  PIN la_data_out[6]
    DIRECTION OUTPUT ;
    USE SIGNAL ;
    ANTENNAPARTIALMETALAREA 1.8255 LAYER met2  ;
    ANTENNAPARTIALMETALSIDEAREA 9.0195 LAYER met2  ;
    PORT
      LAYER met2 ;
        RECT 2153.880000 3445.075000 2154.020000 3445.560000 ;
    END
  END la_data_out[6]
  PIN la_data_out[5]
    DIRECTION OUTPUT ;
    USE SIGNAL ;
    ANTENNAPARTIALMETALAREA 1.8255 LAYER met2  ;
    ANTENNAPARTIALMETALSIDEAREA 9.0195 LAYER met2  ;
    PORT
      LAYER met2 ;
        RECT 2171.360000 3445.075000 2171.500000 3445.560000 ;
    END
  END la_data_out[5]
  PIN la_data_out[4]
    DIRECTION OUTPUT ;
    USE SIGNAL ;
    ANTENNAPARTIALMETALAREA 1.8899 LAYER met2  ;
    ANTENNAPARTIALMETALSIDEAREA 9.3415 LAYER met2  ;
    PORT
      LAYER met2 ;
        RECT 2188.840000 3445.075000 2188.980000 3445.560000 ;
    END
  END la_data_out[4]
  PIN la_data_out[3]
    DIRECTION OUTPUT ;
    USE SIGNAL ;
    ANTENNAPARTIALMETALAREA 1.7303 LAYER met2  ;
    ANTENNAPARTIALMETALSIDEAREA 8.5435 LAYER met2  ;
    PORT
      LAYER met2 ;
        RECT 2206.780000 3445.075000 2206.920000 3445.560000 ;
    END
  END la_data_out[3]
  PIN la_data_out[2]
    DIRECTION OUTPUT ;
    USE SIGNAL ;
    ANTENNAPARTIALMETALAREA 4.2111 LAYER met2  ;
    ANTENNAPARTIALMETALSIDEAREA 20.9475 LAYER met2  ;
    PORT
      LAYER met2 ;
        RECT 2224.260000 3445.075000 2224.400000 3445.560000 ;
    END
  END la_data_out[2]
  PIN la_data_out[1]
    DIRECTION OUTPUT ;
    USE SIGNAL ;
    ANTENNAPARTIALMETALAREA 2.0971 LAYER met2  ;
    ANTENNAPARTIALMETALSIDEAREA 10.3775 LAYER met2  ;
    PORT
      LAYER met2 ;
        RECT 2241.740000 3445.075000 2241.880000 3445.560000 ;
    END
  END la_data_out[1]
  PIN la_data_out[0]
    DIRECTION OUTPUT ;
    USE SIGNAL ;
    ANTENNAPARTIALMETALAREA 1.9207 LAYER met2  ;
    ANTENNAPARTIALMETALSIDEAREA 9.4955 LAYER met2  ;
    PORT
      LAYER met2 ;
        RECT 2259.220000 3445.075000 2259.360000 3445.560000 ;
    END
  END la_data_out[0]
  PIN la_oenb[127]
    DIRECTION INPUT ;
    USE SIGNAL ;
    PORT
      LAYER met2 ;
        RECT 17.640000 3445.075000 17.780000 3445.560000 ;
    END
  END la_oenb[127]
  PIN la_oenb[126]
    DIRECTION INPUT ;
    USE SIGNAL ;
    PORT
      LAYER met2 ;
        RECT 35.120000 3445.075000 35.260000 3445.560000 ;
    END
  END la_oenb[126]
  PIN la_oenb[125]
    DIRECTION INPUT ;
    USE SIGNAL ;
    PORT
      LAYER met2 ;
        RECT 52.600000 3445.075000 52.740000 3445.560000 ;
    END
  END la_oenb[125]
  PIN la_oenb[124]
    DIRECTION INPUT ;
    USE SIGNAL ;
    PORT
      LAYER met2 ;
        RECT 70.540000 3445.075000 70.680000 3445.560000 ;
    END
  END la_oenb[124]
  PIN la_oenb[123]
    DIRECTION INPUT ;
    USE SIGNAL ;
    PORT
      LAYER met2 ;
        RECT 88.020000 3445.075000 88.160000 3445.560000 ;
    END
  END la_oenb[123]
  PIN la_oenb[122]
    DIRECTION INPUT ;
    USE SIGNAL ;
    PORT
      LAYER met2 ;
        RECT 105.500000 3445.075000 105.640000 3445.560000 ;
    END
  END la_oenb[122]
  PIN la_oenb[121]
    DIRECTION INPUT ;
    USE SIGNAL ;
    PORT
      LAYER met2 ;
        RECT 122.980000 3445.075000 123.120000 3445.560000 ;
    END
  END la_oenb[121]
  PIN la_oenb[120]
    DIRECTION INPUT ;
    USE SIGNAL ;
    PORT
      LAYER met2 ;
        RECT 140.920000 3445.075000 141.060000 3445.560000 ;
    END
  END la_oenb[120]
  PIN la_oenb[119]
    DIRECTION INPUT ;
    USE SIGNAL ;
    PORT
      LAYER met2 ;
        RECT 158.400000 3445.075000 158.540000 3445.560000 ;
    END
  END la_oenb[119]
  PIN la_oenb[118]
    DIRECTION INPUT ;
    USE SIGNAL ;
    PORT
      LAYER met2 ;
        RECT 175.880000 3445.075000 176.020000 3445.560000 ;
    END
  END la_oenb[118]
  PIN la_oenb[117]
    DIRECTION INPUT ;
    USE SIGNAL ;
    PORT
      LAYER met2 ;
        RECT 193.820000 3445.075000 193.960000 3445.560000 ;
    END
  END la_oenb[117]
  PIN la_oenb[116]
    DIRECTION INPUT ;
    USE SIGNAL ;
    PORT
      LAYER met2 ;
        RECT 211.300000 3445.075000 211.440000 3445.560000 ;
    END
  END la_oenb[116]
  PIN la_oenb[115]
    DIRECTION INPUT ;
    USE SIGNAL ;
    PORT
      LAYER met2 ;
        RECT 228.780000 3445.075000 228.920000 3445.560000 ;
    END
  END la_oenb[115]
  PIN la_oenb[114]
    DIRECTION INPUT ;
    USE SIGNAL ;
    PORT
      LAYER met2 ;
        RECT 246.260000 3445.075000 246.400000 3445.560000 ;
    END
  END la_oenb[114]
  PIN la_oenb[113]
    DIRECTION INPUT ;
    USE SIGNAL ;
    PORT
      LAYER met2 ;
        RECT 264.200000 3445.075000 264.340000 3445.560000 ;
    END
  END la_oenb[113]
  PIN la_oenb[112]
    DIRECTION INPUT ;
    USE SIGNAL ;
    PORT
      LAYER met2 ;
        RECT 281.680000 3445.075000 281.820000 3445.560000 ;
    END
  END la_oenb[112]
  PIN la_oenb[111]
    DIRECTION INPUT ;
    USE SIGNAL ;
    PORT
      LAYER met2 ;
        RECT 299.160000 3445.075000 299.300000 3445.560000 ;
    END
  END la_oenb[111]
  PIN la_oenb[110]
    DIRECTION INPUT ;
    USE SIGNAL ;
    PORT
      LAYER met2 ;
        RECT 316.640000 3445.075000 316.780000 3445.560000 ;
    END
  END la_oenb[110]
  PIN la_oenb[109]
    DIRECTION INPUT ;
    USE SIGNAL ;
    PORT
      LAYER met2 ;
        RECT 334.580000 3445.075000 334.720000 3445.560000 ;
    END
  END la_oenb[109]
  PIN la_oenb[108]
    DIRECTION INPUT ;
    USE SIGNAL ;
    PORT
      LAYER met2 ;
        RECT 352.060000 3445.075000 352.200000 3445.560000 ;
    END
  END la_oenb[108]
  PIN la_oenb[107]
    DIRECTION INPUT ;
    USE SIGNAL ;
    PORT
      LAYER met2 ;
        RECT 369.540000 3445.075000 369.680000 3445.560000 ;
    END
  END la_oenb[107]
  PIN la_oenb[106]
    DIRECTION INPUT ;
    USE SIGNAL ;
    PORT
      LAYER met2 ;
        RECT 387.480000 3445.075000 387.620000 3445.560000 ;
    END
  END la_oenb[106]
  PIN la_oenb[105]
    DIRECTION INPUT ;
    USE SIGNAL ;
    PORT
      LAYER met2 ;
        RECT 404.960000 3445.075000 405.100000 3445.560000 ;
    END
  END la_oenb[105]
  PIN la_oenb[104]
    DIRECTION INPUT ;
    USE SIGNAL ;
    PORT
      LAYER met2 ;
        RECT 422.440000 3445.075000 422.580000 3445.560000 ;
    END
  END la_oenb[104]
  PIN la_oenb[103]
    DIRECTION INPUT ;
    USE SIGNAL ;
    PORT
      LAYER met2 ;
        RECT 439.920000 3445.075000 440.060000 3445.560000 ;
    END
  END la_oenb[103]
  PIN la_oenb[102]
    DIRECTION INPUT ;
    USE SIGNAL ;
    PORT
      LAYER met2 ;
        RECT 457.860000 3445.075000 458.000000 3445.560000 ;
    END
  END la_oenb[102]
  PIN la_oenb[101]
    DIRECTION INPUT ;
    USE SIGNAL ;
    PORT
      LAYER met2 ;
        RECT 475.340000 3445.075000 475.480000 3445.560000 ;
    END
  END la_oenb[101]
  PIN la_oenb[100]
    DIRECTION INPUT ;
    USE SIGNAL ;
    PORT
      LAYER met2 ;
        RECT 492.820000 3445.075000 492.960000 3445.560000 ;
    END
  END la_oenb[100]
  PIN la_oenb[99]
    DIRECTION INPUT ;
    USE SIGNAL ;
    PORT
      LAYER met2 ;
        RECT 510.300000 3445.075000 510.440000 3445.560000 ;
    END
  END la_oenb[99]
  PIN la_oenb[98]
    DIRECTION INPUT ;
    USE SIGNAL ;
    PORT
      LAYER met2 ;
        RECT 528.240000 3445.075000 528.380000 3445.560000 ;
    END
  END la_oenb[98]
  PIN la_oenb[97]
    DIRECTION INPUT ;
    USE SIGNAL ;
    PORT
      LAYER met2 ;
        RECT 545.720000 3445.075000 545.860000 3445.560000 ;
    END
  END la_oenb[97]
  PIN la_oenb[96]
    DIRECTION INPUT ;
    USE SIGNAL ;
    PORT
      LAYER met2 ;
        RECT 563.200000 3445.075000 563.340000 3445.560000 ;
    END
  END la_oenb[96]
  PIN la_oenb[95]
    DIRECTION INPUT ;
    USE SIGNAL ;
    PORT
      LAYER met2 ;
        RECT 581.140000 3445.075000 581.280000 3445.560000 ;
    END
  END la_oenb[95]
  PIN la_oenb[94]
    DIRECTION INPUT ;
    USE SIGNAL ;
    PORT
      LAYER met2 ;
        RECT 598.620000 3445.075000 598.760000 3445.560000 ;
    END
  END la_oenb[94]
  PIN la_oenb[93]
    DIRECTION INPUT ;
    USE SIGNAL ;
    PORT
      LAYER met2 ;
        RECT 616.100000 3445.075000 616.240000 3445.560000 ;
    END
  END la_oenb[93]
  PIN la_oenb[92]
    DIRECTION INPUT ;
    USE SIGNAL ;
    PORT
      LAYER met2 ;
        RECT 633.580000 3445.075000 633.720000 3445.560000 ;
    END
  END la_oenb[92]
  PIN la_oenb[91]
    DIRECTION INPUT ;
    USE SIGNAL ;
    PORT
      LAYER met2 ;
        RECT 651.520000 3445.075000 651.660000 3445.560000 ;
    END
  END la_oenb[91]
  PIN la_oenb[90]
    DIRECTION INPUT ;
    USE SIGNAL ;
    PORT
      LAYER met2 ;
        RECT 669.000000 3445.075000 669.140000 3445.560000 ;
    END
  END la_oenb[90]
  PIN la_oenb[89]
    DIRECTION INPUT ;
    USE SIGNAL ;
    PORT
      LAYER met2 ;
        RECT 686.480000 3445.075000 686.620000 3445.560000 ;
    END
  END la_oenb[89]
  PIN la_oenb[88]
    DIRECTION INPUT ;
    USE SIGNAL ;
    PORT
      LAYER met2 ;
        RECT 703.960000 3445.075000 704.100000 3445.560000 ;
    END
  END la_oenb[88]
  PIN la_oenb[87]
    DIRECTION INPUT ;
    USE SIGNAL ;
    PORT
      LAYER met2 ;
        RECT 721.900000 3445.075000 722.040000 3445.560000 ;
    END
  END la_oenb[87]
  PIN la_oenb[86]
    DIRECTION INPUT ;
    USE SIGNAL ;
    PORT
      LAYER met2 ;
        RECT 739.380000 3445.075000 739.520000 3445.560000 ;
    END
  END la_oenb[86]
  PIN la_oenb[85]
    DIRECTION INPUT ;
    USE SIGNAL ;
    PORT
      LAYER met2 ;
        RECT 756.860000 3445.075000 757.000000 3445.560000 ;
    END
  END la_oenb[85]
  PIN la_oenb[84]
    DIRECTION INPUT ;
    USE SIGNAL ;
    PORT
      LAYER met2 ;
        RECT 774.800000 3445.075000 774.940000 3445.560000 ;
    END
  END la_oenb[84]
  PIN la_oenb[83]
    DIRECTION INPUT ;
    USE SIGNAL ;
    PORT
      LAYER met2 ;
        RECT 792.280000 3445.075000 792.420000 3445.560000 ;
    END
  END la_oenb[83]
  PIN la_oenb[82]
    DIRECTION INPUT ;
    USE SIGNAL ;
    PORT
      LAYER met2 ;
        RECT 809.760000 3445.075000 809.900000 3445.560000 ;
    END
  END la_oenb[82]
  PIN la_oenb[81]
    DIRECTION INPUT ;
    USE SIGNAL ;
    PORT
      LAYER met2 ;
        RECT 827.240000 3445.075000 827.380000 3445.560000 ;
    END
  END la_oenb[81]
  PIN la_oenb[80]
    DIRECTION INPUT ;
    USE SIGNAL ;
    PORT
      LAYER met2 ;
        RECT 845.180000 3445.075000 845.320000 3445.560000 ;
    END
  END la_oenb[80]
  PIN la_oenb[79]
    DIRECTION INPUT ;
    USE SIGNAL ;
    PORT
      LAYER met2 ;
        RECT 862.660000 3445.075000 862.800000 3445.560000 ;
    END
  END la_oenb[79]
  PIN la_oenb[78]
    DIRECTION INPUT ;
    USE SIGNAL ;
    PORT
      LAYER met2 ;
        RECT 880.140000 3445.075000 880.280000 3445.560000 ;
    END
  END la_oenb[78]
  PIN la_oenb[77]
    DIRECTION INPUT ;
    USE SIGNAL ;
    PORT
      LAYER met2 ;
        RECT 897.620000 3445.075000 897.760000 3445.560000 ;
    END
  END la_oenb[77]
  PIN la_oenb[76]
    DIRECTION INPUT ;
    USE SIGNAL ;
    PORT
      LAYER met2 ;
        RECT 915.560000 3445.075000 915.700000 3445.560000 ;
    END
  END la_oenb[76]
  PIN la_oenb[75]
    DIRECTION INPUT ;
    USE SIGNAL ;
    PORT
      LAYER met2 ;
        RECT 933.040000 3445.075000 933.180000 3445.560000 ;
    END
  END la_oenb[75]
  PIN la_oenb[74]
    DIRECTION INPUT ;
    USE SIGNAL ;
    PORT
      LAYER met2 ;
        RECT 950.520000 3445.075000 950.660000 3445.560000 ;
    END
  END la_oenb[74]
  PIN la_oenb[73]
    DIRECTION INPUT ;
    USE SIGNAL ;
    PORT
      LAYER met2 ;
        RECT 968.460000 3445.075000 968.600000 3445.560000 ;
    END
  END la_oenb[73]
  PIN la_oenb[72]
    DIRECTION INPUT ;
    USE SIGNAL ;
    PORT
      LAYER met2 ;
        RECT 985.940000 3445.075000 986.080000 3445.560000 ;
    END
  END la_oenb[72]
  PIN la_oenb[71]
    DIRECTION INPUT ;
    USE SIGNAL ;
    PORT
      LAYER met2 ;
        RECT 1003.420000 3445.075000 1003.560000 3445.560000 ;
    END
  END la_oenb[71]
  PIN la_oenb[70]
    DIRECTION INPUT ;
    USE SIGNAL ;
    PORT
      LAYER met2 ;
        RECT 1020.900000 3445.075000 1021.040000 3445.560000 ;
    END
  END la_oenb[70]
  PIN la_oenb[69]
    DIRECTION INPUT ;
    USE SIGNAL ;
    PORT
      LAYER met2 ;
        RECT 1038.840000 3445.075000 1038.980000 3445.560000 ;
    END
  END la_oenb[69]
  PIN la_oenb[68]
    DIRECTION INPUT ;
    USE SIGNAL ;
    PORT
      LAYER met2 ;
        RECT 1056.320000 3445.075000 1056.460000 3445.560000 ;
    END
  END la_oenb[68]
  PIN la_oenb[67]
    DIRECTION INPUT ;
    USE SIGNAL ;
    PORT
      LAYER met2 ;
        RECT 1073.800000 3445.075000 1073.940000 3445.560000 ;
    END
  END la_oenb[67]
  PIN la_oenb[66]
    DIRECTION INPUT ;
    USE SIGNAL ;
    PORT
      LAYER met2 ;
        RECT 1091.740000 3445.075000 1091.880000 3445.560000 ;
    END
  END la_oenb[66]
  PIN la_oenb[65]
    DIRECTION INPUT ;
    USE SIGNAL ;
    PORT
      LAYER met2 ;
        RECT 1109.220000 3445.075000 1109.360000 3445.560000 ;
    END
  END la_oenb[65]
  PIN la_oenb[64]
    DIRECTION INPUT ;
    USE SIGNAL ;
    PORT
      LAYER met2 ;
        RECT 1126.700000 3445.075000 1126.840000 3445.560000 ;
    END
  END la_oenb[64]
  PIN la_oenb[63]
    DIRECTION INPUT ;
    USE SIGNAL ;
    PORT
      LAYER met2 ;
        RECT 1144.180000 3445.075000 1144.320000 3445.560000 ;
    END
  END la_oenb[63]
  PIN la_oenb[62]
    DIRECTION INPUT ;
    USE SIGNAL ;
    PORT
      LAYER met2 ;
        RECT 1162.120000 3445.075000 1162.260000 3445.560000 ;
    END
  END la_oenb[62]
  PIN la_oenb[61]
    DIRECTION INPUT ;
    USE SIGNAL ;
    PORT
      LAYER met2 ;
        RECT 1179.600000 3445.075000 1179.740000 3445.560000 ;
    END
  END la_oenb[61]
  PIN la_oenb[60]
    DIRECTION INPUT ;
    USE SIGNAL ;
    PORT
      LAYER met2 ;
        RECT 1197.080000 3445.075000 1197.220000 3445.560000 ;
    END
  END la_oenb[60]
  PIN la_oenb[59]
    DIRECTION INPUT ;
    USE SIGNAL ;
    PORT
      LAYER met2 ;
        RECT 1214.560000 3445.075000 1214.700000 3445.560000 ;
    END
  END la_oenb[59]
  PIN la_oenb[58]
    DIRECTION INPUT ;
    USE SIGNAL ;
    PORT
      LAYER met2 ;
        RECT 1232.500000 3445.075000 1232.640000 3445.560000 ;
    END
  END la_oenb[58]
  PIN la_oenb[57]
    DIRECTION INPUT ;
    USE SIGNAL ;
    PORT
      LAYER met2 ;
        RECT 1249.980000 3445.075000 1250.120000 3445.560000 ;
    END
  END la_oenb[57]
  PIN la_oenb[56]
    DIRECTION INPUT ;
    USE SIGNAL ;
    PORT
      LAYER met2 ;
        RECT 1267.460000 3445.075000 1267.600000 3445.560000 ;
    END
  END la_oenb[56]
  PIN la_oenb[55]
    DIRECTION INPUT ;
    USE SIGNAL ;
    PORT
      LAYER met2 ;
        RECT 1285.400000 3445.075000 1285.540000 3445.560000 ;
    END
  END la_oenb[55]
  PIN la_oenb[54]
    DIRECTION INPUT ;
    USE SIGNAL ;
    PORT
      LAYER met2 ;
        RECT 1302.880000 3445.075000 1303.020000 3445.560000 ;
    END
  END la_oenb[54]
  PIN la_oenb[53]
    DIRECTION INPUT ;
    USE SIGNAL ;
    PORT
      LAYER met2 ;
        RECT 1320.360000 3445.075000 1320.500000 3445.560000 ;
    END
  END la_oenb[53]
  PIN la_oenb[52]
    DIRECTION INPUT ;
    USE SIGNAL ;
    PORT
      LAYER met2 ;
        RECT 1337.840000 3445.075000 1337.980000 3445.560000 ;
    END
  END la_oenb[52]
  PIN la_oenb[51]
    DIRECTION INPUT ;
    USE SIGNAL ;
    PORT
      LAYER met2 ;
        RECT 1355.780000 3445.075000 1355.920000 3445.560000 ;
    END
  END la_oenb[51]
  PIN la_oenb[50]
    DIRECTION INPUT ;
    USE SIGNAL ;
    PORT
      LAYER met2 ;
        RECT 1373.260000 3445.075000 1373.400000 3445.560000 ;
    END
  END la_oenb[50]
  PIN la_oenb[49]
    DIRECTION INPUT ;
    USE SIGNAL ;
    PORT
      LAYER met2 ;
        RECT 1390.740000 3445.075000 1390.880000 3445.560000 ;
    END
  END la_oenb[49]
  PIN la_oenb[48]
    DIRECTION INPUT ;
    USE SIGNAL ;
    PORT
      LAYER met2 ;
        RECT 1408.220000 3445.075000 1408.360000 3445.560000 ;
    END
  END la_oenb[48]
  PIN la_oenb[47]
    DIRECTION INPUT ;
    USE SIGNAL ;
    PORT
      LAYER met2 ;
        RECT 1426.160000 3445.075000 1426.300000 3445.560000 ;
    END
  END la_oenb[47]
  PIN la_oenb[46]
    DIRECTION INPUT ;
    USE SIGNAL ;
    PORT
      LAYER met2 ;
        RECT 1443.640000 3445.075000 1443.780000 3445.560000 ;
    END
  END la_oenb[46]
  PIN la_oenb[45]
    DIRECTION INPUT ;
    USE SIGNAL ;
    PORT
      LAYER met2 ;
        RECT 1461.120000 3445.075000 1461.260000 3445.560000 ;
    END
  END la_oenb[45]
  PIN la_oenb[44]
    DIRECTION INPUT ;
    USE SIGNAL ;
    PORT
      LAYER met2 ;
        RECT 1479.060000 3445.075000 1479.200000 3445.560000 ;
    END
  END la_oenb[44]
  PIN la_oenb[43]
    DIRECTION INPUT ;
    USE SIGNAL ;
    PORT
      LAYER met2 ;
        RECT 1496.540000 3445.075000 1496.680000 3445.560000 ;
    END
  END la_oenb[43]
  PIN la_oenb[42]
    DIRECTION INPUT ;
    USE SIGNAL ;
    PORT
      LAYER met2 ;
        RECT 1514.020000 3445.075000 1514.160000 3445.560000 ;
    END
  END la_oenb[42]
  PIN la_oenb[41]
    DIRECTION INPUT ;
    USE SIGNAL ;
    PORT
      LAYER met2 ;
        RECT 1531.500000 3445.075000 1531.640000 3445.560000 ;
    END
  END la_oenb[41]
  PIN la_oenb[40]
    DIRECTION INPUT ;
    USE SIGNAL ;
    PORT
      LAYER met2 ;
        RECT 1549.440000 3445.075000 1549.580000 3445.560000 ;
    END
  END la_oenb[40]
  PIN la_oenb[39]
    DIRECTION INPUT ;
    USE SIGNAL ;
    PORT
      LAYER met2 ;
        RECT 1566.920000 3445.075000 1567.060000 3445.560000 ;
    END
  END la_oenb[39]
  PIN la_oenb[38]
    DIRECTION INPUT ;
    USE SIGNAL ;
    PORT
      LAYER met2 ;
        RECT 1584.400000 3445.075000 1584.540000 3445.560000 ;
    END
  END la_oenb[38]
  PIN la_oenb[37]
    DIRECTION INPUT ;
    USE SIGNAL ;
    PORT
      LAYER met2 ;
        RECT 1601.880000 3445.075000 1602.020000 3445.560000 ;
    END
  END la_oenb[37]
  PIN la_oenb[36]
    DIRECTION INPUT ;
    USE SIGNAL ;
    PORT
      LAYER met2 ;
        RECT 1619.820000 3445.075000 1619.960000 3445.560000 ;
    END
  END la_oenb[36]
  PIN la_oenb[35]
    DIRECTION INPUT ;
    USE SIGNAL ;
    PORT
      LAYER met2 ;
        RECT 1637.300000 3445.075000 1637.440000 3445.560000 ;
    END
  END la_oenb[35]
  PIN la_oenb[34]
    DIRECTION INPUT ;
    USE SIGNAL ;
    PORT
      LAYER met2 ;
        RECT 1654.780000 3445.075000 1654.920000 3445.560000 ;
    END
  END la_oenb[34]
  PIN la_oenb[33]
    DIRECTION INPUT ;
    USE SIGNAL ;
    PORT
      LAYER met2 ;
        RECT 1672.720000 3445.075000 1672.860000 3445.560000 ;
    END
  END la_oenb[33]
  PIN la_oenb[32]
    DIRECTION INPUT ;
    USE SIGNAL ;
    PORT
      LAYER met2 ;
        RECT 1690.200000 3445.075000 1690.340000 3445.560000 ;
    END
  END la_oenb[32]
  PIN la_oenb[31]
    DIRECTION INPUT ;
    USE SIGNAL ;
    PORT
      LAYER met2 ;
        RECT 1707.680000 3445.075000 1707.820000 3445.560000 ;
    END
  END la_oenb[31]
  PIN la_oenb[30]
    DIRECTION INPUT ;
    USE SIGNAL ;
    PORT
      LAYER met2 ;
        RECT 1725.160000 3445.075000 1725.300000 3445.560000 ;
    END
  END la_oenb[30]
  PIN la_oenb[29]
    DIRECTION INPUT ;
    USE SIGNAL ;
    PORT
      LAYER met2 ;
        RECT 1743.100000 3445.075000 1743.240000 3445.560000 ;
    END
  END la_oenb[29]
  PIN la_oenb[28]
    DIRECTION INPUT ;
    USE SIGNAL ;
    PORT
      LAYER met2 ;
        RECT 1760.580000 3445.075000 1760.720000 3445.560000 ;
    END
  END la_oenb[28]
  PIN la_oenb[27]
    DIRECTION INPUT ;
    USE SIGNAL ;
    PORT
      LAYER met2 ;
        RECT 1778.060000 3445.075000 1778.200000 3445.560000 ;
    END
  END la_oenb[27]
  PIN la_oenb[26]
    DIRECTION INPUT ;
    USE SIGNAL ;
    PORT
      LAYER met2 ;
        RECT 1795.540000 3445.075000 1795.680000 3445.560000 ;
    END
  END la_oenb[26]
  PIN la_oenb[25]
    DIRECTION INPUT ;
    USE SIGNAL ;
    PORT
      LAYER met2 ;
        RECT 1813.480000 3445.075000 1813.620000 3445.560000 ;
    END
  END la_oenb[25]
  PIN la_oenb[24]
    DIRECTION INPUT ;
    USE SIGNAL ;
    PORT
      LAYER met2 ;
        RECT 1830.960000 3445.075000 1831.100000 3445.560000 ;
    END
  END la_oenb[24]
  PIN la_oenb[23]
    DIRECTION INPUT ;
    USE SIGNAL ;
    PORT
      LAYER met2 ;
        RECT 1848.440000 3445.075000 1848.580000 3445.560000 ;
    END
  END la_oenb[23]
  PIN la_oenb[22]
    DIRECTION INPUT ;
    USE SIGNAL ;
    PORT
      LAYER met2 ;
        RECT 1866.380000 3445.075000 1866.520000 3445.560000 ;
    END
  END la_oenb[22]
  PIN la_oenb[21]
    DIRECTION INPUT ;
    USE SIGNAL ;
    PORT
      LAYER met2 ;
        RECT 1883.860000 3445.075000 1884.000000 3445.560000 ;
    END
  END la_oenb[21]
  PIN la_oenb[20]
    DIRECTION INPUT ;
    USE SIGNAL ;
    PORT
      LAYER met2 ;
        RECT 1901.340000 3445.075000 1901.480000 3445.560000 ;
    END
  END la_oenb[20]
  PIN la_oenb[19]
    DIRECTION INPUT ;
    USE SIGNAL ;
    PORT
      LAYER met2 ;
        RECT 1918.820000 3445.075000 1918.960000 3445.560000 ;
    END
  END la_oenb[19]
  PIN la_oenb[18]
    DIRECTION INPUT ;
    USE SIGNAL ;
    PORT
      LAYER met2 ;
        RECT 1936.760000 3445.075000 1936.900000 3445.560000 ;
    END
  END la_oenb[18]
  PIN la_oenb[17]
    DIRECTION INPUT ;
    USE SIGNAL ;
    PORT
      LAYER met2 ;
        RECT 1954.240000 3445.075000 1954.380000 3445.560000 ;
    END
  END la_oenb[17]
  PIN la_oenb[16]
    DIRECTION INPUT ;
    USE SIGNAL ;
    PORT
      LAYER met2 ;
        RECT 1971.720000 3445.075000 1971.860000 3445.560000 ;
    END
  END la_oenb[16]
  PIN la_oenb[15]
    DIRECTION INPUT ;
    USE SIGNAL ;
    PORT
      LAYER met2 ;
        RECT 1989.660000 3445.075000 1989.800000 3445.560000 ;
    END
  END la_oenb[15]
  PIN la_oenb[14]
    DIRECTION INPUT ;
    USE SIGNAL ;
    PORT
      LAYER met2 ;
        RECT 2007.140000 3445.075000 2007.280000 3445.560000 ;
    END
  END la_oenb[14]
  PIN la_oenb[13]
    DIRECTION INPUT ;
    USE SIGNAL ;
    PORT
      LAYER met2 ;
        RECT 2024.620000 3445.075000 2024.760000 3445.560000 ;
    END
  END la_oenb[13]
  PIN la_oenb[12]
    DIRECTION INPUT ;
    USE SIGNAL ;
    PORT
      LAYER met2 ;
        RECT 2042.100000 3445.075000 2042.240000 3445.560000 ;
    END
  END la_oenb[12]
  PIN la_oenb[11]
    DIRECTION INPUT ;
    USE SIGNAL ;
    PORT
      LAYER met2 ;
        RECT 2060.040000 3445.075000 2060.180000 3445.560000 ;
    END
  END la_oenb[11]
  PIN la_oenb[10]
    DIRECTION INPUT ;
    USE SIGNAL ;
    PORT
      LAYER met2 ;
        RECT 2077.520000 3445.075000 2077.660000 3445.560000 ;
    END
  END la_oenb[10]
  PIN la_oenb[9]
    DIRECTION INPUT ;
    USE SIGNAL ;
    PORT
      LAYER met2 ;
        RECT 2095.000000 3445.075000 2095.140000 3445.560000 ;
    END
  END la_oenb[9]
  PIN la_oenb[8]
    DIRECTION INPUT ;
    USE SIGNAL ;
    PORT
      LAYER met2 ;
        RECT 2112.480000 3445.075000 2112.620000 3445.560000 ;
    END
  END la_oenb[8]
  PIN la_oenb[7]
    DIRECTION INPUT ;
    USE SIGNAL ;
    PORT
      LAYER met2 ;
        RECT 2130.420000 3445.075000 2130.560000 3445.560000 ;
    END
  END la_oenb[7]
  PIN la_oenb[6]
    DIRECTION INPUT ;
    USE SIGNAL ;
    PORT
      LAYER met2 ;
        RECT 2147.900000 3445.075000 2148.040000 3445.560000 ;
    END
  END la_oenb[6]
  PIN la_oenb[5]
    DIRECTION INPUT ;
    USE SIGNAL ;
    PORT
      LAYER met2 ;
        RECT 2165.380000 3445.075000 2165.520000 3445.560000 ;
    END
  END la_oenb[5]
  PIN la_oenb[4]
    DIRECTION INPUT ;
    USE SIGNAL ;
    PORT
      LAYER met2 ;
        RECT 2183.320000 3445.075000 2183.460000 3445.560000 ;
    END
  END la_oenb[4]
  PIN la_oenb[3]
    DIRECTION INPUT ;
    USE SIGNAL ;
    PORT
      LAYER met2 ;
        RECT 2200.800000 3445.075000 2200.940000 3445.560000 ;
    END
  END la_oenb[3]
  PIN la_oenb[2]
    DIRECTION INPUT ;
    USE SIGNAL ;
    PORT
      LAYER met2 ;
        RECT 2218.280000 3445.075000 2218.420000 3445.560000 ;
    END
  END la_oenb[2]
  PIN la_oenb[1]
    DIRECTION INPUT ;
    USE SIGNAL ;
    PORT
      LAYER met2 ;
        RECT 2235.760000 3445.075000 2235.900000 3445.560000 ;
    END
  END la_oenb[1]
  PIN la_oenb[0]
    DIRECTION INPUT ;
    USE SIGNAL ;
    PORT
      LAYER met2 ;
        RECT 2253.700000 3445.075000 2253.840000 3445.560000 ;
    END
  END la_oenb[0]
  PIN io_in[37]
    DIRECTION INPUT ;
    USE SIGNAL ;
    PORT
      LAYER met3 ;
        RECT 2887.080000 3277.250000 2887.880000 3277.550000 ;
    END
  END io_in[37]
  PIN io_in[36]
    DIRECTION INPUT ;
    USE SIGNAL ;
    PORT
      LAYER met3 ;
        RECT 2887.080000 3025.320000 2887.880000 3025.620000 ;
    END
  END io_in[36]
  PIN io_in[35]
    DIRECTION INPUT ;
    USE SIGNAL ;
    ANTENNAPARTIALMETALAREA 2.2476 LAYER met3  ;
    ANTENNAPARTIALMETALSIDEAREA 13.864 LAYER met3  ;
    ANTENNAMODEL OXIDE1 ;
    ANTENNAGATEAREA 0.2475 LAYER met3  ;
    ANTENNAMAXAREACAR 74.4501 LAYER met3  ;
    ANTENNAMAXSIDEAREACAR 377.984 LAYER met3  ;
    ANTENNAMAXCUTCAR 0.369293 LAYER via3  ;
    PORT
      LAYER met3 ;
        RECT 2887.080000 2773.390000 2887.880000 2773.690000 ;
    END
  END io_in[35]
  PIN io_in[34]
    DIRECTION INPUT ;
    USE SIGNAL ;
    ANTENNAPARTIALMETALAREA 3.4764 LAYER met3  ;
    ANTENNAPARTIALMETALSIDEAREA 18.536 LAYER met3  ;
    ANTENNAMODEL OXIDE1 ;
    ANTENNAGATEAREA 0.576 LAYER met3  ;
    ANTENNAMAXAREACAR 7.64583 LAYER met3  ;
    ANTENNAMAXSIDEAREACAR 37.9201 LAYER met3  ;
    ANTENNAMAXCUTCAR 0.158681 LAYER via3  ;
    PORT
      LAYER met3 ;
        RECT 2887.080000 2520.850000 2887.880000 2521.150000 ;
    END
  END io_in[34]
  PIN io_in[33]
    DIRECTION INPUT ;
    USE SIGNAL ;
    ANTENNAPARTIALMETALAREA 1.6186 LAYER met3  ;
    ANTENNAPARTIALMETALSIDEAREA 8.624 LAYER met3  ;
    ANTENNAPARTIALCUTAREA 0.04 LAYER via3  ;
    ANTENNADIFFAREA 0.4347 LAYER met4  ;
    ANTENNAPARTIALMETALAREA 125.474 LAYER met4  ;
    ANTENNAPARTIALMETALSIDEAREA 669.664 LAYER met4  ;
    ANTENNAMODEL OXIDE1 ;
    ANTENNAGATEAREA 1.5867 LAYER met4  ;
    ANTENNAMAXAREACAR 85.0672 LAYER met4  ;
    ANTENNAMAXSIDEAREACAR 434.506 LAYER met4  ;
    ANTENNAMAXCUTCAR 0.131082 LAYER via4  ;
    PORT
      LAYER met3 ;
        RECT 2887.080000 2268.920000 2887.880000 2269.220000 ;
    END
  END io_in[33]
  PIN io_in[32]
    DIRECTION INPUT ;
    USE SIGNAL ;
    ANTENNAPARTIALMETALAREA 0.631125 LAYER met3  ;
    ANTENNAPARTIALMETALSIDEAREA 3.344 LAYER met3  ;
    ANTENNAMODEL OXIDE1 ;
    ANTENNAGATEAREA 1.152 LAYER met3  ;
    ANTENNAMAXAREACAR 16.0148 LAYER met3  ;
    ANTENNAMAXSIDEAREACAR 78.2179 LAYER met3  ;
    ANTENNAMAXCUTCAR 0.0793403 LAYER via3  ;
    PORT
      LAYER met3 ;
        RECT 2887.080000 2016.990000 2887.880000 2017.290000 ;
    END
  END io_in[32]
  PIN io_in[31]
    DIRECTION INPUT ;
    USE SIGNAL ;
    ANTENNAPARTIALMETALAREA 0.3946 LAYER met3  ;
    ANTENNAPARTIALMETALSIDEAREA 2.096 LAYER met3  ;
    ANTENNAPARTIALCUTAREA 0.04 LAYER via3  ;
    ANTENNAPARTIALMETALAREA 27.5688 LAYER met4  ;
    ANTENNAPARTIALMETALSIDEAREA 147.504 LAYER met4  ;
    ANTENNAMODEL OXIDE1 ;
    ANTENNAGATEAREA 0.576 LAYER met4  ;
    ANTENNAMAXAREACAR 56.2958 LAYER met4  ;
    ANTENNAMAXSIDEAREACAR 297.078 LAYER met4  ;
    ANTENNAMAXCUTCAR 0.228125 LAYER via4  ;
    PORT
      LAYER met3 ;
        RECT 2887.080000 1765.060000 2887.880000 1765.360000 ;
    END
  END io_in[31]
  PIN io_in[30]
    DIRECTION INPUT ;
    USE SIGNAL ;
    ANTENNAPARTIALMETALAREA 0.3804 LAYER met3  ;
    ANTENNAPARTIALMETALSIDEAREA 2.024 LAYER met3  ;
    ANTENNAMODEL OXIDE1 ;
    ANTENNAGATEAREA 1.152 LAYER met3  ;
    ANTENNAMAXAREACAR 68.5115 LAYER met3  ;
    ANTENNAMAXSIDEAREACAR 340.708 LAYER met3  ;
    ANTENNAMAXCUTCAR 0.0793403 LAYER via3  ;
    PORT
      LAYER met3 ;
        RECT 2887.080000 1513.130000 2887.880000 1513.430000 ;
    END
  END io_in[30]
  PIN io_in[29]
    DIRECTION INPUT ;
    USE SIGNAL ;
    ANTENNAPARTIALMETALAREA 0.3024 LAYER met3  ;
    ANTENNAPARTIALMETALSIDEAREA 1.608 LAYER met3  ;
    ANTENNAMODEL OXIDE1 ;
    ANTENNAGATEAREA 1.152 LAYER met3  ;
    ANTENNAMAXAREACAR 47.3506 LAYER met3  ;
    ANTENNAMAXSIDEAREACAR 234.849 LAYER met3  ;
    ANTENNAMAXCUTCAR 0.0793403 LAYER via3  ;
    PORT
      LAYER met3 ;
        RECT 2887.080000 1260.590000 2887.880000 1260.890000 ;
    END
  END io_in[29]
  PIN io_in[28]
    DIRECTION INPUT ;
    USE SIGNAL ;
    ANTENNAPARTIALMETALAREA 0.1644 LAYER met3  ;
    ANTENNAPARTIALMETALSIDEAREA 0.872 LAYER met3  ;
    ANTENNAMODEL OXIDE1 ;
    ANTENNAGATEAREA 1.152 LAYER met3  ;
    ANTENNAMAXAREACAR 54.3568 LAYER met3  ;
    ANTENNAMAXSIDEAREACAR 269.872 LAYER met3  ;
    ANTENNAMAXCUTCAR 0.0793403 LAYER via3  ;
    PORT
      LAYER met3 ;
        RECT 2887.080000 1008.660000 2887.880000 1008.960000 ;
    END
  END io_in[28]
  PIN io_in[27]
    DIRECTION INPUT ;
    USE SIGNAL ;
    ANTENNAPARTIALMETALAREA 0.3946 LAYER met3  ;
    ANTENNAPARTIALMETALSIDEAREA 2.096 LAYER met3  ;
    ANTENNAPARTIALCUTAREA 0.04 LAYER via3  ;
    ANTENNAPARTIALMETALAREA 10.3668 LAYER met4  ;
    ANTENNAPARTIALMETALSIDEAREA 55.76 LAYER met4  ;
    ANTENNAMODEL OXIDE1 ;
    ANTENNAGATEAREA 1.152 LAYER met4  ;
    ANTENNAMAXAREACAR 65.8692 LAYER met4  ;
    ANTENNAMAXSIDEAREACAR 331.379 LAYER met4  ;
    ANTENNAMAXCUTCAR 0.114063 LAYER via4  ;
    PORT
      LAYER met3 ;
        RECT 2887.080000 756.730000 2887.880000 757.030000 ;
    END
  END io_in[27]
  PIN io_in[26]
    DIRECTION INPUT ;
    USE SIGNAL ;
    ANTENNAPARTIALMETALAREA 1.4064 LAYER met3  ;
    ANTENNAPARTIALMETALSIDEAREA 7.496 LAYER met3  ;
    ANTENNAMODEL OXIDE1 ;
    ANTENNAGATEAREA 0.315 LAYER met3  ;
    ANTENNAMAXAREACAR 14.4086 LAYER met3  ;
    ANTENNAMAXSIDEAREACAR 69.9079 LAYER met3  ;
    ANTENNAMAXCUTCAR 0.290159 LAYER via3  ;
    PORT
      LAYER met3 ;
        RECT 2887.080000 504.800000 2887.880000 505.100000 ;
    END
  END io_in[26]
  PIN io_in[25]
    DIRECTION INPUT ;
    USE SIGNAL ;
    ANTENNAPARTIALMETALAREA 0.4404 LAYER met3  ;
    ANTENNAPARTIALMETALSIDEAREA 2.344 LAYER met3  ;
    ANTENNAMODEL OXIDE1 ;
    ANTENNAGATEAREA 1.152 LAYER met3  ;
    ANTENNAMAXAREACAR 59.0107 LAYER met3  ;
    ANTENNAMAXSIDEAREACAR 293.189 LAYER met3  ;
    ANTENNAMAXCUTCAR 0.0793403 LAYER via3  ;
    PORT
      LAYER met3 ;
        RECT 2887.080000 252.870000 2887.880000 253.170000 ;
    END
  END io_in[25]
  PIN io_in[24]
    DIRECTION INPUT ;
    USE SIGNAL ;
    ANTENNAPARTIALMETALAREA 4.5594 LAYER met3  ;
    ANTENNAPARTIALMETALSIDEAREA 24.76 LAYER met3  ;
    ANTENNAPARTIALCUTAREA 0.04 LAYER via3  ;
    ANTENNAPARTIALMETALAREA 12.7296 LAYER met4  ;
    ANTENNAPARTIALMETALSIDEAREA 68.832 LAYER met4  ;
    ANTENNAMODEL OXIDE1 ;
    ANTENNAGATEAREA 0.213 LAYER met4  ;
    ANTENNAMAXAREACAR 140.938 LAYER met4  ;
    ANTENNAMAXSIDEAREACAR 726.545 LAYER met4  ;
    ANTENNAMAXCUTCAR 0.616901 LAYER via4  ;
    PORT
      LAYER met3 ;
        RECT 2887.080000 0.330000 2887.880000 0.630000 ;
    END
  END io_in[24]
  PIN io_in[23]
    DIRECTION INPUT ;
    USE SIGNAL ;
    ANTENNAPARTIALMETALAREA 44.881 LAYER met2  ;
    ANTENNAPARTIALMETALSIDEAREA 224.126 LAYER met2  ;
    ANTENNAPARTIALCUTAREA 0.04 LAYER via2  ;
    ANTENNAPARTIALMETALAREA 0.2509 LAYER met3  ;
    ANTENNAPARTIALMETALSIDEAREA 1.808 LAYER met3  ;
    ANTENNAPARTIALCUTAREA 0.04 LAYER via3  ;
    ANTENNAPARTIALMETALAREA 4.1448 LAYER met4  ;
    ANTENNAPARTIALMETALSIDEAREA 22.576 LAYER met4  ;
    ANTENNAMODEL OXIDE1 ;
    ANTENNAGATEAREA 0.315 LAYER met4  ;
    ANTENNAMAXAREACAR 22.5917 LAYER met4  ;
    ANTENNAMAXSIDEAREACAR 116.943 LAYER met4  ;
    ANTENNAMAXCUTCAR 0.417143 LAYER via4  ;
    PORT
      LAYER met2 ;
        RECT 2665.860000 0.000000 2666.000000 0.485000 ;
    END
  END io_in[23]
  PIN io_in[22]
    DIRECTION INPUT ;
    USE SIGNAL ;
    ANTENNAPARTIALMETALAREA 19.0831 LAYER met2  ;
    ANTENNAPARTIALMETALSIDEAREA 95.1895 LAYER met2  ;
    ANTENNAMODEL OXIDE1 ;
    ANTENNAGATEAREA 0.576 LAYER met2  ;
    ANTENNAMAXAREACAR 34.9646 LAYER met2  ;
    ANTENNAMAXSIDEAREACAR 172.415 LAYER met2  ;
    ANTENNAMAXCUTCAR 0.0892361 LAYER via2  ;
    PORT
      LAYER met2 ;
        RECT 2332.360000 0.000000 2332.500000 0.485000 ;
    END
  END io_in[22]
  PIN io_in[21]
    DIRECTION INPUT ;
    USE SIGNAL ;
    ANTENNAPARTIALMETALAREA 3.0683 LAYER met2  ;
    ANTENNAPARTIALMETALSIDEAREA 14.9975 LAYER met2  ;
    ANTENNAMODEL OXIDE1 ;
    ANTENNAGATEAREA 1.152 LAYER met2  ;
    ANTENNAMAXAREACAR 3.27906 LAYER met2  ;
    ANTENNAMAXSIDEAREACAR 14.2899 LAYER met2  ;
    ANTENNAMAXCUTCAR 0.0446181 LAYER via2  ;
    PORT
      LAYER met2 ;
        RECT 1999.320000 0.000000 1999.460000 0.485000 ;
    END
  END io_in[21]
  PIN io_in[20]
    DIRECTION INPUT ;
    USE SIGNAL ;
    ANTENNAPARTIALMETALAREA 2.7351 LAYER met2  ;
    ANTENNAPARTIALMETALSIDEAREA 13.3315 LAYER met2  ;
    ANTENNAMODEL OXIDE1 ;
    ANTENNAGATEAREA 0.315 LAYER met2  ;
    ANTENNAMAXAREACAR 10.1559 LAYER met2  ;
    ANTENNAMAXSIDEAREACAR 46.5778 LAYER met2  ;
    ANTENNAMAXCUTCAR 0.163175 LAYER via2  ;
    PORT
      LAYER met2 ;
        RECT 1666.280000 0.000000 1666.420000 0.485000 ;
    END
  END io_in[20]
  PIN io_in[19]
    DIRECTION INPUT ;
    USE SIGNAL ;
    ANTENNAPARTIALMETALAREA 2.3755 LAYER met2  ;
    ANTENNAPARTIALMETALSIDEAREA 11.6515 LAYER met2  ;
    ANTENNAMODEL OXIDE1 ;
    ANTENNAGATEAREA 0.213 LAYER met2  ;
    ANTENNAMAXAREACAR 12.6606 LAYER met2  ;
    ANTENNAMAXSIDEAREACAR 58.3756 LAYER met2  ;
    ANTENNAMAXCUTCAR 0.241315 LAYER via2  ;
    PORT
      LAYER met2 ;
        RECT 1333.240000 0.000000 1333.380000 0.485000 ;
    END
  END io_in[19]
  PIN io_in[18]
    DIRECTION INPUT ;
    USE SIGNAL ;
    ANTENNAPARTIALMETALAREA 2.6611 LAYER met2  ;
    ANTENNAPARTIALMETALSIDEAREA 13.0795 LAYER met2  ;
    ANTENNAMODEL OXIDE1 ;
    ANTENNAGATEAREA 0.213 LAYER met2  ;
    ANTENNAMAXAREACAR 14.0014 LAYER met2  ;
    ANTENNAMAXSIDEAREACAR 65.0798 LAYER met2  ;
    ANTENNAMAXCUTCAR 0.241315 LAYER via2  ;
    PORT
      LAYER met2 ;
        RECT 999.740000 0.000000 999.880000 0.485000 ;
    END
  END io_in[18]
  PIN io_in[17]
    DIRECTION INPUT ;
    USE SIGNAL ;
    ANTENNAPARTIALMETALAREA 2.2803 LAYER met2  ;
    ANTENNAPARTIALMETALSIDEAREA 11.1755 LAYER met2  ;
    ANTENNAMODEL OXIDE1 ;
    ANTENNAGATEAREA 0.315 LAYER met2  ;
    ANTENNAMAXAREACAR 8.34921 LAYER met2  ;
    ANTENNAMAXSIDEAREACAR 38.1333 LAYER met2  ;
    ANTENNAMAXCUTCAR 0.163175 LAYER via2  ;
    PORT
      LAYER met2 ;
        RECT 666.700000 0.000000 666.840000 0.485000 ;
    END
  END io_in[17]
  PIN io_in[16]
    DIRECTION INPUT ;
    USE SIGNAL ;
    ANTENNAPARTIALMETALAREA 38.3023 LAYER met2  ;
    ANTENNAPARTIALMETALSIDEAREA 191.286 LAYER met2  ;
    ANTENNAMODEL OXIDE1 ;
    ANTENNAGATEAREA 1.152 LAYER met2  ;
    ANTENNAMAXAREACAR 34.9907 LAYER met2  ;
    ANTENNAMAXSIDEAREACAR 172.951 LAYER met2  ;
    ANTENNAMAXCUTCAR 0.0446181 LAYER via2  ;
    PORT
      LAYER met2 ;
        RECT 333.660000 0.000000 333.800000 0.485000 ;
    END
  END io_in[16]
  PIN io_in[15]
    DIRECTION INPUT ;
    USE SIGNAL ;
    ANTENNAPARTIALMETALAREA 62.1779 LAYER met2  ;
    ANTENNAPARTIALMETALSIDEAREA 310.663 LAYER met2  ;
    ANTENNAMODEL OXIDE1 ;
    ANTENNAGATEAREA 1.152 LAYER met2  ;
    ANTENNAMAXAREACAR 56.427 LAYER met2  ;
    ANTENNAMAXSIDEAREACAR 280.132 LAYER met2  ;
    ANTENNAMAXCUTCAR 0.0446181 LAYER via2  ;
    PORT
      LAYER met2 ;
        RECT 0.160000 0.000000 0.300000 0.485000 ;
    END
  END io_in[15]
  PIN io_in[14]
    DIRECTION INPUT ;
    USE SIGNAL ;
    ANTENNAPARTIALMETALAREA 0.2116 LAYER met3  ;
    ANTENNAPARTIALMETALSIDEAREA 1.12 LAYER met3  ;
    ANTENNAPARTIALCUTAREA 0.04 LAYER via3  ;
    ANTENNAPARTIALMETALAREA 7.5576 LAYER met4  ;
    ANTENNAPARTIALMETALSIDEAREA 41.248 LAYER met4  ;
    ANTENNAMODEL OXIDE1 ;
    ANTENNAGATEAREA 0.99 LAYER met4  ;
    ANTENNAMAXAREACAR 11.4861 LAYER met4  ;
    ANTENNAMAXSIDEAREACAR 59.497 LAYER met4  ;
    ANTENNAMAXCUTCAR 0.132727 LAYER via4  ;
    PORT
      LAYER met3 ;
        RECT 0.000000 156.490000 0.800000 156.790000 ;
    END
  END io_in[14]
  PIN io_in[13]
    DIRECTION INPUT ;
    USE SIGNAL ;
    ANTENNADIFFAREA 0.4347 LAYER met3  ;
    ANTENNAPARTIALMETALAREA 0.9924 LAYER met3  ;
    ANTENNAPARTIALMETALSIDEAREA 5.288 LAYER met3  ;
    ANTENNAMODEL OXIDE1 ;
    ANTENNAGATEAREA 1.0107 LAYER met3  ;
    ANTENNAMAXAREACAR 82.1379 LAYER met3  ;
    ANTENNAMAXSIDEAREACAR 401.526 LAYER met3  ;
    ANTENNAMAXCUTCAR 0.0904324 LAYER via3  ;
    PORT
      LAYER met3 ;
        RECT 0.000000 391.340000 0.800000 391.640000 ;
    END
  END io_in[13]
  PIN io_in[12]
    DIRECTION INPUT ;
    USE SIGNAL ;
    ANTENNAPARTIALMETALAREA 0.4404 LAYER met3  ;
    ANTENNAPARTIALMETALSIDEAREA 2.344 LAYER met3  ;
    ANTENNAMODEL OXIDE1 ;
    ANTENNAGATEAREA 1.152 LAYER met3  ;
    ANTENNAMAXAREACAR 69.949 LAYER met3  ;
    ANTENNAMAXSIDEAREACAR 347.913 LAYER met3  ;
    ANTENNAMAXCUTCAR 0.0793403 LAYER via3  ;
    PORT
      LAYER met3 ;
        RECT 0.000000 626.190000 0.800000 626.490000 ;
    END
  END io_in[12]
  PIN io_in[11]
    DIRECTION INPUT ;
    USE SIGNAL ;
    ANTENNAPARTIALMETALAREA 0.7464 LAYER met3  ;
    ANTENNAPARTIALMETALSIDEAREA 3.976 LAYER met3  ;
    ANTENNAMODEL OXIDE1 ;
    ANTENNAGATEAREA 1.152 LAYER met3  ;
    ANTENNAMAXAREACAR 75.4766 LAYER met3  ;
    ANTENNAMAXSIDEAREACAR 375.537 LAYER met3  ;
    ANTENNAMAXCUTCAR 0.0793403 LAYER via3  ;
    PORT
      LAYER met3 ;
        RECT 0.000000 861.040000 0.800000 861.340000 ;
    END
  END io_in[11]
  PIN io_in[10]
    DIRECTION INPUT ;
    USE SIGNAL ;
    ANTENNAPARTIALMETALAREA 0.8544 LAYER met3  ;
    ANTENNAPARTIALMETALSIDEAREA 4.552 LAYER met3  ;
    ANTENNAMODEL OXIDE1 ;
    ANTENNAGATEAREA 1.152 LAYER met3  ;
    ANTENNAMAXAREACAR 66.8327 LAYER met3  ;
    ANTENNAMAXSIDEAREACAR 332.451 LAYER met3  ;
    ANTENNAMAXCUTCAR 0.0793403 LAYER via3  ;
    PORT
      LAYER met3 ;
        RECT 0.000000 1095.890000 0.800000 1096.190000 ;
    END
  END io_in[10]
  PIN io_in[9]
    DIRECTION INPUT ;
    USE SIGNAL ;
    ANTENNAPARTIALMETALAREA 1.8204 LAYER met3  ;
    ANTENNAPARTIALMETALSIDEAREA 9.704 LAYER met3  ;
    ANTENNAMODEL OXIDE1 ;
    ANTENNAGATEAREA 1.152 LAYER met3  ;
    ANTENNAMAXAREACAR 65.7304 LAYER met3  ;
    ANTENNAMAXSIDEAREACAR 327.22 LAYER met3  ;
    ANTENNAMAXCUTCAR 0.0793403 LAYER via3  ;
    PORT
      LAYER met3 ;
        RECT 0.000000 1330.740000 0.800000 1331.040000 ;
    END
  END io_in[9]
  PIN io_in[8]
    DIRECTION INPUT ;
    USE SIGNAL ;
    ANTENNAPARTIALMETALAREA 4.4224 LAYER met3  ;
    ANTENNAPARTIALMETALSIDEAREA 24.048 LAYER met3  ;
    ANTENNAPARTIALCUTAREA 0.04 LAYER via3  ;
    ANTENNAPARTIALMETALAREA 77.9658 LAYER met4  ;
    ANTENNAPARTIALMETALSIDEAREA 416.288 LAYER met4  ;
    ANTENNAMODEL OXIDE1 ;
    ANTENNAGATEAREA 1.152 LAYER met4  ;
    ANTENNAMAXAREACAR 70.2921 LAYER met4  ;
    ANTENNAMAXSIDEAREACAR 373.174 LAYER met4  ;
    ANTENNAMAXCUTCAR 0.114063 LAYER via4  ;
    PORT
      LAYER met3 ;
        RECT 0.000000 1565.590000 0.800000 1565.890000 ;
    END
  END io_in[8]
  PIN io_in[7]
    DIRECTION INPUT ;
    USE SIGNAL ;
    ANTENNAPARTIALMETALAREA 0.8544 LAYER met3  ;
    ANTENNAPARTIALMETALSIDEAREA 4.552 LAYER met3  ;
    ANTENNAMODEL OXIDE1 ;
    ANTENNAGATEAREA 0.576 LAYER met3  ;
    ANTENNAMAXAREACAR 83.9663 LAYER met3  ;
    ANTENNAMAXSIDEAREACAR 417.941 LAYER met3  ;
    ANTENNAMAXCUTCAR 0.158681 LAYER via3  ;
    PORT
      LAYER met3 ;
        RECT 0.000000 1800.440000 0.800000 1800.740000 ;
    END
  END io_in[7]
  PIN io_in[6]
    DIRECTION INPUT ;
    USE SIGNAL ;
    ANTENNAPARTIALMETALAREA 3.6004 LAYER met3  ;
    ANTENNAPARTIALMETALSIDEAREA 19.664 LAYER met3  ;
    ANTENNAPARTIALCUTAREA 0.04 LAYER via3  ;
    ANTENNAPARTIALMETALAREA 18.1588 LAYER met4  ;
    ANTENNAPARTIALMETALSIDEAREA 93.192 LAYER met4  ;
    ANTENNAPARTIALCUTAREA 0.64 LAYER via4  ;
    ANTENNADIFFAREA 0.4347 LAYER met5  ;
    ANTENNAPARTIALMETALAREA 7.44 LAYER met5  ;
    ANTENNAPARTIALMETALSIDEAREA 15 LAYER met5  ;
    ANTENNAMODEL OXIDE1 ;
    ANTENNAGATEAREA 0.6477 LAYER met5  ;
    ANTENNAMAXAREACAR 91.3682 LAYER met5  ;
    ANTENNAMAXSIDEAREACAR 409.694 LAYER met5  ;
    PORT
      LAYER met3 ;
        RECT 0.000000 2035.290000 0.800000 2035.590000 ;
    END
  END io_in[6]
  PIN io_in[5]
    DIRECTION INPUT ;
    USE SIGNAL ;
    ANTENNAPARTIALMETALAREA 1.506 LAYER met3  ;
    ANTENNAPARTIALMETALSIDEAREA 8.968 LAYER met3  ;
    ANTENNAMODEL OXIDE1 ;
    ANTENNAGATEAREA 0.315 LAYER met3  ;
    ANTENNAMAXAREACAR 16.4581 LAYER met3  ;
    ANTENNAMAXSIDEAREACAR 83.2032 LAYER met3  ;
    ANTENNAMAXCUTCAR 0.290159 LAYER via3  ;
    PORT
      LAYER met3 ;
        RECT 0.000000 2270.140000 0.800000 2270.440000 ;
    END
  END io_in[5]
  PIN io_in[4]
    DIRECTION INPUT ;
    USE SIGNAL ;
    ANTENNAPARTIALMETALAREA 0.4954 LAYER met3  ;
    ANTENNAPARTIALMETALSIDEAREA 3.104 LAYER met3  ;
    ANTENNAPARTIALCUTAREA 0.04 LAYER via3  ;
    ANTENNAPARTIALMETALAREA 5.9748 LAYER met4  ;
    ANTENNAPARTIALMETALSIDEAREA 32.336 LAYER met4  ;
    ANTENNAMODEL OXIDE1 ;
    ANTENNAGATEAREA 0.213 LAYER met4  ;
    ANTENNAMAXAREACAR 48.3324 LAYER met4  ;
    ANTENNAMAXSIDEAREACAR 250.77 LAYER met4  ;
    ANTENNAMAXCUTCAR 0.616901 LAYER via4  ;
    PORT
      LAYER met3 ;
        RECT 0.000000 2504.990000 0.800000 2505.290000 ;
    END
  END io_in[4]
  PIN io_in[3]
    DIRECTION INPUT ;
    USE SIGNAL ;
    ANTENNAPARTIALMETALAREA 2.607 LAYER met3  ;
    ANTENNAPARTIALMETALSIDEAREA 14.84 LAYER met3  ;
    ANTENNAMODEL OXIDE1 ;
    ANTENNAGATEAREA 0.159 LAYER met3  ;
    ANTENNAMAXAREACAR 90.8544 LAYER met3  ;
    ANTENNAMAXSIDEAREACAR 460.843 LAYER met3  ;
    ANTENNAMAXCUTCAR 0.574843 LAYER via3  ;
    PORT
      LAYER met3 ;
        RECT 0.000000 2739.840000 0.800000 2740.140000 ;
    END
  END io_in[3]
  PIN io_in[2]
    DIRECTION INPUT ;
    USE SIGNAL ;
    ANTENNAPARTIALMETALAREA 1.596 LAYER met3  ;
    ANTENNAPARTIALMETALSIDEAREA 9.448 LAYER met3  ;
    ANTENNAMODEL OXIDE1 ;
    ANTENNAGATEAREA 0.495 LAYER met3  ;
    ANTENNAMAXAREACAR 7.54737 LAYER met3  ;
    ANTENNAMAXSIDEAREACAR 36.0889 LAYER met3  ;
    ANTENNAMAXCUTCAR 0.184646 LAYER via3  ;
    PORT
      LAYER met3 ;
        RECT 0.000000 2974.690000 0.800000 2974.990000 ;
    END
  END io_in[2]
  PIN io_in[1]
    DIRECTION INPUT ;
    USE SIGNAL ;
    ANTENNAPARTIALMETALAREA 0.8334 LAYER met3  ;
    ANTENNAPARTIALMETALSIDEAREA 4.888 LAYER met3  ;
    ANTENNAPARTIALCUTAREA 0.04 LAYER via3  ;
    ANTENNAPARTIALMETALAREA 5.0598 LAYER met4  ;
    ANTENNAPARTIALMETALSIDEAREA 27.456 LAYER met4  ;
    ANTENNAMODEL OXIDE1 ;
    ANTENNAGATEAREA 0.213 LAYER met4  ;
    ANTENNAMAXAREACAR 32.9066 LAYER met4  ;
    ANTENNAMAXSIDEAREACAR 171.939 LAYER met4  ;
    ANTENNAMAXCUTCAR 0.616901 LAYER via4  ;
    PORT
      LAYER met3 ;
        RECT 0.000000 3209.540000 0.800000 3209.840000 ;
    END
  END io_in[1]
  PIN io_in[0]
    DIRECTION INPUT ;
    USE SIGNAL ;
    ANTENNAPARTIALMETALAREA 8.3064 LAYER met3  ;
    ANTENNAPARTIALMETALSIDEAREA 44.296 LAYER met3  ;
    ANTENNAMODEL OXIDE1 ;
    ANTENNAGATEAREA 0.159 LAYER met3  ;
    ANTENNAMAXAREACAR 74.4305 LAYER met3  ;
    ANTENNAMAXSIDEAREACAR 383.27 LAYER met3  ;
    ANTENNAMAXCUTCAR 0.574843 LAYER via3  ;
    PORT
      LAYER met3 ;
        RECT 0.000000 3444.390000 0.800000 3444.690000 ;
    END
  END io_in[0]
  PIN io_out[37]
    DIRECTION OUTPUT ;
    USE SIGNAL ;
    ANTENNADIFFAREA 0.429 LAYER met3  ;
    ANTENNAPARTIALMETALAREA 27.7134 LAYER met3  ;
    ANTENNAPARTIALMETALSIDEAREA 147.8 LAYER met3  ;
    ANTENNAMODEL OXIDE1 ;
    ANTENNAGATEAREA 0.495 LAYER met3  ;
    ANTENNAMAXAREACAR 73.0357 LAYER met3  ;
    ANTENNAMAXSIDEAREACAR 381.533 LAYER met3  ;
    ANTENNAMAXCUTCAR 0.184646 LAYER via3  ;
    PORT
      LAYER met3 ;
        RECT 2887.080000 3361.430000 2887.880000 3361.730000 ;
    END
  END io_out[37]
  PIN io_out[36]
    DIRECTION OUTPUT ;
    USE SIGNAL ;
    ANTENNADIFFAREA 0.429 LAYER met3  ;
    ANTENNAPARTIALMETALAREA 3.0624 LAYER met3  ;
    ANTENNAPARTIALMETALSIDEAREA 16.328 LAYER met3  ;
    ANTENNAMODEL OXIDE1 ;
    ANTENNAGATEAREA 0.495 LAYER met3  ;
    ANTENNAMAXAREACAR 91.9754 LAYER met3  ;
    ANTENNAMAXSIDEAREACAR 459.644 LAYER met3  ;
    ANTENNAMAXCUTCAR 0.184646 LAYER via3  ;
    PORT
      LAYER met3 ;
        RECT 2887.080000 3109.500000 2887.880000 3109.800000 ;
    END
  END io_out[36]
  PIN io_out[35]
    DIRECTION OUTPUT ;
    USE SIGNAL ;
    ANTENNAPARTIALMETALAREA 0.3024 LAYER met3  ;
    ANTENNAPARTIALMETALSIDEAREA 1.608 LAYER met3  ;
    PORT
      LAYER met3 ;
        RECT 2887.080000 2856.960000 2887.880000 2857.260000 ;
    END
  END io_out[35]
  PIN io_out[34]
    DIRECTION OUTPUT ;
    USE SIGNAL ;
    ANTENNAPARTIALMETALAREA 0.4404 LAYER met3  ;
    ANTENNAPARTIALMETALSIDEAREA 2.344 LAYER met3  ;
    PORT
      LAYER met3 ;
        RECT 2887.080000 2605.030000 2887.880000 2605.330000 ;
    END
  END io_out[34]
  PIN io_out[33]
    DIRECTION OUTPUT ;
    USE SIGNAL ;
    ANTENNAPARTIALMETALAREA 0.7714 LAYER met3  ;
    ANTENNAPARTIALMETALSIDEAREA 4.576 LAYER met3  ;
    ANTENNAPARTIALCUTAREA 0.04 LAYER via3  ;
    ANTENNADIFFAREA 0.891 LAYER met4  ;
    ANTENNAPARTIALMETALAREA 272.413 LAYER met4  ;
    ANTENNAPARTIALMETALSIDEAREA 1454.75 LAYER met4  ;
    PORT
      LAYER met3 ;
        RECT 2887.080000 2353.100000 2887.880000 2353.400000 ;
    END
  END io_out[33]
  PIN io_out[32]
    DIRECTION OUTPUT ;
    USE SIGNAL ;
    ANTENNAPARTIALMETALAREA 6.9094 LAYER met3  ;
    ANTENNAPARTIALMETALSIDEAREA 37.312 LAYER met3  ;
    ANTENNAPARTIALCUTAREA 0.04 LAYER via3  ;
    ANTENNAPARTIALMETALAREA 8.9686 LAYER met4  ;
    ANTENNAPARTIALMETALSIDEAREA 44.648 LAYER met4  ;
    ANTENNAPARTIALCUTAREA 0.64 LAYER via4  ;
    ANTENNADIFFAREA 1.0752 LAYER met5  ;
    ANTENNAPARTIALMETALAREA 345.472 LAYER met5  ;
    ANTENNAPARTIALMETALSIDEAREA 522.048 LAYER met5  ;
    PORT
      LAYER met3 ;
        RECT 2887.080000 2101.170000 2887.880000 2101.470000 ;
    END
  END io_out[32]
  PIN io_out[31]
    DIRECTION OUTPUT ;
    USE SIGNAL ;
    ANTENNAPARTIALMETALAREA 1.6186 LAYER met3  ;
    ANTENNAPARTIALMETALSIDEAREA 8.624 LAYER met3  ;
    ANTENNAPARTIALCUTAREA 0.04 LAYER via3  ;
    ANTENNADIFFAREA 1.0752 LAYER met4  ;
    ANTENNAPARTIALMETALAREA 43.9746 LAYER met4  ;
    ANTENNAPARTIALMETALSIDEAREA 235.472 LAYER met4  ;
    PORT
      LAYER met3 ;
        RECT 2887.080000 1849.240000 2887.880000 1849.540000 ;
    END
  END io_out[31]
  PIN io_out[30]
    DIRECTION OUTPUT ;
    USE SIGNAL ;
    ANTENNAPARTIALMETALAREA 2.9104 LAYER met3  ;
    ANTENNAPARTIALMETALSIDEAREA 15.984 LAYER met3  ;
    ANTENNAPARTIALCUTAREA 0.04 LAYER via3  ;
    ANTENNADIFFAREA 1.0752 LAYER met4  ;
    ANTENNAPARTIALMETALAREA 3.0468 LAYER met4  ;
    ANTENNAPARTIALMETALSIDEAREA 16.72 LAYER met4  ;
    PORT
      LAYER met3 ;
        RECT 2887.080000 1596.700000 2887.880000 1597.000000 ;
    END
  END io_out[30]
  PIN io_out[29]
    DIRECTION OUTPUT ;
    USE SIGNAL ;
    ANTENNAPARTIALMETALAREA 0.3946 LAYER met3  ;
    ANTENNAPARTIALMETALSIDEAREA 2.096 LAYER met3  ;
    ANTENNAPARTIALCUTAREA 0.04 LAYER via3  ;
    ANTENNADIFFAREA 1.0752 LAYER met4  ;
    ANTENNAPARTIALMETALAREA 45.8046 LAYER met4  ;
    ANTENNAPARTIALMETALSIDEAREA 245.232 LAYER met4  ;
    PORT
      LAYER met3 ;
        RECT 2887.080000 1344.770000 2887.880000 1345.070000 ;
    END
  END io_out[29]
  PIN io_out[28]
    DIRECTION OUTPUT ;
    USE SIGNAL ;
    ANTENNAPARTIALMETALAREA 0.7606 LAYER met3  ;
    ANTENNAPARTIALMETALSIDEAREA 4.048 LAYER met3  ;
    ANTENNAPARTIALCUTAREA 0.04 LAYER via3  ;
    ANTENNADIFFAREA 1.0752 LAYER met4  ;
    ANTENNAPARTIALMETALAREA 93.9816 LAYER met4  ;
    ANTENNAPARTIALMETALSIDEAREA 502.176 LAYER met4  ;
    PORT
      LAYER met3 ;
        RECT 2887.080000 1092.840000 2887.880000 1093.140000 ;
    END
  END io_out[28]
  PIN io_out[27]
    DIRECTION OUTPUT ;
    USE SIGNAL ;
    ANTENNAPARTIALMETALAREA 0.2116 LAYER met3  ;
    ANTENNAPARTIALMETALSIDEAREA 1.12 LAYER met3  ;
    ANTENNAPARTIALCUTAREA 0.04 LAYER via3  ;
    ANTENNADIFFAREA 1.0752 LAYER met4  ;
    ANTENNAPARTIALMETALAREA 74.7186 LAYER met4  ;
    ANTENNAPARTIALMETALSIDEAREA 399.44 LAYER met4  ;
    PORT
      LAYER met3 ;
        RECT 2887.080000 840.910000 2887.880000 841.210000 ;
    END
  END io_out[27]
  PIN io_out[26]
    DIRECTION OUTPUT ;
    USE SIGNAL ;
    ANTENNAPARTIALMETALAREA 0.5776 LAYER met3  ;
    ANTENNAPARTIALMETALSIDEAREA 3.072 LAYER met3  ;
    ANTENNAPARTIALCUTAREA 0.04 LAYER via3  ;
    ANTENNADIFFAREA 1.782 LAYER met4  ;
    ANTENNAPARTIALMETALAREA 35.5566 LAYER met4  ;
    ANTENNAPARTIALMETALSIDEAREA 190.576 LAYER met4  ;
    PORT
      LAYER met3 ;
        RECT 2887.080000 588.980000 2887.880000 589.280000 ;
    END
  END io_out[26]
  PIN io_out[25]
    DIRECTION OUTPUT ;
    USE SIGNAL ;
    ANTENNAPARTIALMETALAREA 0.2116 LAYER met3  ;
    ANTENNAPARTIALMETALSIDEAREA 1.12 LAYER met3  ;
    ANTENNAPARTIALCUTAREA 0.04 LAYER via3  ;
    ANTENNADIFFAREA 1.782 LAYER met4  ;
    ANTENNAPARTIALMETALAREA 12.5628 LAYER met4  ;
    ANTENNAPARTIALMETALSIDEAREA 67.472 LAYER met4  ;
    PORT
      LAYER met3 ;
        RECT 2887.080000 336.440000 2887.880000 336.740000 ;
    END
  END io_out[25]
  PIN io_out[24]
    DIRECTION OUTPUT ;
    USE SIGNAL ;
    ANTENNAPARTIALMETALAREA 3.2746 LAYER met3  ;
    ANTENNAPARTIALMETALSIDEAREA 17.456 LAYER met3  ;
    ANTENNAPARTIALCUTAREA 0.04 LAYER via3  ;
    ANTENNADIFFAREA 1.3365 LAYER met4  ;
    ANTENNAPARTIALMETALAREA 272.621 LAYER met4  ;
    ANTENNAPARTIALMETALSIDEAREA 1455.39 LAYER met4  ;
    PORT
      LAYER met3 ;
        RECT 2887.080000 84.510000 2887.880000 84.810000 ;
    END
  END io_out[24]
  PIN io_out[23]
    DIRECTION OUTPUT ;
    USE SIGNAL ;
    ANTENNADIFFAREA 0.891 LAYER met2  ;
    ANTENNAPARTIALMETALAREA 13.7517 LAYER met2  ;
    ANTENNAPARTIALMETALSIDEAREA 68.4145 LAYER met2  ;
    PORT
      LAYER met2 ;
        RECT 2776.720000 0.000000 2776.860000 0.485000 ;
    END
  END io_out[23]
  PIN io_out[22]
    DIRECTION OUTPUT ;
    USE SIGNAL ;
    ANTENNADIFFAREA 0.7952 LAYER met2  ;
    ANTENNAPARTIALMETALAREA 2.1111 LAYER met2  ;
    ANTENNAPARTIALMETALSIDEAREA 10.4475 LAYER met2  ;
    PORT
      LAYER met2 ;
        RECT 2443.680000 0.000000 2443.820000 0.485000 ;
    END
  END io_out[22]
  PIN io_out[21]
    DIRECTION OUTPUT ;
    USE SIGNAL ;
    ANTENNADIFFAREA 1.0752 LAYER met2  ;
    ANTENNAPARTIALMETALAREA 70.7861 LAYER met2  ;
    ANTENNAPARTIALMETALSIDEAREA 353.469 LAYER met2  ;
    PORT
      LAYER met2 ;
        RECT 2110.640000 0.000000 2110.780000 0.485000 ;
    END
  END io_out[21]
  PIN io_out[20]
    DIRECTION OUTPUT ;
    USE SIGNAL ;
    ANTENNADIFFAREA 0.4455 LAYER met2  ;
    ANTENNAPARTIALMETALAREA 3.3011 LAYER met2  ;
    ANTENNAPARTIALMETALSIDEAREA 16.3975 LAYER met2  ;
    PORT
      LAYER met2 ;
        RECT 1777.140000 0.000000 1777.280000 0.485000 ;
    END
  END io_out[20]
  PIN io_out[19]
    DIRECTION OUTPUT ;
    USE SIGNAL ;
    ANTENNADIFFAREA 0.4455 LAYER met2  ;
    ANTENNAPARTIALMETALAREA 2.9159 LAYER met2  ;
    ANTENNAPARTIALMETALSIDEAREA 14.3535 LAYER met2  ;
    PORT
      LAYER met2 ;
        RECT 1444.100000 0.000000 1444.240000 0.485000 ;
    END
  END io_out[19]
  PIN io_out[18]
    DIRECTION OUTPUT ;
    USE SIGNAL ;
    ANTENNADIFFAREA 1.0752 LAYER met2  ;
    ANTENNAPARTIALMETALAREA 55.2661 LAYER met2  ;
    ANTENNAPARTIALMETALSIDEAREA 276.105 LAYER met2  ;
    PORT
      LAYER met2 ;
        RECT 1111.060000 0.000000 1111.200000 0.485000 ;
    END
  END io_out[18]
  PIN io_out[17]
    DIRECTION OUTPUT ;
    USE SIGNAL ;
    ANTENNADIFFAREA 1.0752 LAYER met2  ;
    ANTENNAPARTIALMETALAREA 183.822 LAYER met2  ;
    ANTENNAPARTIALMETALSIDEAREA 918.768 LAYER met2  ;
    PORT
      LAYER met2 ;
        RECT 777.560000 0.000000 777.700000 0.485000 ;
    END
  END io_out[17]
  PIN io_out[16]
    DIRECTION OUTPUT ;
    USE SIGNAL ;
    ANTENNAPARTIALMETALAREA 116.352 LAYER met2  ;
    ANTENNAPARTIALMETALSIDEAREA 581.479 LAYER met2  ;
    ANTENNAPARTIALCUTAREA 0.04 LAYER via2  ;
    ANTENNAPARTIALMETALAREA 1.228 LAYER met3  ;
    ANTENNAPARTIALMETALSIDEAREA 7.016 LAYER met3  ;
    ANTENNAPARTIALCUTAREA 0.04 LAYER via3  ;
    ANTENNADIFFAREA 1.0752 LAYER met4  ;
    ANTENNAPARTIALMETALAREA 213.457 LAYER met4  ;
    ANTENNAPARTIALMETALSIDEAREA 1139.38 LAYER met4  ;
    PORT
      LAYER met2 ;
        RECT 444.520000 0.000000 444.660000 0.485000 ;
    END
  END io_out[16]
  PIN io_out[15]
    DIRECTION OUTPUT ;
    USE SIGNAL ;
    ANTENNAPARTIALMETALAREA 1.0164 LAYER met2  ;
    ANTENNAPARTIALMETALSIDEAREA 4.921 LAYER met2  ;
    ANTENNAPARTIALCUTAREA 0.04 LAYER via2  ;
    ANTENNAPARTIALMETALAREA 28.069 LAYER met3  ;
    ANTENNAPARTIALMETALSIDEAREA 150.168 LAYER met3  ;
    ANTENNAPARTIALCUTAREA 0.04 LAYER via3  ;
    ANTENNADIFFAREA 1.0752 LAYER met4  ;
    ANTENNAPARTIALMETALAREA 473.39 LAYER met4  ;
    ANTENNAPARTIALMETALSIDEAREA 2525.22 LAYER met4  ;
    PORT
      LAYER met2 ;
        RECT 111.480000 0.000000 111.620000 0.485000 ;
    END
  END io_out[15]
  PIN io_out[14]
    DIRECTION OUTPUT ;
    USE SIGNAL ;
    ANTENNAPARTIALMETALAREA 5.3944 LAYER met3  ;
    ANTENNAPARTIALMETALSIDEAREA 29.232 LAYER met3  ;
    ANTENNAPARTIALCUTAREA 0.04 LAYER via3  ;
    ANTENNADIFFAREA 1.0752 LAYER met4  ;
    ANTENNAPARTIALMETALAREA 66.7788 LAYER met4  ;
    ANTENNAPARTIALMETALSIDEAREA 356.624 LAYER met4  ;
    PORT
      LAYER met3 ;
        RECT 0.000000 78.410000 0.800000 78.710000 ;
    END
  END io_out[14]
  PIN io_out[13]
    DIRECTION OUTPUT ;
    USE SIGNAL ;
    ANTENNAPARTIALMETALAREA 4.5166 LAYER met3  ;
    ANTENNAPARTIALMETALSIDEAREA 24.08 LAYER met3  ;
    ANTENNAPARTIALCUTAREA 0.04 LAYER via3  ;
    ANTENNADIFFAREA 1.0752 LAYER met4  ;
    ANTENNAPARTIALMETALAREA 528.815 LAYER met4  ;
    ANTENNAPARTIALMETALSIDEAREA 2820.82 LAYER met4  ;
    PORT
      LAYER met3 ;
        RECT 0.000000 313.260000 0.800000 313.560000 ;
    END
  END io_out[13]
  PIN io_out[12]
    DIRECTION OUTPUT ;
    USE SIGNAL ;
    ANTENNADIFFAREA 0.336 LAYER met3  ;
    ANTENNAPARTIALMETALAREA 5.2704 LAYER met3  ;
    ANTENNAPARTIALMETALSIDEAREA 28.104 LAYER met3  ;
    PORT
      LAYER met3 ;
        RECT 0.000000 548.110000 0.800000 548.410000 ;
    END
  END io_out[12]
  PIN io_out[11]
    DIRECTION OUTPUT ;
    USE SIGNAL ;
    ANTENNAPARTIALMETALAREA 2.5654 LAYER met3  ;
    ANTENNAPARTIALMETALSIDEAREA 14.144 LAYER met3  ;
    ANTENNAPARTIALCUTAREA 0.04 LAYER via3  ;
    ANTENNADIFFAREA 1.0752 LAYER met4  ;
    ANTENNAPARTIALMETALAREA 164.738 LAYER met4  ;
    ANTENNAPARTIALMETALSIDEAREA 880.016 LAYER met4  ;
    PORT
      LAYER met3 ;
        RECT 0.000000 782.960000 0.800000 783.260000 ;
    END
  END io_out[11]
  PIN io_out[10]
    DIRECTION OUTPUT ;
    USE SIGNAL ;
    ANTENNAPARTIALMETALAREA 3.6694 LAYER met3  ;
    ANTENNAPARTIALMETALSIDEAREA 20.032 LAYER met3  ;
    ANTENNAPARTIALCUTAREA 0.04 LAYER via3  ;
    ANTENNADIFFAREA 1.0752 LAYER met4  ;
    ANTENNAPARTIALMETALAREA 60.3258 LAYER met4  ;
    ANTENNAPARTIALMETALSIDEAREA 322.208 LAYER met4  ;
    PORT
      LAYER met3 ;
        RECT 0.000000 1017.810000 0.800000 1018.110000 ;
    END
  END io_out[10]
  PIN io_out[9]
    DIRECTION OUTPUT ;
    USE SIGNAL ;
    ANTENNAPARTIALMETALAREA 1.1854 LAYER met3  ;
    ANTENNAPARTIALMETALSIDEAREA 6.784 LAYER met3  ;
    ANTENNAPARTIALCUTAREA 0.04 LAYER via3  ;
    ANTENNADIFFAREA 1.0752 LAYER met4  ;
    ANTENNAPARTIALMETALAREA 14.3928 LAYER met4  ;
    ANTENNAPARTIALMETALSIDEAREA 77.232 LAYER met4  ;
    PORT
      LAYER met3 ;
        RECT 0.000000 1252.660000 0.800000 1252.960000 ;
    END
  END io_out[9]
  PIN io_out[8]
    DIRECTION OUTPUT ;
    USE SIGNAL ;
    ANTENNAPARTIALMETALAREA 5.1376 LAYER met3  ;
    ANTENNAPARTIALMETALSIDEAREA 27.392 LAYER met3  ;
    ANTENNAPARTIALCUTAREA 0.04 LAYER via3  ;
    ANTENNADIFFAREA 0.7952 LAYER met4  ;
    ANTENNAPARTIALMETALAREA 351.575 LAYER met4  ;
    ANTENNAPARTIALMETALSIDEAREA 1875.54 LAYER met4  ;
    PORT
      LAYER met3 ;
        RECT 0.000000 1487.510000 0.800000 1487.810000 ;
    END
  END io_out[8]
  PIN io_out[7]
    DIRECTION OUTPUT ;
    USE SIGNAL ;
    ANTENNAPARTIALMETALAREA 1.7374 LAYER met3  ;
    ANTENNAPARTIALMETALSIDEAREA 9.728 LAYER met3  ;
    ANTENNAPARTIALCUTAREA 0.04 LAYER via3  ;
    ANTENNADIFFAREA 0.7952 LAYER met4  ;
    ANTENNAPARTIALMETALAREA 78.2598 LAYER met4  ;
    ANTENNAPARTIALMETALSIDEAREA 417.856 LAYER met4  ;
    PORT
      LAYER met3 ;
        RECT 0.000000 1722.360000 0.800000 1722.660000 ;
    END
  END io_out[7]
  PIN io_out[6]
    DIRECTION OUTPUT ;
    USE SIGNAL ;
    ANTENNAPARTIALMETALAREA 3.2746 LAYER met3  ;
    ANTENNAPARTIALMETALSIDEAREA 17.456 LAYER met3  ;
    ANTENNAPARTIALCUTAREA 0.04 LAYER via3  ;
    ANTENNADIFFAREA 0.7952 LAYER met4  ;
    ANTENNAPARTIALMETALAREA 223.412 LAYER met4  ;
    ANTENNAPARTIALMETALSIDEAREA 1192 LAYER met4  ;
    PORT
      LAYER met3 ;
        RECT 0.000000 1957.210000 0.800000 1957.510000 ;
    END
  END io_out[6]
  PIN io_out[5]
    DIRECTION OUTPUT ;
    USE SIGNAL ;
    ANTENNAPARTIALMETALAREA 1.6186 LAYER met3  ;
    ANTENNAPARTIALMETALSIDEAREA 8.624 LAYER met3  ;
    ANTENNAPARTIALCUTAREA 0.04 LAYER via3  ;
    ANTENNADIFFAREA 0.7952 LAYER met4  ;
    ANTENNAPARTIALMETALAREA 128.768 LAYER met4  ;
    ANTENNAPARTIALMETALSIDEAREA 687.232 LAYER met4  ;
    PORT
      LAYER met3 ;
        RECT 0.000000 2192.060000 0.800000 2192.360000 ;
    END
  END io_out[5]
  PIN io_out[4]
    DIRECTION OUTPUT ;
    USE SIGNAL ;
    ANTENNADIFFAREA 0.4455 LAYER met3  ;
    ANTENNAPARTIALMETALAREA 4.7184 LAYER met3  ;
    ANTENNAPARTIALMETALSIDEAREA 25.16 LAYER met3  ;
    PORT
      LAYER met3 ;
        RECT 0.000000 2426.910000 0.800000 2427.210000 ;
    END
  END io_out[4]
  PIN io_out[3]
    DIRECTION OUTPUT ;
    USE SIGNAL ;
    ANTENNAPARTIALMETALAREA 3.2746 LAYER met3  ;
    ANTENNAPARTIALMETALSIDEAREA 17.456 LAYER met3  ;
    ANTENNAPARTIALCUTAREA 0.04 LAYER via3  ;
    ANTENNADIFFAREA 0.4455 LAYER met4  ;
    ANTENNAPARTIALMETALAREA 147.848 LAYER met4  ;
    ANTENNAPARTIALMETALSIDEAREA 788.992 LAYER met4  ;
    PORT
      LAYER met3 ;
        RECT 0.000000 2661.760000 0.800000 2662.060000 ;
    END
  END io_out[3]
  PIN io_out[2]
    DIRECTION OUTPUT ;
    USE SIGNAL ;
    ANTENNADIFFAREA 0.3406 LAYER met3  ;
    ANTENNAPARTIALMETALAREA 0.5784 LAYER met3  ;
    ANTENNAPARTIALMETALSIDEAREA 3.08 LAYER met3  ;
    PORT
      LAYER met3 ;
        RECT 0.000000 2896.610000 0.800000 2896.910000 ;
    END
  END io_out[2]
  PIN io_out[1]
    DIRECTION OUTPUT ;
    USE SIGNAL ;
    ANTENNAPARTIALMETALAREA 3.3274 LAYER met3  ;
    ANTENNAPARTIALMETALSIDEAREA 18.688 LAYER met3  ;
    ANTENNAPARTIALCUTAREA 0.04 LAYER via3  ;
    ANTENNADIFFAREA 0.4455 LAYER met4  ;
    ANTENNAPARTIALMETALAREA 4.8768 LAYER met4  ;
    ANTENNAPARTIALMETALSIDEAREA 26.48 LAYER met4  ;
    PORT
      LAYER met3 ;
        RECT 0.000000 3131.460000 0.800000 3131.760000 ;
    END
  END io_out[1]
  PIN io_out[0]
    DIRECTION OUTPUT ;
    USE SIGNAL ;
    ANTENNADIFFAREA 0.4455 LAYER met3  ;
    ANTENNAPARTIALMETALAREA 86.409 LAYER met3  ;
    ANTENNAPARTIALMETALSIDEAREA 462.264 LAYER met3  ;
    PORT
      LAYER met3 ;
        RECT 0.000000 3366.310000 0.800000 3366.610000 ;
    END
  END io_out[0]
  PIN io_oeb[37]
    DIRECTION OUTPUT ;
    USE SIGNAL ;
    ANTENNAPARTIALMETALAREA 108.111 LAYER met3  ;
    ANTENNAPARTIALMETALSIDEAREA 577.056 LAYER met3  ;
    ANTENNAPARTIALCUTAREA 0.04 LAYER via3  ;
    ANTENNADIFFAREA 0.3406 LAYER met4  ;
    ANTENNAPARTIALMETALAREA 4.5588 LAYER met4  ;
    ANTENNAPARTIALMETALSIDEAREA 24.784 LAYER met4  ;
    PORT
      LAYER met3 ;
        RECT 2887.080000 3445.000000 2887.880000 3445.300000 ;
    END
  END io_oeb[37]
  PIN io_oeb[36]
    DIRECTION OUTPUT ;
    USE SIGNAL ;
    ANTENNADIFFAREA 0.4455 LAYER met3  ;
    ANTENNAPARTIALMETALAREA 4.5804 LAYER met3  ;
    ANTENNAPARTIALMETALSIDEAREA 24.424 LAYER met3  ;
    PORT
      LAYER met3 ;
        RECT 2887.080000 3193.070000 2887.880000 3193.370000 ;
    END
  END io_oeb[36]
  PIN io_oeb[35]
    DIRECTION OUTPUT ;
    USE SIGNAL ;
    ANTENNADIFFAREA 0.7952 LAYER met3  ;
    ANTENNAPARTIALMETALAREA 4.0284 LAYER met3  ;
    ANTENNAPARTIALMETALSIDEAREA 21.48 LAYER met3  ;
    PORT
      LAYER met3 ;
        RECT 2887.080000 2941.140000 2887.880000 2941.440000 ;
    END
  END io_oeb[35]
  PIN io_oeb[34]
    DIRECTION OUTPUT ;
    USE SIGNAL ;
    ANTENNAPARTIALMETALAREA 0.2116 LAYER met3  ;
    ANTENNAPARTIALMETALSIDEAREA 1.12 LAYER met3  ;
    ANTENNAPARTIALCUTAREA 0.04 LAYER via3  ;
    ANTENNADIFFAREA 0.7952 LAYER met4  ;
    ANTENNAPARTIALMETALAREA 203.872 LAYER met4  ;
    ANTENNAPARTIALMETALSIDEAREA 1088.26 LAYER met4  ;
    PORT
      LAYER met3 ;
        RECT 2887.080000 2689.210000 2887.880000 2689.510000 ;
    END
  END io_oeb[34]
  PIN io_oeb[33]
    DIRECTION OUTPUT ;
    USE SIGNAL ;
    ANTENNADIFFAREA 0.7952 LAYER met3  ;
    ANTENNAPARTIALMETALAREA 0.7464 LAYER met3  ;
    ANTENNAPARTIALMETALSIDEAREA 3.976 LAYER met3  ;
    PORT
      LAYER met3 ;
        RECT 2887.080000 2437.280000 2887.880000 2437.580000 ;
    END
  END io_oeb[33]
  PIN io_oeb[32]
    DIRECTION OUTPUT ;
    USE SIGNAL ;
    ANTENNADIFFAREA 1.0752 LAYER met3  ;
    ANTENNAPARTIALMETALAREA 0.4404 LAYER met3  ;
    ANTENNAPARTIALMETALSIDEAREA 2.344 LAYER met3  ;
    PORT
      LAYER met3 ;
        RECT 2887.080000 2185.350000 2887.880000 2185.650000 ;
    END
  END io_oeb[32]
  PIN io_oeb[31]
    DIRECTION OUTPUT ;
    USE SIGNAL ;
    ANTENNAPARTIALMETALAREA 0.7606 LAYER met3  ;
    ANTENNAPARTIALMETALSIDEAREA 4.048 LAYER met3  ;
    ANTENNAPARTIALCUTAREA 0.04 LAYER via3  ;
    ANTENNADIFFAREA 1.0752 LAYER met4  ;
    ANTENNAPARTIALMETALAREA 42.6936 LAYER met4  ;
    ANTENNAPARTIALMETALSIDEAREA 228.64 LAYER met4  ;
    PORT
      LAYER met3 ;
        RECT 2887.080000 1932.810000 2887.880000 1933.110000 ;
    END
  END io_oeb[31]
  PIN io_oeb[30]
    DIRECTION OUTPUT ;
    USE SIGNAL ;
    ANTENNAPARTIALMETALAREA 7.5913 LAYER met3  ;
    ANTENNAPARTIALMETALSIDEAREA 40.952 LAYER met3  ;
    ANTENNAPARTIALCUTAREA 0.04 LAYER via3  ;
    ANTENNADIFFAREA 1.0752 LAYER met4  ;
    ANTENNAPARTIALMETALAREA 70.2864 LAYER met4  ;
    ANTENNAPARTIALMETALSIDEAREA 376.272 LAYER met4  ;
    PORT
      LAYER met3 ;
        RECT 2887.080000 1680.880000 2887.880000 1681.180000 ;
    END
  END io_oeb[30]
  PIN io_oeb[29]
    DIRECTION OUTPUT ;
    USE SIGNAL ;
    ANTENNADIFFAREA 1.0752 LAYER met3  ;
    ANTENNAPARTIALMETALAREA 0.3024 LAYER met3  ;
    ANTENNAPARTIALMETALSIDEAREA 1.608 LAYER met3  ;
    PORT
      LAYER met3 ;
        RECT 2887.080000 1428.950000 2887.880000 1429.250000 ;
    END
  END io_oeb[29]
  PIN io_oeb[28]
    DIRECTION OUTPUT ;
    USE SIGNAL ;
    ANTENNAPARTIALMETALAREA 4.0546 LAYER met3  ;
    ANTENNAPARTIALMETALSIDEAREA 21.616 LAYER met3  ;
    ANTENNAPARTIALCUTAREA 0.04 LAYER via3  ;
    ANTENNADIFFAREA 1.0752 LAYER met4  ;
    ANTENNAPARTIALMETALAREA 436.414 LAYER met4  ;
    ANTENNAPARTIALMETALSIDEAREA 2329.42 LAYER met4  ;
    PORT
      LAYER met3 ;
        RECT 2887.080000 1177.020000 2887.880000 1177.320000 ;
    END
  END io_oeb[28]
  PIN io_oeb[27]
    DIRECTION OUTPUT ;
    USE SIGNAL ;
    ANTENNADIFFAREA 1.0752 LAYER met3  ;
    ANTENNAPARTIALMETALAREA 0.3024 LAYER met3  ;
    ANTENNAPARTIALMETALSIDEAREA 1.608 LAYER met3  ;
    PORT
      LAYER met3 ;
        RECT 2887.080000 925.090000 2887.880000 925.390000 ;
    END
  END io_oeb[27]
  PIN io_oeb[26]
    DIRECTION OUTPUT ;
    USE SIGNAL ;
    ANTENNADIFFAREA 1.0752 LAYER met3  ;
    ANTENNAPARTIALMETALAREA 9.2568 LAYER met3  ;
    ANTENNAPARTIALMETALSIDEAREA 50.776 LAYER met3  ;
    PORT
      LAYER met3 ;
        RECT 2887.080000 672.550000 2887.880000 672.850000 ;
    END
  END io_oeb[26]
  PIN io_oeb[25]
    DIRECTION OUTPUT ;
    USE SIGNAL ;
    ANTENNAPARTIALMETALAREA 6.5866 LAYER met3  ;
    ANTENNAPARTIALMETALSIDEAREA 35.12 LAYER met3  ;
    ANTENNAPARTIALCUTAREA 0.04 LAYER via3  ;
    ANTENNADIFFAREA 1.782 LAYER met4  ;
    ANTENNAPARTIALMETALAREA 491.689 LAYER met4  ;
    ANTENNAPARTIALMETALSIDEAREA 2623.28 LAYER met4  ;
    PORT
      LAYER met3 ;
        RECT 2887.080000 420.620000 2887.880000 420.920000 ;
    END
  END io_oeb[25]
  PIN io_oeb[24]
    DIRECTION OUTPUT ;
    USE SIGNAL ;
    ANTENNADIFFAREA 1.0752 LAYER met3  ;
    ANTENNAPARTIALMETALAREA 0.5784 LAYER met3  ;
    ANTENNAPARTIALMETALSIDEAREA 3.08 LAYER met3  ;
    PORT
      LAYER met3 ;
        RECT 2887.080000 168.690000 2887.880000 168.990000 ;
    END
  END io_oeb[24]
  PIN io_oeb[23]
    DIRECTION OUTPUT ;
    USE SIGNAL ;
    ANTENNADIFFAREA 1.782 LAYER met2  ;
    ANTENNAPARTIALMETALAREA 314.68 LAYER met2  ;
    ANTENNAPARTIALMETALSIDEAREA 1573.06 LAYER met2  ;
    PORT
      LAYER met2 ;
        RECT 2887.580000 0.000000 2887.720000 0.485000 ;
    END
  END io_oeb[23]
  PIN io_oeb[22]
    DIRECTION OUTPUT ;
    USE SIGNAL ;
    ANTENNAPARTIALMETALAREA 17.6636 LAYER met2  ;
    ANTENNAPARTIALMETALSIDEAREA 88.039 LAYER met2  ;
    ANTENNAPARTIALCUTAREA 0.04 LAYER via2  ;
    ANTENNAPARTIALMETALAREA 5.6938 LAYER met3  ;
    ANTENNAPARTIALMETALSIDEAREA 31.304 LAYER met3  ;
    ANTENNAPARTIALCUTAREA 0.04 LAYER via3  ;
    ANTENNADIFFAREA 1.782 LAYER met4  ;
    ANTENNAPARTIALMETALAREA 178.67 LAYER met4  ;
    ANTENNAPARTIALMETALSIDEAREA 954.32 LAYER met4  ;
    PORT
      LAYER met2 ;
        RECT 2554.540000 0.000000 2554.680000 0.485000 ;
    END
  END io_oeb[22]
  PIN io_oeb[21]
    DIRECTION OUTPUT ;
    USE SIGNAL ;
    ANTENNADIFFAREA 1.0752 LAYER met2  ;
    ANTENNAPARTIALMETALAREA 3.9841 LAYER met2  ;
    ANTENNAPARTIALMETALSIDEAREA 19.6945 LAYER met2  ;
    PORT
      LAYER met2 ;
        RECT 2221.500000 0.000000 2221.640000 0.485000 ;
    END
  END io_oeb[21]
  PIN io_oeb[20]
    DIRECTION OUTPUT ;
    USE SIGNAL ;
    ANTENNAPARTIALMETALAREA 35.5022 LAYER met2  ;
    ANTENNAPARTIALMETALSIDEAREA 177.114 LAYER met2  ;
    ANTENNAPARTIALCUTAREA 0.04 LAYER via2  ;
    ANTENNAPARTIALMETALAREA 2.953 LAYER met3  ;
    ANTENNAPARTIALMETALSIDEAREA 16.216 LAYER met3  ;
    ANTENNAPARTIALCUTAREA 0.04 LAYER via3  ;
    ANTENNADIFFAREA 1.0752 LAYER met4  ;
    ANTENNAPARTIALMETALAREA 33.0828 LAYER met4  ;
    ANTENNAPARTIALMETALSIDEAREA 176.912 LAYER met4  ;
    PORT
      LAYER met2 ;
        RECT 1888.460000 0.000000 1888.600000 0.485000 ;
    END
  END io_oeb[20]
  PIN io_oeb[19]
    DIRECTION OUTPUT ;
    USE SIGNAL ;
    ANTENNADIFFAREA 1.0752 LAYER met2  ;
    ANTENNAPARTIALMETALAREA 22.3085 LAYER met2  ;
    ANTENNAPARTIALMETALSIDEAREA 111.199 LAYER met2  ;
    PORT
      LAYER met2 ;
        RECT 1554.960000 0.000000 1555.100000 0.485000 ;
    END
  END io_oeb[19]
  PIN io_oeb[18]
    DIRECTION OUTPUT ;
    USE SIGNAL ;
    ANTENNAPARTIALMETALAREA 10.9415 LAYER met2  ;
    ANTENNAPARTIALMETALSIDEAREA 54.4285 LAYER met2  ;
    ANTENNAPARTIALCUTAREA 0.04 LAYER via2  ;
    ANTENNAPARTIALMETALAREA 5.113 LAYER met3  ;
    ANTENNAPARTIALMETALSIDEAREA 27.736 LAYER met3  ;
    ANTENNAPARTIALCUTAREA 0.04 LAYER via3  ;
    ANTENNADIFFAREA 1.0752 LAYER met4  ;
    ANTENNAPARTIALMETALAREA 17.5038 LAYER met4  ;
    ANTENNAPARTIALMETALSIDEAREA 93.824 LAYER met4  ;
    PORT
      LAYER met2 ;
        RECT 1221.920000 0.000000 1222.060000 0.485000 ;
    END
  END io_oeb[18]
  PIN io_oeb[17]
    DIRECTION OUTPUT ;
    USE SIGNAL ;
    ANTENNAPARTIALMETALAREA 133.887 LAYER met2  ;
    ANTENNAPARTIALMETALSIDEAREA 669.039 LAYER met2  ;
    ANTENNAPARTIALCUTAREA 0.04 LAYER via2  ;
    ANTENNAPARTIALMETALAREA 6.058 LAYER met3  ;
    ANTENNAPARTIALMETALSIDEAREA 32.776 LAYER met3  ;
    ANTENNAPARTIALCUTAREA 0.04 LAYER via3  ;
    ANTENNADIFFAREA 1.0752 LAYER met4  ;
    ANTENNAPARTIALMETALAREA 55.9338 LAYER met4  ;
    ANTENNAPARTIALMETALSIDEAREA 298.784 LAYER met4  ;
    PORT
      LAYER met2 ;
        RECT 888.880000 0.000000 889.020000 0.485000 ;
    END
  END io_oeb[17]
  PIN io_oeb[16]
    DIRECTION OUTPUT ;
    USE SIGNAL ;
    ANTENNAPARTIALMETALAREA 63.7838 LAYER met2  ;
    ANTENNAPARTIALMETALSIDEAREA 318.64 LAYER met2  ;
    ANTENNAPARTIALCUTAREA 0.04 LAYER via2  ;
    ANTENNADIFFAREA 1.0752 LAYER met3  ;
    ANTENNAPARTIALMETALAREA 0.8088 LAYER met3  ;
    ANTENNAPARTIALMETALSIDEAREA 4.784 LAYER met3  ;
    PORT
      LAYER met2 ;
        RECT 555.840000 0.000000 555.980000 0.485000 ;
    END
  END io_oeb[16]
  PIN io_oeb[15]
    DIRECTION OUTPUT ;
    USE SIGNAL ;
    ANTENNAPARTIALMETALAREA 13.8024 LAYER met2  ;
    ANTENNAPARTIALMETALSIDEAREA 68.733 LAYER met2  ;
    ANTENNAPARTIALCUTAREA 0.04 LAYER via2  ;
    ANTENNAPARTIALMETALAREA 3.16 LAYER met3  ;
    ANTENNAPARTIALMETALSIDEAREA 17.32 LAYER met3  ;
    ANTENNAPARTIALCUTAREA 0.04 LAYER via3  ;
    ANTENNADIFFAREA 1.782 LAYER met4  ;
    ANTENNAPARTIALMETALAREA 29.0568 LAYER met4  ;
    ANTENNAPARTIALMETALSIDEAREA 155.44 LAYER met4  ;
    PORT
      LAYER met2 ;
        RECT 222.340000 0.000000 222.480000 0.485000 ;
    END
  END io_oeb[15]
  PIN io_oeb[14]
    DIRECTION OUTPUT ;
    USE SIGNAL ;
    ANTENNADIFFAREA 1.782 LAYER met3  ;
    ANTENNAPARTIALMETALAREA 0.1644 LAYER met3  ;
    ANTENNAPARTIALMETALSIDEAREA 0.872 LAYER met3  ;
    PORT
      LAYER met3 ;
        RECT 0.000000 0.330000 0.800000 0.630000 ;
    END
  END io_oeb[14]
  PIN io_oeb[13]
    DIRECTION OUTPUT ;
    USE SIGNAL ;
    ANTENNAPARTIALMETALAREA 0.2116 LAYER met3  ;
    ANTENNAPARTIALMETALSIDEAREA 1.12 LAYER met3  ;
    ANTENNAPARTIALCUTAREA 0.04 LAYER via3  ;
    ANTENNADIFFAREA 1.782 LAYER met4  ;
    ANTENNAPARTIALMETALAREA 5.7918 LAYER met4  ;
    ANTENNAPARTIALMETALSIDEAREA 31.36 LAYER met4  ;
    PORT
      LAYER met3 ;
        RECT 0.000000 235.180000 0.800000 235.480000 ;
    END
  END io_oeb[13]
  PIN io_oeb[12]
    DIRECTION OUTPUT ;
    USE SIGNAL ;
    ANTENNAPARTIALMETALAREA 1.6186 LAYER met3  ;
    ANTENNAPARTIALMETALSIDEAREA 8.624 LAYER met3  ;
    ANTENNAPARTIALCUTAREA 0.04 LAYER via3  ;
    ANTENNADIFFAREA 1.0752 LAYER met4  ;
    ANTENNAPARTIALMETALAREA 402.52 LAYER met4  ;
    ANTENNAPARTIALMETALSIDEAREA 2147.71 LAYER met4  ;
    PORT
      LAYER met3 ;
        RECT 0.000000 470.030000 0.800000 470.330000 ;
    END
  END io_oeb[12]
  PIN io_oeb[11]
    DIRECTION OUTPUT ;
    USE SIGNAL ;
    ANTENNAPARTIALMETALAREA 3.1384 LAYER met3  ;
    ANTENNAPARTIALMETALSIDEAREA 17.2 LAYER met3  ;
    ANTENNAPARTIALCUTAREA 0.04 LAYER via3  ;
    ANTENNADIFFAREA 1.0752 LAYER met4  ;
    ANTENNAPARTIALMETALAREA 196.112 LAYER met4  ;
    ANTENNAPARTIALMETALSIDEAREA 1046.4 LAYER met4  ;
    PORT
      LAYER met3 ;
        RECT 0.000000 704.880000 0.800000 705.180000 ;
    END
  END io_oeb[11]
  PIN io_oeb[10]
    DIRECTION OUTPUT ;
    USE SIGNAL ;
    ANTENNAPARTIALMETALAREA 5.5324 LAYER met3  ;
    ANTENNAPARTIALMETALSIDEAREA 29.968 LAYER met3  ;
    ANTENNAPARTIALCUTAREA 0.04 LAYER via3  ;
    ANTENNADIFFAREA 1.782 LAYER met4  ;
    ANTENNAPARTIALMETALAREA 36.7188 LAYER met4  ;
    ANTENNAPARTIALMETALSIDEAREA 196.304 LAYER met4  ;
    PORT
      LAYER met3 ;
        RECT 0.000000 939.730000 0.800000 940.030000 ;
    END
  END io_oeb[10]
  PIN io_oeb[9]
    DIRECTION OUTPUT ;
    USE SIGNAL ;
    ANTENNAPARTIALMETALAREA 0.2116 LAYER met3  ;
    ANTENNAPARTIALMETALSIDEAREA 1.12 LAYER met3  ;
    ANTENNAPARTIALCUTAREA 0.04 LAYER via3  ;
    ANTENNADIFFAREA 1.0752 LAYER met4  ;
    ANTENNAPARTIALMETALAREA 8.5368 LAYER met4  ;
    ANTENNAPARTIALMETALSIDEAREA 46 LAYER met4  ;
    PORT
      LAYER met3 ;
        RECT 0.000000 1174.580000 0.800000 1174.880000 ;
    END
  END io_oeb[9]
  PIN io_oeb[8]
    DIRECTION OUTPUT ;
    USE SIGNAL ;
    ANTENNADIFFAREA 1.0752 LAYER met3  ;
    ANTENNAPARTIALMETALAREA 0.1644 LAYER met3  ;
    ANTENNAPARTIALMETALSIDEAREA 0.872 LAYER met3  ;
    PORT
      LAYER met3 ;
        RECT 0.000000 1409.430000 0.800000 1409.730000 ;
    END
  END io_oeb[8]
  PIN io_oeb[7]
    DIRECTION OUTPUT ;
    USE SIGNAL ;
    ANTENNAPARTIALMETALAREA 2.9476 LAYER met3  ;
    ANTENNAPARTIALMETALSIDEAREA 15.712 LAYER met3  ;
    ANTENNAPARTIALCUTAREA 0.04 LAYER via3  ;
    ANTENNADIFFAREA 1.0752 LAYER met4  ;
    ANTENNAPARTIALMETALAREA 378.253 LAYER met4  ;
    ANTENNAPARTIALMETALSIDEAREA 2018.29 LAYER met4  ;
    PORT
      LAYER met3 ;
        RECT 0.000000 1644.280000 0.800000 1644.580000 ;
    END
  END io_oeb[7]
  PIN io_oeb[6]
    DIRECTION OUTPUT ;
    USE SIGNAL ;
    ANTENNAPARTIALMETALAREA 3.7384 LAYER met3  ;
    ANTENNAPARTIALMETALSIDEAREA 20.4 LAYER met3  ;
    ANTENNAPARTIALCUTAREA 0.04 LAYER via3  ;
    ANTENNADIFFAREA 1.0752 LAYER met4  ;
    ANTENNAPARTIALMETALAREA 240.47 LAYER met4  ;
    ANTENNAPARTIALMETALSIDEAREA 1282.98 LAYER met4  ;
    PORT
      LAYER met3 ;
        RECT 0.000000 1879.130000 0.800000 1879.430000 ;
    END
  END io_oeb[6]
  PIN io_oeb[5]
    DIRECTION OUTPUT ;
    USE SIGNAL ;
    ANTENNADIFFAREA 1.0752 LAYER met3  ;
    ANTENNAPARTIALMETALAREA 155.485 LAYER met3  ;
    ANTENNAPARTIALMETALSIDEAREA 829.72 LAYER met3  ;
    PORT
      LAYER met3 ;
        RECT 0.000000 2113.980000 0.800000 2114.280000 ;
    END
  END io_oeb[5]
  PIN io_oeb[4]
    DIRECTION OUTPUT ;
    USE SIGNAL ;
    ANTENNAPARTIALMETALAREA 4.1524 LAYER met3  ;
    ANTENNAPARTIALMETALSIDEAREA 22.608 LAYER met3  ;
    ANTENNAPARTIALCUTAREA 0.04 LAYER via3  ;
    ANTENNADIFFAREA 1.0752 LAYER met4  ;
    ANTENNAPARTIALMETALAREA 35.1198 LAYER met4  ;
    ANTENNAPARTIALMETALSIDEAREA 187.776 LAYER met4  ;
    PORT
      LAYER met3 ;
        RECT 0.000000 2348.830000 0.800000 2349.130000 ;
    END
  END io_oeb[4]
  PIN io_oeb[3]
    DIRECTION OUTPUT ;
    USE SIGNAL ;
    ANTENNAPARTIALMETALAREA 3.3934 LAYER met3  ;
    ANTENNAPARTIALMETALSIDEAREA 18.56 LAYER met3  ;
    ANTENNAPARTIALCUTAREA 0.04 LAYER via3  ;
    ANTENNADIFFAREA 1.0752 LAYER met4  ;
    ANTENNAPARTIALMETALAREA 49.2588 LAYER met4  ;
    ANTENNAPARTIALMETALSIDEAREA 263.184 LAYER met4  ;
    PORT
      LAYER met3 ;
        RECT 0.000000 2583.680000 0.800000 2583.980000 ;
    END
  END io_oeb[3]
  PIN io_oeb[2]
    DIRECTION OUTPUT ;
    USE SIGNAL ;
    ANTENNADIFFAREA 1.0752 LAYER met3  ;
    ANTENNAPARTIALMETALAREA 0.1644 LAYER met3  ;
    ANTENNAPARTIALMETALSIDEAREA 0.872 LAYER met3  ;
    PORT
      LAYER met3 ;
        RECT 0.000000 2818.530000 0.800000 2818.830000 ;
    END
  END io_oeb[2]
  PIN io_oeb[1]
    DIRECTION OUTPUT ;
    USE SIGNAL ;
    ANTENNADIFFAREA 0.336 LAYER met3  ;
    ANTENNAPARTIALMETALAREA 0.8964 LAYER met3  ;
    ANTENNAPARTIALMETALSIDEAREA 4.776 LAYER met3  ;
    PORT
      LAYER met3 ;
        RECT 0.000000 3053.380000 0.800000 3053.680000 ;
    END
  END io_oeb[1]
  PIN io_oeb[0]
    DIRECTION OUTPUT ;
    USE SIGNAL ;
    ANTENNADIFFAREA 0.7952 LAYER met3  ;
    ANTENNAPARTIALMETALAREA 0.5784 LAYER met3  ;
    ANTENNAPARTIALMETALSIDEAREA 3.08 LAYER met3  ;
    PORT
      LAYER met3 ;
        RECT 0.000000 3288.230000 0.800000 3288.530000 ;
    END
  END io_oeb[0]
  PIN irq[2]
    DIRECTION OUTPUT ;
    USE SIGNAL ;
    ANTENNAPARTIALMETALAREA 1.8759 LAYER met2  ;
    ANTENNAPARTIALMETALSIDEAREA 9.2715 LAYER met2  ;
    PORT
      LAYER met2 ;
        RECT 0.160000 3445.075000 0.300000 3445.560000 ;
    END
  END irq[2]
  PIN irq[1]
    DIRECTION OUTPUT ;
    USE SIGNAL ;
    ANTENNAPARTIALMETALAREA 1.9235 LAYER met2  ;
    ANTENNAPARTIALMETALSIDEAREA 9.5095 LAYER met2  ;
    PORT
      LAYER met2 ;
        RECT 5.680000 3445.075000 5.820000 3445.560000 ;
    END
  END irq[1]
  PIN irq[0]
    DIRECTION OUTPUT ;
    USE SIGNAL ;
    ANTENNAPARTIALMETALAREA 2.1111 LAYER met2  ;
    ANTENNAPARTIALMETALSIDEAREA 10.4475 LAYER met2  ;
    PORT
      LAYER met2 ;
        RECT 11.660000 3445.075000 11.800000 3445.560000 ;
    END
  END irq[0]
  PIN VSS
    DIRECTION INOUT ;
    USE GROUND ;
    PORT
      LAYER met4 ;
        RECT 2882.840000 3442.200000 2886.200000 3445.560000 ;
    END
    PORT
      LAYER met4 ;
        RECT 2882.840000 0.000000 2886.200000 3.360000 ;
    END
    PORT
      LAYER met4 ;
        RECT 1.680000 3442.200000 5.040000 3445.560000 ;
    END
    PORT
      LAYER met4 ;
        RECT 1.680000 0.000000 5.040000 3.360000 ;
    END
    PORT
      LAYER met5 ;
        RECT 2884.520000 3440.520000 2887.880000 3443.880000 ;
    END
    PORT
      LAYER met5 ;
        RECT 0.000000 3440.520000 3.360000 3443.880000 ;
    END
    PORT
      LAYER met5 ;
        RECT 2884.520000 1.680000 2887.880000 5.040000 ;
    END
    PORT
      LAYER met5 ;
        RECT 0.000000 1.680000 3.360000 5.040000 ;
    END

# P/G power stripe data as pin
    PORT
      LAYER met4 ;
        RECT 2859.200000 86.220000 2862.560000 3359.500000 ;
        RECT 25.360000 86.220000 28.720000 3359.500000 ;
        RECT 2867.760000 1.680000 2871.120000 3443.880000 ;
        RECT 2882.840000 0.000000 2886.200000 3445.560000 ;
        RECT 1.680000 0.000000 5.040000 3445.560000 ;
        RECT 49.040000 1.680000 52.400000 89.580000 ;
        RECT 103.440000 1.680000 106.800000 89.580000 ;
        RECT 76.240000 86.220000 79.600000 97.980000 ;
        RECT 49.040000 86.220000 52.400000 97.980000 ;
        RECT 130.640000 86.220000 134.000000 97.980000 ;
        RECT 103.440000 86.220000 106.800000 97.980000 ;
        RECT 157.840000 1.680000 161.200000 89.580000 ;
        RECT 212.240000 1.680000 215.600000 89.580000 ;
        RECT 157.840000 86.220000 161.200000 97.980000 ;
        RECT 185.040000 86.220000 188.400000 97.980000 ;
        RECT 212.240000 86.220000 215.600000 97.980000 ;
        RECT 239.440000 86.220000 242.800000 97.980000 ;
        RECT 266.640000 1.680000 270.000000 89.580000 ;
        RECT 321.040000 1.680000 324.400000 89.580000 ;
        RECT 266.640000 86.220000 270.000000 97.980000 ;
        RECT 293.840000 86.220000 297.200000 97.980000 ;
        RECT 321.040000 86.220000 324.400000 97.980000 ;
        RECT 348.240000 86.220000 351.600000 97.980000 ;
        RECT 429.840000 1.680000 433.200000 89.580000 ;
        RECT 375.440000 1.680000 378.800000 89.580000 ;
        RECT 375.440000 86.220000 378.800000 97.980000 ;
        RECT 402.640000 86.220000 406.000000 97.980000 ;
        RECT 429.840000 86.220000 433.200000 97.980000 ;
        RECT 457.040000 86.220000 460.400000 97.980000 ;
        RECT 538.640000 1.680000 542.000000 89.580000 ;
        RECT 484.240000 1.680000 487.600000 89.580000 ;
        RECT 484.240000 86.220000 487.600000 97.980000 ;
        RECT 511.440000 86.220000 514.800000 97.980000 ;
        RECT 538.640000 86.220000 542.000000 97.980000 ;
        RECT 565.840000 86.220000 569.200000 97.980000 ;
        RECT 593.040000 1.680000 596.400000 89.580000 ;
        RECT 647.440000 1.680000 650.800000 89.580000 ;
        RECT 593.040000 86.220000 596.400000 97.980000 ;
        RECT 620.240000 86.220000 623.600000 97.980000 ;
        RECT 647.440000 86.220000 650.800000 97.980000 ;
        RECT 674.640000 86.220000 678.000000 97.980000 ;
        RECT 701.840000 1.680000 705.200000 89.580000 ;
        RECT 753.300000 1.680000 756.660000 89.580000 ;
        RECT 701.840000 86.220000 705.200000 97.980000 ;
        RECT 729.040000 86.220000 732.400000 97.980000 ;
        RECT 780.500000 86.220000 783.860000 97.980000 ;
        RECT 753.300000 86.220000 756.660000 97.980000 ;
        RECT 807.700000 1.680000 811.060000 89.580000 ;
        RECT 862.100000 1.680000 865.460000 89.580000 ;
        RECT 834.900000 86.220000 838.260000 97.980000 ;
        RECT 807.700000 86.220000 811.060000 97.980000 ;
        RECT 889.300000 86.220000 892.660000 97.980000 ;
        RECT 862.100000 86.220000 865.460000 97.980000 ;
        RECT 916.500000 1.680000 919.860000 89.580000 ;
        RECT 970.900000 1.680000 974.260000 89.580000 ;
        RECT 943.700000 86.220000 947.060000 97.980000 ;
        RECT 916.500000 86.220000 919.860000 97.980000 ;
        RECT 998.100000 86.220000 1001.460000 97.980000 ;
        RECT 970.900000 86.220000 974.260000 97.980000 ;
        RECT 1025.300000 1.680000 1028.660000 89.580000 ;
        RECT 1079.700000 1.680000 1083.060000 89.580000 ;
        RECT 1025.300000 86.220000 1028.660000 97.980000 ;
        RECT 1052.500000 86.220000 1055.860000 97.980000 ;
        RECT 1079.700000 86.220000 1083.060000 97.980000 ;
        RECT 1106.900000 86.220000 1110.260000 97.980000 ;
        RECT 1134.100000 1.680000 1137.460000 89.580000 ;
        RECT 1188.500000 1.680000 1191.860000 89.580000 ;
        RECT 1134.100000 86.220000 1137.460000 97.980000 ;
        RECT 1161.300000 86.220000 1164.660000 97.980000 ;
        RECT 1188.500000 86.220000 1191.860000 97.980000 ;
        RECT 1215.700000 86.220000 1219.060000 97.980000 ;
        RECT 1242.900000 1.680000 1246.260000 89.580000 ;
        RECT 1297.300000 1.680000 1300.660000 89.580000 ;
        RECT 1242.900000 86.220000 1246.260000 97.980000 ;
        RECT 1270.100000 86.220000 1273.460000 97.980000 ;
        RECT 1297.300000 86.220000 1300.660000 97.980000 ;
        RECT 1324.500000 86.220000 1327.860000 97.980000 ;
        RECT 1406.100000 1.680000 1409.460000 89.580000 ;
        RECT 1351.700000 1.680000 1355.060000 89.580000 ;
        RECT 1351.700000 86.220000 1355.060000 97.980000 ;
        RECT 1378.900000 86.220000 1382.260000 97.980000 ;
        RECT 1406.100000 86.220000 1409.460000 97.980000 ;
        RECT 1433.300000 86.220000 1436.660000 97.980000 ;
        RECT 1511.960000 1.680000 1515.320000 89.580000 ;
        RECT 1457.560000 1.680000 1460.920000 89.580000 ;
        RECT 1457.560000 86.220000 1460.920000 97.980000 ;
        RECT 1484.760000 86.220000 1488.120000 97.980000 ;
        RECT 1511.960000 86.220000 1515.320000 97.980000 ;
        RECT 1539.160000 86.220000 1542.520000 97.980000 ;
        RECT 1620.760000 1.680000 1624.120000 89.580000 ;
        RECT 1566.360000 1.680000 1569.720000 89.580000 ;
        RECT 1566.360000 86.220000 1569.720000 97.980000 ;
        RECT 1593.560000 86.220000 1596.920000 97.980000 ;
        RECT 1647.960000 86.220000 1651.320000 97.980000 ;
        RECT 1620.760000 86.220000 1624.120000 97.980000 ;
        RECT 1729.560000 1.680000 1732.920000 89.580000 ;
        RECT 1675.160000 1.680000 1678.520000 89.580000 ;
        RECT 1702.360000 86.220000 1705.720000 97.980000 ;
        RECT 1675.160000 86.220000 1678.520000 97.980000 ;
        RECT 1756.760000 86.220000 1760.120000 97.980000 ;
        RECT 1729.560000 86.220000 1732.920000 97.980000 ;
        RECT 1838.360000 1.680000 1841.720000 89.580000 ;
        RECT 1783.960000 1.680000 1787.320000 89.580000 ;
        RECT 1811.160000 86.220000 1814.520000 97.980000 ;
        RECT 1783.960000 86.220000 1787.320000 97.980000 ;
        RECT 1865.560000 86.220000 1868.920000 97.980000 ;
        RECT 1838.360000 86.220000 1841.720000 97.980000 ;
        RECT 1947.160000 1.680000 1950.520000 89.580000 ;
        RECT 1892.760000 1.680000 1896.120000 89.580000 ;
        RECT 1892.760000 86.220000 1896.120000 97.980000 ;
        RECT 1919.960000 86.220000 1923.320000 97.980000 ;
        RECT 1947.160000 86.220000 1950.520000 97.980000 ;
        RECT 1974.360000 86.220000 1977.720000 97.980000 ;
        RECT 2055.960000 1.680000 2059.320000 89.580000 ;
        RECT 2001.560000 1.680000 2004.920000 89.580000 ;
        RECT 2001.560000 86.220000 2004.920000 97.980000 ;
        RECT 2028.760000 86.220000 2032.120000 97.980000 ;
        RECT 2083.160000 86.220000 2086.520000 97.980000 ;
        RECT 2055.960000 86.220000 2059.320000 97.980000 ;
        RECT 2161.820000 1.680000 2165.180000 89.580000 ;
        RECT 2110.360000 1.680000 2113.720000 89.580000 ;
        RECT 2137.560000 86.220000 2140.920000 97.980000 ;
        RECT 2110.360000 86.220000 2113.720000 97.980000 ;
        RECT 2189.020000 86.220000 2192.380000 97.980000 ;
        RECT 2161.820000 86.220000 2165.180000 97.980000 ;
        RECT 2270.620000 1.680000 2273.980000 89.580000 ;
        RECT 2216.220000 1.680000 2219.580000 89.580000 ;
        RECT 2243.420000 86.220000 2246.780000 97.980000 ;
        RECT 2216.220000 86.220000 2219.580000 97.980000 ;
        RECT 2297.820000 86.220000 2301.180000 97.980000 ;
        RECT 2270.620000 86.220000 2273.980000 97.980000 ;
        RECT 2733.020000 86.220000 2736.380000 97.980000 ;
        RECT 2379.420000 1.680000 2382.780000 89.580000 ;
        RECT 2325.020000 1.680000 2328.380000 89.580000 ;
        RECT 2325.020000 86.220000 2328.380000 97.980000 ;
        RECT 2352.220000 86.220000 2355.580000 97.980000 ;
        RECT 2379.420000 86.220000 2382.780000 97.980000 ;
        RECT 2406.620000 86.220000 2409.980000 97.980000 ;
        RECT 2488.220000 1.680000 2491.580000 89.580000 ;
        RECT 2433.820000 1.680000 2437.180000 89.580000 ;
        RECT 2433.820000 86.220000 2437.180000 97.980000 ;
        RECT 2461.020000 86.220000 2464.380000 97.980000 ;
        RECT 2488.220000 86.220000 2491.580000 97.980000 ;
        RECT 2515.420000 86.220000 2518.780000 97.980000 ;
        RECT 2597.020000 1.680000 2600.380000 89.580000 ;
        RECT 2542.620000 1.680000 2545.980000 89.580000 ;
        RECT 2542.620000 86.220000 2545.980000 97.980000 ;
        RECT 2569.820000 86.220000 2573.180000 97.980000 ;
        RECT 2597.020000 86.220000 2600.380000 97.980000 ;
        RECT 2624.220000 86.220000 2627.580000 97.980000 ;
        RECT 2705.820000 1.680000 2709.180000 89.580000 ;
        RECT 2651.420000 1.680000 2654.780000 89.580000 ;
        RECT 2651.420000 86.220000 2654.780000 97.980000 ;
        RECT 2678.620000 86.220000 2681.980000 97.980000 ;
        RECT 2705.820000 86.220000 2709.180000 97.980000 ;
        RECT 2841.820000 86.220000 2845.180000 97.980000 ;
        RECT 2814.620000 1.680000 2817.980000 89.580000 ;
        RECT 2760.220000 1.680000 2763.580000 89.580000 ;
        RECT 2787.420000 86.220000 2790.780000 97.980000 ;
        RECT 2760.220000 86.220000 2763.580000 97.980000 ;
        RECT 2814.620000 86.220000 2817.980000 97.980000 ;
        RECT 49.040000 3356.140000 52.400000 3443.880000 ;
        RECT 103.440000 3356.140000 106.800000 3443.880000 ;
        RECT 76.240000 3347.740000 79.600000 3359.500000 ;
        RECT 49.040000 3347.740000 52.400000 3359.500000 ;
        RECT 130.640000 3347.740000 134.000000 3359.500000 ;
        RECT 103.440000 3347.740000 106.800000 3359.500000 ;
        RECT 157.840000 3356.140000 161.200000 3443.880000 ;
        RECT 212.240000 3356.140000 215.600000 3443.880000 ;
        RECT 157.840000 3347.740000 161.200000 3359.500000 ;
        RECT 185.040000 3347.740000 188.400000 3359.500000 ;
        RECT 212.240000 3347.740000 215.600000 3359.500000 ;
        RECT 239.440000 3347.740000 242.800000 3359.500000 ;
        RECT 266.640000 3356.140000 270.000000 3443.880000 ;
        RECT 321.040000 3356.140000 324.400000 3443.880000 ;
        RECT 266.640000 3347.740000 270.000000 3359.500000 ;
        RECT 293.840000 3347.740000 297.200000 3359.500000 ;
        RECT 321.040000 3347.740000 324.400000 3359.500000 ;
        RECT 348.240000 3347.740000 351.600000 3359.500000 ;
        RECT 375.440000 3356.140000 378.800000 3443.880000 ;
        RECT 429.840000 3356.140000 433.200000 3443.880000 ;
        RECT 375.440000 3347.740000 378.800000 3359.500000 ;
        RECT 402.640000 3347.740000 406.000000 3359.500000 ;
        RECT 429.840000 3347.740000 433.200000 3359.500000 ;
        RECT 457.040000 3347.740000 460.400000 3359.500000 ;
        RECT 538.640000 3356.140000 542.000000 3443.880000 ;
        RECT 484.240000 3356.140000 487.600000 3443.880000 ;
        RECT 484.240000 3347.740000 487.600000 3359.500000 ;
        RECT 511.440000 3347.740000 514.800000 3359.500000 ;
        RECT 538.640000 3347.740000 542.000000 3359.500000 ;
        RECT 565.840000 3347.740000 569.200000 3359.500000 ;
        RECT 647.440000 3356.140000 650.800000 3443.880000 ;
        RECT 593.040000 3356.140000 596.400000 3443.880000 ;
        RECT 593.040000 3347.740000 596.400000 3359.500000 ;
        RECT 620.240000 3347.740000 623.600000 3359.500000 ;
        RECT 647.440000 3347.740000 650.800000 3359.500000 ;
        RECT 674.640000 3347.740000 678.000000 3359.500000 ;
        RECT 753.300000 3356.140000 756.660000 3443.880000 ;
        RECT 701.840000 3356.140000 705.200000 3443.880000 ;
        RECT 701.840000 3347.740000 705.200000 3359.500000 ;
        RECT 729.040000 3347.740000 732.400000 3359.500000 ;
        RECT 753.300000 3347.740000 756.660000 3359.500000 ;
        RECT 780.500000 3347.740000 783.860000 3359.500000 ;
        RECT 862.100000 3356.140000 865.460000 3443.880000 ;
        RECT 807.700000 3356.140000 811.060000 3443.880000 ;
        RECT 807.700000 3347.740000 811.060000 3359.500000 ;
        RECT 834.900000 3347.740000 838.260000 3359.500000 ;
        RECT 862.100000 3347.740000 865.460000 3359.500000 ;
        RECT 889.300000 3347.740000 892.660000 3359.500000 ;
        RECT 970.900000 3356.140000 974.260000 3443.880000 ;
        RECT 916.500000 3356.140000 919.860000 3443.880000 ;
        RECT 916.500000 3347.740000 919.860000 3359.500000 ;
        RECT 943.700000 3347.740000 947.060000 3359.500000 ;
        RECT 970.900000 3347.740000 974.260000 3359.500000 ;
        RECT 998.100000 3347.740000 1001.460000 3359.500000 ;
        RECT 1079.700000 3356.140000 1083.060000 3443.880000 ;
        RECT 1025.300000 3356.140000 1028.660000 3443.880000 ;
        RECT 1025.300000 3347.740000 1028.660000 3359.500000 ;
        RECT 1052.500000 3347.740000 1055.860000 3359.500000 ;
        RECT 1079.700000 3347.740000 1083.060000 3359.500000 ;
        RECT 1106.900000 3347.740000 1110.260000 3359.500000 ;
        RECT 1188.500000 3356.140000 1191.860000 3443.880000 ;
        RECT 1134.100000 3356.140000 1137.460000 3443.880000 ;
        RECT 1134.100000 3347.740000 1137.460000 3359.500000 ;
        RECT 1161.300000 3347.740000 1164.660000 3359.500000 ;
        RECT 1188.500000 3347.740000 1191.860000 3359.500000 ;
        RECT 1215.700000 3347.740000 1219.060000 3359.500000 ;
        RECT 1297.300000 3356.140000 1300.660000 3443.880000 ;
        RECT 1242.900000 3356.140000 1246.260000 3443.880000 ;
        RECT 1242.900000 3347.740000 1246.260000 3359.500000 ;
        RECT 1270.100000 3347.740000 1273.460000 3359.500000 ;
        RECT 1297.300000 3347.740000 1300.660000 3359.500000 ;
        RECT 1324.500000 3347.740000 1327.860000 3359.500000 ;
        RECT 1406.100000 3356.140000 1409.460000 3443.880000 ;
        RECT 1351.700000 3356.140000 1355.060000 3443.880000 ;
        RECT 1351.700000 3347.740000 1355.060000 3359.500000 ;
        RECT 1378.900000 3347.740000 1382.260000 3359.500000 ;
        RECT 1406.100000 3347.740000 1409.460000 3359.500000 ;
        RECT 1433.300000 3347.740000 1436.660000 3359.500000 ;
        RECT 1511.960000 3356.140000 1515.320000 3443.880000 ;
        RECT 1457.560000 3356.140000 1460.920000 3443.880000 ;
        RECT 1457.560000 3347.740000 1460.920000 3359.500000 ;
        RECT 1484.760000 3347.740000 1488.120000 3359.500000 ;
        RECT 1511.960000 3347.740000 1515.320000 3359.500000 ;
        RECT 1539.160000 3347.740000 1542.520000 3359.500000 ;
        RECT 1620.760000 3356.140000 1624.120000 3443.880000 ;
        RECT 1566.360000 3356.140000 1569.720000 3443.880000 ;
        RECT 1566.360000 3347.740000 1569.720000 3359.500000 ;
        RECT 1593.560000 3347.740000 1596.920000 3359.500000 ;
        RECT 1620.760000 3347.740000 1624.120000 3359.500000 ;
        RECT 1647.960000 3347.740000 1651.320000 3359.500000 ;
        RECT 1729.560000 3356.140000 1732.920000 3443.880000 ;
        RECT 1675.160000 3356.140000 1678.520000 3443.880000 ;
        RECT 1675.160000 3347.740000 1678.520000 3359.500000 ;
        RECT 1702.360000 3347.740000 1705.720000 3359.500000 ;
        RECT 1729.560000 3347.740000 1732.920000 3359.500000 ;
        RECT 1756.760000 3347.740000 1760.120000 3359.500000 ;
        RECT 1838.360000 3356.140000 1841.720000 3443.880000 ;
        RECT 1783.960000 3356.140000 1787.320000 3443.880000 ;
        RECT 1783.960000 3347.740000 1787.320000 3359.500000 ;
        RECT 1811.160000 3347.740000 1814.520000 3359.500000 ;
        RECT 1838.360000 3347.740000 1841.720000 3359.500000 ;
        RECT 1865.560000 3347.740000 1868.920000 3359.500000 ;
        RECT 1947.160000 3356.140000 1950.520000 3443.880000 ;
        RECT 1892.760000 3356.140000 1896.120000 3443.880000 ;
        RECT 1892.760000 3347.740000 1896.120000 3359.500000 ;
        RECT 1919.960000 3347.740000 1923.320000 3359.500000 ;
        RECT 1947.160000 3347.740000 1950.520000 3359.500000 ;
        RECT 1974.360000 3347.740000 1977.720000 3359.500000 ;
        RECT 2055.960000 3356.140000 2059.320000 3443.880000 ;
        RECT 2001.560000 3356.140000 2004.920000 3443.880000 ;
        RECT 2001.560000 3347.740000 2004.920000 3359.500000 ;
        RECT 2028.760000 3347.740000 2032.120000 3359.500000 ;
        RECT 2055.960000 3347.740000 2059.320000 3359.500000 ;
        RECT 2083.160000 3347.740000 2086.520000 3359.500000 ;
        RECT 2161.820000 3356.140000 2165.180000 3443.880000 ;
        RECT 2110.360000 3356.140000 2113.720000 3443.880000 ;
        RECT 2110.360000 3347.740000 2113.720000 3359.500000 ;
        RECT 2137.560000 3347.740000 2140.920000 3359.500000 ;
        RECT 2161.820000 3347.740000 2165.180000 3359.500000 ;
        RECT 2189.020000 3347.740000 2192.380000 3359.500000 ;
        RECT 2270.620000 3356.140000 2273.980000 3443.880000 ;
        RECT 2216.220000 3356.140000 2219.580000 3443.880000 ;
        RECT 2216.220000 3347.740000 2219.580000 3359.500000 ;
        RECT 2243.420000 3347.740000 2246.780000 3359.500000 ;
        RECT 2270.620000 3347.740000 2273.980000 3359.500000 ;
        RECT 2297.820000 3347.740000 2301.180000 3359.500000 ;
        RECT 2733.020000 3347.740000 2736.380000 3359.500000 ;
        RECT 2379.420000 3356.140000 2382.780000 3443.880000 ;
        RECT 2325.020000 3356.140000 2328.380000 3443.880000 ;
        RECT 2325.020000 3347.740000 2328.380000 3359.500000 ;
        RECT 2352.220000 3347.740000 2355.580000 3359.500000 ;
        RECT 2379.420000 3347.740000 2382.780000 3359.500000 ;
        RECT 2406.620000 3347.740000 2409.980000 3359.500000 ;
        RECT 2488.220000 3356.140000 2491.580000 3443.880000 ;
        RECT 2433.820000 3356.140000 2437.180000 3443.880000 ;
        RECT 2433.820000 3347.740000 2437.180000 3359.500000 ;
        RECT 2461.020000 3347.740000 2464.380000 3359.500000 ;
        RECT 2488.220000 3347.740000 2491.580000 3359.500000 ;
        RECT 2515.420000 3347.740000 2518.780000 3359.500000 ;
        RECT 2597.020000 3356.140000 2600.380000 3443.880000 ;
        RECT 2542.620000 3356.140000 2545.980000 3443.880000 ;
        RECT 2542.620000 3347.740000 2545.980000 3359.500000 ;
        RECT 2569.820000 3347.740000 2573.180000 3359.500000 ;
        RECT 2597.020000 3347.740000 2600.380000 3359.500000 ;
        RECT 2624.220000 3347.740000 2627.580000 3359.500000 ;
        RECT 2705.820000 3356.140000 2709.180000 3443.880000 ;
        RECT 2651.420000 3356.140000 2654.780000 3443.880000 ;
        RECT 2651.420000 3347.740000 2654.780000 3359.500000 ;
        RECT 2678.620000 3347.740000 2681.980000 3359.500000 ;
        RECT 2705.820000 3347.740000 2709.180000 3359.500000 ;
        RECT 2841.820000 3347.740000 2845.180000 3359.500000 ;
        RECT 2814.620000 3356.140000 2817.980000 3443.880000 ;
        RECT 2760.220000 3356.140000 2763.580000 3443.880000 ;
        RECT 2787.420000 3347.740000 2790.780000 3359.500000 ;
        RECT 2760.220000 3347.740000 2763.580000 3359.500000 ;
        RECT 2814.620000 3347.740000 2817.980000 3359.500000 ;
      LAYER met5 ;
        RECT 0.000000 1.680000 2887.880000 5.040000 ;
        RECT 1.680000 24.820000 2886.200000 28.180000 ;
        RECT 1.680000 79.220000 2886.200000 82.580000 ;
        RECT 25.360000 86.220000 2862.560000 89.580000 ;
        RECT 25.360000 860.620000 37.120000 863.980000 ;
        RECT 1.680000 860.620000 28.720000 863.980000 ;
        RECT 1.680000 109.900000 28.720000 113.260000 ;
        RECT 25.360000 109.900000 37.120000 113.260000 ;
        RECT 25.360000 137.100000 37.120000 140.460000 ;
        RECT 1.680000 164.300000 28.720000 167.660000 ;
        RECT 25.360000 164.300000 37.120000 167.660000 ;
        RECT 25.360000 191.500000 37.120000 194.860000 ;
        RECT 1.680000 218.700000 28.720000 222.060000 ;
        RECT 25.360000 218.700000 37.120000 222.060000 ;
        RECT 25.360000 245.900000 37.120000 249.260000 ;
        RECT 1.680000 273.100000 28.720000 276.460000 ;
        RECT 25.360000 273.100000 37.120000 276.460000 ;
        RECT 1.680000 305.740000 28.720000 309.100000 ;
        RECT 25.360000 305.740000 37.120000 309.100000 ;
        RECT 25.360000 332.940000 37.120000 336.300000 ;
        RECT 1.680000 360.140000 28.720000 363.500000 ;
        RECT 25.360000 360.140000 37.120000 363.500000 ;
        RECT 25.360000 387.340000 37.120000 390.700000 ;
        RECT 1.680000 414.540000 28.720000 417.900000 ;
        RECT 25.360000 414.540000 37.120000 417.900000 ;
        RECT 25.360000 441.740000 37.120000 445.100000 ;
        RECT 1.680000 468.940000 28.720000 472.300000 ;
        RECT 25.360000 468.940000 37.120000 472.300000 ;
        RECT 1.680000 501.580000 28.720000 504.940000 ;
        RECT 25.360000 501.580000 37.120000 504.940000 ;
        RECT 25.360000 528.780000 37.120000 532.140000 ;
        RECT 1.680000 555.980000 28.720000 559.340000 ;
        RECT 25.360000 555.980000 37.120000 559.340000 ;
        RECT 25.360000 583.180000 37.120000 586.540000 ;
        RECT 1.680000 610.380000 28.720000 613.740000 ;
        RECT 25.360000 610.380000 37.120000 613.740000 ;
        RECT 25.360000 637.580000 37.120000 640.940000 ;
        RECT 25.360000 751.820000 37.120000 755.180000 ;
        RECT 1.680000 751.820000 28.720000 755.180000 ;
        RECT 25.360000 697.420000 37.120000 700.780000 ;
        RECT 1.680000 697.420000 28.720000 700.780000 ;
        RECT 1.680000 664.780000 28.720000 668.140000 ;
        RECT 25.360000 664.780000 37.120000 668.140000 ;
        RECT 25.360000 724.620000 37.120000 727.980000 ;
        RECT 1.680000 806.220000 28.720000 809.580000 ;
        RECT 25.360000 806.220000 37.120000 809.580000 ;
        RECT 25.360000 779.020000 37.120000 782.380000 ;
        RECT 25.360000 833.420000 37.120000 836.780000 ;
        RECT 1.680000 915.020000 28.720000 918.380000 ;
        RECT 25.360000 915.020000 37.120000 918.380000 ;
        RECT 25.360000 887.820000 37.120000 891.180000 ;
        RECT 25.360000 942.220000 37.120000 945.580000 ;
        RECT 1.680000 969.420000 28.720000 972.780000 ;
        RECT 25.360000 969.420000 37.120000 972.780000 ;
        RECT 25.360000 996.620000 37.120000 999.980000 ;
        RECT 1.680000 1023.820000 28.720000 1027.180000 ;
        RECT 25.360000 1023.820000 37.120000 1027.180000 ;
        RECT 25.360000 1051.020000 37.120000 1054.380000 ;
        RECT 1.680000 1078.220000 28.720000 1081.580000 ;
        RECT 25.360000 1078.220000 37.120000 1081.580000 ;
        RECT 25.360000 1105.420000 37.120000 1108.780000 ;
        RECT 1.680000 1132.620000 28.720000 1135.980000 ;
        RECT 25.360000 1132.620000 37.120000 1135.980000 ;
        RECT 25.360000 1159.820000 37.120000 1163.180000 ;
        RECT 1.680000 1187.020000 28.720000 1190.380000 ;
        RECT 25.360000 1187.020000 37.120000 1190.380000 ;
        RECT 25.360000 1214.220000 37.120000 1217.580000 ;
        RECT 1.680000 1241.420000 28.720000 1244.780000 ;
        RECT 25.360000 1241.420000 37.120000 1244.780000 ;
        RECT 25.360000 1268.620000 37.120000 1271.980000 ;
        RECT 1.680000 1295.820000 28.720000 1299.180000 ;
        RECT 25.360000 1295.820000 37.120000 1299.180000 ;
        RECT 25.360000 1323.020000 37.120000 1326.380000 ;
        RECT 1.680000 1350.220000 28.720000 1353.580000 ;
        RECT 25.360000 1350.220000 37.120000 1353.580000 ;
        RECT 25.360000 1377.420000 37.120000 1380.780000 ;
        RECT 1.680000 1404.620000 28.720000 1407.980000 ;
        RECT 25.360000 1404.620000 37.120000 1407.980000 ;
        RECT 25.360000 1431.820000 37.120000 1435.180000 ;
        RECT 1.680000 1459.020000 28.720000 1462.380000 ;
        RECT 25.360000 1459.020000 37.120000 1462.380000 ;
        RECT 25.360000 1486.220000 37.120000 1489.580000 ;
        RECT 1.680000 1513.420000 28.720000 1516.780000 ;
        RECT 25.360000 1513.420000 37.120000 1516.780000 ;
        RECT 25.360000 1540.620000 37.120000 1543.980000 ;
        RECT 1.680000 1567.820000 28.720000 1571.180000 ;
        RECT 25.360000 1567.820000 37.120000 1571.180000 ;
        RECT 25.360000 1595.020000 37.120000 1598.380000 ;
        RECT 1.680000 1622.220000 28.720000 1625.580000 ;
        RECT 25.360000 1622.220000 37.120000 1625.580000 ;
        RECT 25.360000 1649.420000 37.120000 1652.780000 ;
        RECT 1.680000 1676.620000 28.720000 1679.980000 ;
        RECT 25.360000 1676.620000 37.120000 1679.980000 ;
        RECT 25.360000 1703.820000 37.120000 1707.180000 ;
        RECT 2850.800000 860.620000 2862.560000 863.980000 ;
        RECT 2859.200000 860.620000 2886.200000 863.980000 ;
        RECT 2859.200000 109.900000 2886.200000 113.260000 ;
        RECT 2850.800000 109.900000 2862.560000 113.260000 ;
        RECT 2850.800000 137.100000 2862.560000 140.460000 ;
        RECT 2859.200000 164.300000 2886.200000 167.660000 ;
        RECT 2850.800000 164.300000 2862.560000 167.660000 ;
        RECT 2850.800000 191.500000 2862.560000 194.860000 ;
        RECT 2859.200000 218.700000 2886.200000 222.060000 ;
        RECT 2850.800000 218.700000 2862.560000 222.060000 ;
        RECT 2850.800000 245.900000 2862.560000 249.260000 ;
        RECT 2859.200000 273.100000 2886.200000 276.460000 ;
        RECT 2850.800000 273.100000 2862.560000 276.460000 ;
        RECT 2859.200000 305.740000 2886.200000 309.100000 ;
        RECT 2850.800000 305.740000 2862.560000 309.100000 ;
        RECT 2850.800000 332.940000 2862.560000 336.300000 ;
        RECT 2859.200000 360.140000 2886.200000 363.500000 ;
        RECT 2850.800000 360.140000 2862.560000 363.500000 ;
        RECT 2850.800000 387.340000 2862.560000 390.700000 ;
        RECT 2859.200000 414.540000 2886.200000 417.900000 ;
        RECT 2850.800000 414.540000 2862.560000 417.900000 ;
        RECT 2850.800000 441.740000 2862.560000 445.100000 ;
        RECT 2859.200000 468.940000 2886.200000 472.300000 ;
        RECT 2850.800000 468.940000 2862.560000 472.300000 ;
        RECT 2859.200000 501.580000 2886.200000 504.940000 ;
        RECT 2850.800000 501.580000 2862.560000 504.940000 ;
        RECT 2850.800000 528.780000 2862.560000 532.140000 ;
        RECT 2859.200000 555.980000 2886.200000 559.340000 ;
        RECT 2850.800000 555.980000 2862.560000 559.340000 ;
        RECT 2850.800000 583.180000 2862.560000 586.540000 ;
        RECT 2859.200000 610.380000 2886.200000 613.740000 ;
        RECT 2850.800000 610.380000 2862.560000 613.740000 ;
        RECT 2850.800000 637.580000 2862.560000 640.940000 ;
        RECT 2850.800000 751.820000 2862.560000 755.180000 ;
        RECT 2859.200000 751.820000 2886.200000 755.180000 ;
        RECT 2859.200000 697.420000 2886.200000 700.780000 ;
        RECT 2850.800000 697.420000 2862.560000 700.780000 ;
        RECT 2859.200000 664.780000 2886.200000 668.140000 ;
        RECT 2850.800000 664.780000 2862.560000 668.140000 ;
        RECT 2850.800000 724.620000 2862.560000 727.980000 ;
        RECT 2859.200000 806.220000 2886.200000 809.580000 ;
        RECT 2850.800000 806.220000 2862.560000 809.580000 ;
        RECT 2850.800000 779.020000 2862.560000 782.380000 ;
        RECT 2850.800000 833.420000 2862.560000 836.780000 ;
        RECT 2859.200000 915.020000 2886.200000 918.380000 ;
        RECT 2850.800000 915.020000 2862.560000 918.380000 ;
        RECT 2850.800000 887.820000 2862.560000 891.180000 ;
        RECT 2850.800000 942.220000 2862.560000 945.580000 ;
        RECT 2859.200000 969.420000 2886.200000 972.780000 ;
        RECT 2850.800000 969.420000 2862.560000 972.780000 ;
        RECT 2850.800000 996.620000 2862.560000 999.980000 ;
        RECT 2859.200000 1023.820000 2886.200000 1027.180000 ;
        RECT 2850.800000 1023.820000 2862.560000 1027.180000 ;
        RECT 2850.800000 1051.020000 2862.560000 1054.380000 ;
        RECT 2859.200000 1078.220000 2886.200000 1081.580000 ;
        RECT 2850.800000 1078.220000 2862.560000 1081.580000 ;
        RECT 2850.800000 1105.420000 2862.560000 1108.780000 ;
        RECT 2859.200000 1132.620000 2886.200000 1135.980000 ;
        RECT 2850.800000 1132.620000 2862.560000 1135.980000 ;
        RECT 2850.800000 1159.820000 2862.560000 1163.180000 ;
        RECT 2859.200000 1187.020000 2886.200000 1190.380000 ;
        RECT 2850.800000 1187.020000 2862.560000 1190.380000 ;
        RECT 2850.800000 1214.220000 2862.560000 1217.580000 ;
        RECT 2859.200000 1241.420000 2886.200000 1244.780000 ;
        RECT 2850.800000 1241.420000 2862.560000 1244.780000 ;
        RECT 2850.800000 1268.620000 2862.560000 1271.980000 ;
        RECT 2859.200000 1295.820000 2886.200000 1299.180000 ;
        RECT 2850.800000 1295.820000 2862.560000 1299.180000 ;
        RECT 2850.800000 1323.020000 2862.560000 1326.380000 ;
        RECT 2859.200000 1350.220000 2886.200000 1353.580000 ;
        RECT 2850.800000 1350.220000 2862.560000 1353.580000 ;
        RECT 2850.800000 1377.420000 2862.560000 1380.780000 ;
        RECT 2859.200000 1404.620000 2886.200000 1407.980000 ;
        RECT 2850.800000 1404.620000 2862.560000 1407.980000 ;
        RECT 2850.800000 1431.820000 2862.560000 1435.180000 ;
        RECT 2859.200000 1459.020000 2886.200000 1462.380000 ;
        RECT 2850.800000 1459.020000 2862.560000 1462.380000 ;
        RECT 2850.800000 1486.220000 2862.560000 1489.580000 ;
        RECT 2859.200000 1513.420000 2886.200000 1516.780000 ;
        RECT 2850.800000 1513.420000 2862.560000 1516.780000 ;
        RECT 2850.800000 1540.620000 2862.560000 1543.980000 ;
        RECT 2859.200000 1567.820000 2886.200000 1571.180000 ;
        RECT 2850.800000 1567.820000 2862.560000 1571.180000 ;
        RECT 2850.800000 1595.020000 2862.560000 1598.380000 ;
        RECT 2859.200000 1622.220000 2886.200000 1625.580000 ;
        RECT 2850.800000 1622.220000 2862.560000 1625.580000 ;
        RECT 2850.800000 1649.420000 2862.560000 1652.780000 ;
        RECT 2859.200000 1676.620000 2886.200000 1679.980000 ;
        RECT 2850.800000 1676.620000 2862.560000 1679.980000 ;
        RECT 2850.800000 1703.820000 2862.560000 1707.180000 ;
        RECT 1.680000 3364.700000 2886.200000 3368.060000 ;
        RECT 25.360000 3356.140000 2862.560000 3359.500000 ;
        RECT 0.000000 3440.520000 2887.880000 3443.880000 ;
        RECT 1.680000 3419.100000 2886.200000 3422.460000 ;
        RECT 1.680000 1736.460000 28.720000 1739.820000 ;
        RECT 25.360000 1736.460000 37.120000 1739.820000 ;
        RECT 25.360000 1763.660000 37.120000 1767.020000 ;
        RECT 1.680000 1790.860000 28.720000 1794.220000 ;
        RECT 25.360000 1790.860000 37.120000 1794.220000 ;
        RECT 25.360000 1818.060000 37.120000 1821.420000 ;
        RECT 1.680000 1845.260000 28.720000 1848.620000 ;
        RECT 25.360000 1845.260000 37.120000 1848.620000 ;
        RECT 25.360000 1872.460000 37.120000 1875.820000 ;
        RECT 1.680000 1899.660000 28.720000 1903.020000 ;
        RECT 25.360000 1899.660000 37.120000 1903.020000 ;
        RECT 1.680000 1932.300000 28.720000 1935.660000 ;
        RECT 25.360000 1932.300000 37.120000 1935.660000 ;
        RECT 25.360000 1959.500000 37.120000 1962.860000 ;
        RECT 1.680000 1986.700000 28.720000 1990.060000 ;
        RECT 25.360000 1986.700000 37.120000 1990.060000 ;
        RECT 25.360000 2013.900000 37.120000 2017.260000 ;
        RECT 1.680000 2041.100000 28.720000 2044.460000 ;
        RECT 25.360000 2041.100000 37.120000 2044.460000 ;
        RECT 25.360000 2068.300000 37.120000 2071.660000 ;
        RECT 1.680000 2095.500000 28.720000 2098.860000 ;
        RECT 25.360000 2095.500000 37.120000 2098.860000 ;
        RECT 1.680000 2128.140000 28.720000 2131.500000 ;
        RECT 25.360000 2128.140000 37.120000 2131.500000 ;
        RECT 25.360000 2155.340000 37.120000 2158.700000 ;
        RECT 1.680000 2182.540000 28.720000 2185.900000 ;
        RECT 25.360000 2182.540000 37.120000 2185.900000 ;
        RECT 25.360000 2209.740000 37.120000 2213.100000 ;
        RECT 1.680000 2236.940000 28.720000 2240.300000 ;
        RECT 25.360000 2236.940000 37.120000 2240.300000 ;
        RECT 25.360000 2264.140000 37.120000 2267.500000 ;
        RECT 1.680000 2291.340000 28.720000 2294.700000 ;
        RECT 25.360000 2291.340000 37.120000 2294.700000 ;
        RECT 1.680000 2323.980000 28.720000 2327.340000 ;
        RECT 25.360000 2323.980000 37.120000 2327.340000 ;
        RECT 25.360000 2351.180000 37.120000 2354.540000 ;
        RECT 1.680000 2378.380000 28.720000 2381.740000 ;
        RECT 25.360000 2378.380000 37.120000 2381.740000 ;
        RECT 25.360000 2405.580000 37.120000 2408.940000 ;
        RECT 1.680000 2432.780000 28.720000 2436.140000 ;
        RECT 25.360000 2432.780000 37.120000 2436.140000 ;
        RECT 25.360000 2459.980000 37.120000 2463.340000 ;
        RECT 1.680000 2487.180000 28.720000 2490.540000 ;
        RECT 25.360000 2487.180000 37.120000 2490.540000 ;
        RECT 25.360000 2514.380000 37.120000 2517.740000 ;
        RECT 1.680000 2541.580000 28.720000 2544.940000 ;
        RECT 25.360000 2541.580000 37.120000 2544.940000 ;
        RECT 25.360000 2568.780000 37.120000 2572.140000 ;
        RECT 1.680000 2595.980000 28.720000 2599.340000 ;
        RECT 25.360000 2595.980000 37.120000 2599.340000 ;
        RECT 25.360000 2623.180000 37.120000 2626.540000 ;
        RECT 1.680000 2650.380000 28.720000 2653.740000 ;
        RECT 25.360000 2650.380000 37.120000 2653.740000 ;
        RECT 25.360000 2677.580000 37.120000 2680.940000 ;
        RECT 1.680000 2704.780000 28.720000 2708.140000 ;
        RECT 25.360000 2704.780000 37.120000 2708.140000 ;
        RECT 25.360000 2731.980000 37.120000 2735.340000 ;
        RECT 1.680000 2759.180000 28.720000 2762.540000 ;
        RECT 25.360000 2759.180000 37.120000 2762.540000 ;
        RECT 25.360000 2786.380000 37.120000 2789.740000 ;
        RECT 1.680000 2813.580000 28.720000 2816.940000 ;
        RECT 25.360000 2813.580000 37.120000 2816.940000 ;
        RECT 25.360000 2840.780000 37.120000 2844.140000 ;
        RECT 1.680000 2867.980000 28.720000 2871.340000 ;
        RECT 25.360000 2867.980000 37.120000 2871.340000 ;
        RECT 25.360000 2895.180000 37.120000 2898.540000 ;
        RECT 1.680000 2922.380000 28.720000 2925.740000 ;
        RECT 25.360000 2922.380000 37.120000 2925.740000 ;
        RECT 25.360000 2949.580000 37.120000 2952.940000 ;
        RECT 1.680000 2976.780000 28.720000 2980.140000 ;
        RECT 25.360000 2976.780000 37.120000 2980.140000 ;
        RECT 25.360000 3003.980000 37.120000 3007.340000 ;
        RECT 1.680000 3031.180000 28.720000 3034.540000 ;
        RECT 25.360000 3031.180000 37.120000 3034.540000 ;
        RECT 25.360000 3058.380000 37.120000 3061.740000 ;
        RECT 1.680000 3085.580000 28.720000 3088.940000 ;
        RECT 25.360000 3085.580000 37.120000 3088.940000 ;
        RECT 25.360000 3112.780000 37.120000 3116.140000 ;
        RECT 1.680000 3139.980000 28.720000 3143.340000 ;
        RECT 25.360000 3139.980000 37.120000 3143.340000 ;
        RECT 25.360000 3167.180000 37.120000 3170.540000 ;
        RECT 1.680000 3194.380000 28.720000 3197.740000 ;
        RECT 25.360000 3194.380000 37.120000 3197.740000 ;
        RECT 25.360000 3221.580000 37.120000 3224.940000 ;
        RECT 1.680000 3248.780000 28.720000 3252.140000 ;
        RECT 25.360000 3248.780000 37.120000 3252.140000 ;
        RECT 25.360000 3275.980000 37.120000 3279.340000 ;
        RECT 1.680000 3303.180000 28.720000 3306.540000 ;
        RECT 25.360000 3303.180000 37.120000 3306.540000 ;
        RECT 25.360000 3330.380000 37.120000 3333.740000 ;
        RECT 2859.200000 1736.460000 2886.200000 1739.820000 ;
        RECT 2850.800000 1736.460000 2862.560000 1739.820000 ;
        RECT 2850.800000 1763.660000 2862.560000 1767.020000 ;
        RECT 2859.200000 1790.860000 2886.200000 1794.220000 ;
        RECT 2850.800000 1790.860000 2862.560000 1794.220000 ;
        RECT 2850.800000 1818.060000 2862.560000 1821.420000 ;
        RECT 2859.200000 1845.260000 2886.200000 1848.620000 ;
        RECT 2850.800000 1845.260000 2862.560000 1848.620000 ;
        RECT 2850.800000 1872.460000 2862.560000 1875.820000 ;
        RECT 2859.200000 1899.660000 2886.200000 1903.020000 ;
        RECT 2850.800000 1899.660000 2862.560000 1903.020000 ;
        RECT 2859.200000 1932.300000 2886.200000 1935.660000 ;
        RECT 2850.800000 1932.300000 2862.560000 1935.660000 ;
        RECT 2850.800000 1959.500000 2862.560000 1962.860000 ;
        RECT 2859.200000 1986.700000 2886.200000 1990.060000 ;
        RECT 2850.800000 1986.700000 2862.560000 1990.060000 ;
        RECT 2850.800000 2013.900000 2862.560000 2017.260000 ;
        RECT 2859.200000 2041.100000 2886.200000 2044.460000 ;
        RECT 2850.800000 2041.100000 2862.560000 2044.460000 ;
        RECT 2850.800000 2068.300000 2862.560000 2071.660000 ;
        RECT 2859.200000 2095.500000 2886.200000 2098.860000 ;
        RECT 2850.800000 2095.500000 2862.560000 2098.860000 ;
        RECT 2859.200000 2128.140000 2886.200000 2131.500000 ;
        RECT 2850.800000 2128.140000 2862.560000 2131.500000 ;
        RECT 2850.800000 2155.340000 2862.560000 2158.700000 ;
        RECT 2859.200000 2182.540000 2886.200000 2185.900000 ;
        RECT 2850.800000 2182.540000 2862.560000 2185.900000 ;
        RECT 2850.800000 2209.740000 2862.560000 2213.100000 ;
        RECT 2859.200000 2236.940000 2886.200000 2240.300000 ;
        RECT 2850.800000 2236.940000 2862.560000 2240.300000 ;
        RECT 2850.800000 2264.140000 2862.560000 2267.500000 ;
        RECT 2859.200000 2291.340000 2886.200000 2294.700000 ;
        RECT 2850.800000 2291.340000 2862.560000 2294.700000 ;
        RECT 2859.200000 2323.980000 2886.200000 2327.340000 ;
        RECT 2850.800000 2323.980000 2862.560000 2327.340000 ;
        RECT 2850.800000 2351.180000 2862.560000 2354.540000 ;
        RECT 2859.200000 2378.380000 2886.200000 2381.740000 ;
        RECT 2850.800000 2378.380000 2862.560000 2381.740000 ;
        RECT 2850.800000 2405.580000 2862.560000 2408.940000 ;
        RECT 2859.200000 2432.780000 2886.200000 2436.140000 ;
        RECT 2850.800000 2432.780000 2862.560000 2436.140000 ;
        RECT 2850.800000 2459.980000 2862.560000 2463.340000 ;
        RECT 2859.200000 2487.180000 2886.200000 2490.540000 ;
        RECT 2850.800000 2487.180000 2862.560000 2490.540000 ;
        RECT 2850.800000 2514.380000 2862.560000 2517.740000 ;
        RECT 2859.200000 2541.580000 2886.200000 2544.940000 ;
        RECT 2850.800000 2541.580000 2862.560000 2544.940000 ;
        RECT 2850.800000 2568.780000 2862.560000 2572.140000 ;
        RECT 2859.200000 2595.980000 2886.200000 2599.340000 ;
        RECT 2850.800000 2595.980000 2862.560000 2599.340000 ;
        RECT 2850.800000 2623.180000 2862.560000 2626.540000 ;
        RECT 2859.200000 2650.380000 2886.200000 2653.740000 ;
        RECT 2850.800000 2650.380000 2862.560000 2653.740000 ;
        RECT 2850.800000 2677.580000 2862.560000 2680.940000 ;
        RECT 2859.200000 2704.780000 2886.200000 2708.140000 ;
        RECT 2850.800000 2704.780000 2862.560000 2708.140000 ;
        RECT 2850.800000 2731.980000 2862.560000 2735.340000 ;
        RECT 2859.200000 2759.180000 2886.200000 2762.540000 ;
        RECT 2850.800000 2759.180000 2862.560000 2762.540000 ;
        RECT 2850.800000 2786.380000 2862.560000 2789.740000 ;
        RECT 2859.200000 2813.580000 2886.200000 2816.940000 ;
        RECT 2850.800000 2813.580000 2862.560000 2816.940000 ;
        RECT 2850.800000 2840.780000 2862.560000 2844.140000 ;
        RECT 2859.200000 2867.980000 2886.200000 2871.340000 ;
        RECT 2850.800000 2867.980000 2862.560000 2871.340000 ;
        RECT 2850.800000 2895.180000 2862.560000 2898.540000 ;
        RECT 2859.200000 2922.380000 2886.200000 2925.740000 ;
        RECT 2850.800000 2922.380000 2862.560000 2925.740000 ;
        RECT 2850.800000 2949.580000 2862.560000 2952.940000 ;
        RECT 2859.200000 2976.780000 2886.200000 2980.140000 ;
        RECT 2850.800000 2976.780000 2862.560000 2980.140000 ;
        RECT 2850.800000 3003.980000 2862.560000 3007.340000 ;
        RECT 2859.200000 3031.180000 2886.200000 3034.540000 ;
        RECT 2850.800000 3031.180000 2862.560000 3034.540000 ;
        RECT 2850.800000 3058.380000 2862.560000 3061.740000 ;
        RECT 2859.200000 3085.580000 2886.200000 3088.940000 ;
        RECT 2850.800000 3085.580000 2862.560000 3088.940000 ;
        RECT 2850.800000 3112.780000 2862.560000 3116.140000 ;
        RECT 2859.200000 3139.980000 2886.200000 3143.340000 ;
        RECT 2850.800000 3139.980000 2862.560000 3143.340000 ;
        RECT 2850.800000 3167.180000 2862.560000 3170.540000 ;
        RECT 2859.200000 3194.380000 2886.200000 3197.740000 ;
        RECT 2850.800000 3194.380000 2862.560000 3197.740000 ;
        RECT 2850.800000 3221.580000 2862.560000 3224.940000 ;
        RECT 2859.200000 3248.780000 2886.200000 3252.140000 ;
        RECT 2850.800000 3248.780000 2862.560000 3252.140000 ;
        RECT 2850.800000 3275.980000 2862.560000 3279.340000 ;
        RECT 2859.200000 3303.180000 2886.200000 3306.540000 ;
        RECT 2850.800000 3303.180000 2862.560000 3306.540000 ;
        RECT 2850.800000 3330.380000 2862.560000 3333.740000 ;
    END
# end of P/G power stripe data as pin

  END VSS
  PIN VDD
    DIRECTION INOUT ;
    USE POWER ;
    PORT
      LAYER met4 ;
        RECT 2877.800000 3442.200000 2881.160000 3445.560000 ;
    END
    PORT
      LAYER met4 ;
        RECT 2877.800000 0.000000 2881.160000 3.360000 ;
    END
    PORT
      LAYER met4 ;
        RECT 6.720000 3442.200000 10.080000 3445.560000 ;
    END
    PORT
      LAYER met4 ;
        RECT 6.720000 0.000000 10.080000 3.360000 ;
    END
    PORT
      LAYER met5 ;
        RECT 2884.520000 3435.480000 2887.880000 3438.840000 ;
    END
    PORT
      LAYER met5 ;
        RECT 0.000000 3435.480000 3.360000 3438.840000 ;
    END
    PORT
      LAYER met5 ;
        RECT 2884.520000 6.720000 2887.880000 10.080000 ;
    END
    PORT
      LAYER met5 ;
        RECT 0.000000 6.720000 3.360000 10.080000 ;
    END

# P/G power stripe data as pin
    PORT
      LAYER met4 ;
        RECT 2854.160000 91.260000 2857.520000 3354.460000 ;
        RECT 30.400000 91.260000 33.760000 3354.460000 ;
        RECT 20.320000 6.720000 23.680000 3438.840000 ;
        RECT 2877.800000 0.000000 2881.160000 3445.560000 ;
        RECT 6.720000 0.000000 10.080000 3445.560000 ;
        RECT 579.440000 6.720000 582.800000 94.620000 ;
        RECT 579.440000 91.260000 582.800000 97.980000 ;
        RECT 35.440000 6.720000 38.800000 94.620000 ;
        RECT 144.240000 6.720000 147.600000 94.620000 ;
        RECT 89.840000 6.720000 93.200000 94.620000 ;
        RECT 89.840000 91.260000 93.200000 97.980000 ;
        RECT 62.640000 91.260000 66.000000 97.980000 ;
        RECT 144.240000 91.260000 147.600000 97.980000 ;
        RECT 117.040000 91.260000 120.400000 97.980000 ;
        RECT 253.040000 6.720000 256.400000 94.620000 ;
        RECT 198.640000 6.720000 202.000000 94.620000 ;
        RECT 198.640000 91.260000 202.000000 97.980000 ;
        RECT 171.440000 91.260000 174.800000 97.980000 ;
        RECT 253.040000 91.260000 256.400000 97.980000 ;
        RECT 225.840000 91.260000 229.200000 97.980000 ;
        RECT 361.840000 6.720000 365.200000 94.620000 ;
        RECT 307.440000 6.720000 310.800000 94.620000 ;
        RECT 307.440000 91.260000 310.800000 97.980000 ;
        RECT 280.240000 91.260000 283.600000 97.980000 ;
        RECT 361.840000 91.260000 365.200000 97.980000 ;
        RECT 334.640000 91.260000 338.000000 97.980000 ;
        RECT 470.640000 6.720000 474.000000 94.620000 ;
        RECT 416.240000 6.720000 419.600000 94.620000 ;
        RECT 416.240000 91.260000 419.600000 97.980000 ;
        RECT 389.040000 91.260000 392.400000 97.980000 ;
        RECT 470.640000 91.260000 474.000000 97.980000 ;
        RECT 443.440000 91.260000 446.800000 97.980000 ;
        RECT 525.040000 6.720000 528.400000 94.620000 ;
        RECT 525.040000 91.260000 528.400000 97.980000 ;
        RECT 497.840000 91.260000 501.200000 97.980000 ;
        RECT 552.240000 91.260000 555.600000 97.980000 ;
        RECT 1011.700000 6.720000 1015.060000 94.620000 ;
        RECT 1011.700000 91.260000 1015.060000 97.980000 ;
        RECT 688.240000 6.720000 691.600000 94.620000 ;
        RECT 688.240000 91.260000 691.600000 97.980000 ;
        RECT 633.840000 6.720000 637.200000 94.620000 ;
        RECT 633.840000 91.260000 637.200000 97.980000 ;
        RECT 606.640000 91.260000 610.000000 97.980000 ;
        RECT 661.040000 91.260000 664.400000 97.980000 ;
        RECT 794.100000 6.720000 797.460000 94.620000 ;
        RECT 739.700000 6.720000 743.060000 94.620000 ;
        RECT 715.440000 91.260000 718.800000 97.980000 ;
        RECT 794.100000 91.260000 797.460000 97.980000 ;
        RECT 766.900000 91.260000 770.260000 97.980000 ;
        RECT 902.900000 6.720000 906.260000 94.620000 ;
        RECT 902.900000 91.260000 906.260000 97.980000 ;
        RECT 848.500000 6.720000 851.860000 94.620000 ;
        RECT 848.500000 91.260000 851.860000 97.980000 ;
        RECT 821.300000 91.260000 824.660000 97.980000 ;
        RECT 875.700000 91.260000 879.060000 97.980000 ;
        RECT 957.300000 6.720000 960.660000 94.620000 ;
        RECT 957.300000 91.260000 960.660000 97.980000 ;
        RECT 930.100000 91.260000 933.460000 97.980000 ;
        RECT 984.500000 91.260000 987.860000 97.980000 ;
        RECT 1120.500000 6.720000 1123.860000 94.620000 ;
        RECT 1120.500000 91.260000 1123.860000 97.980000 ;
        RECT 1066.100000 6.720000 1069.460000 94.620000 ;
        RECT 1066.100000 91.260000 1069.460000 97.980000 ;
        RECT 1038.900000 91.260000 1042.260000 97.980000 ;
        RECT 1093.300000 91.260000 1096.660000 97.980000 ;
        RECT 1174.900000 6.720000 1178.260000 94.620000 ;
        RECT 1147.700000 91.260000 1151.060000 97.980000 ;
        RECT 1202.100000 91.260000 1205.460000 97.980000 ;
        RECT 1174.900000 91.260000 1178.260000 97.980000 ;
        RECT 1283.700000 6.720000 1287.060000 94.620000 ;
        RECT 1229.300000 6.720000 1232.660000 94.620000 ;
        RECT 1256.500000 91.260000 1259.860000 97.980000 ;
        RECT 1229.300000 91.260000 1232.660000 97.980000 ;
        RECT 1310.900000 91.260000 1314.260000 97.980000 ;
        RECT 1283.700000 91.260000 1287.060000 97.980000 ;
        RECT 1392.500000 6.720000 1395.860000 94.620000 ;
        RECT 1338.100000 6.720000 1341.460000 94.620000 ;
        RECT 1365.300000 91.260000 1368.660000 97.980000 ;
        RECT 1338.100000 91.260000 1341.460000 97.980000 ;
        RECT 1419.700000 91.260000 1423.060000 97.980000 ;
        RECT 1392.500000 91.260000 1395.860000 97.980000 ;
        RECT 1498.360000 6.720000 1501.720000 94.620000 ;
        RECT 1443.960000 6.720000 1447.320000 94.620000 ;
        RECT 1471.160000 91.260000 1474.520000 97.980000 ;
        RECT 1525.560000 91.260000 1528.920000 97.980000 ;
        RECT 1498.360000 91.260000 1501.720000 97.980000 ;
        RECT 1607.160000 6.720000 1610.520000 94.620000 ;
        RECT 1552.760000 6.720000 1556.120000 94.620000 ;
        RECT 1579.960000 91.260000 1583.320000 97.980000 ;
        RECT 1552.760000 91.260000 1556.120000 97.980000 ;
        RECT 1634.360000 91.260000 1637.720000 97.980000 ;
        RECT 1607.160000 91.260000 1610.520000 97.980000 ;
        RECT 1715.960000 6.720000 1719.320000 94.620000 ;
        RECT 1661.560000 6.720000 1664.920000 94.620000 ;
        RECT 1688.760000 91.260000 1692.120000 97.980000 ;
        RECT 1661.560000 91.260000 1664.920000 97.980000 ;
        RECT 1743.160000 91.260000 1746.520000 97.980000 ;
        RECT 1715.960000 91.260000 1719.320000 97.980000 ;
        RECT 1824.760000 6.720000 1828.120000 94.620000 ;
        RECT 1770.360000 6.720000 1773.720000 94.620000 ;
        RECT 1797.560000 91.260000 1800.920000 97.980000 ;
        RECT 1770.360000 91.260000 1773.720000 97.980000 ;
        RECT 1851.960000 91.260000 1855.320000 97.980000 ;
        RECT 1824.760000 91.260000 1828.120000 97.980000 ;
        RECT 1933.560000 6.720000 1936.920000 94.620000 ;
        RECT 1879.160000 6.720000 1882.520000 94.620000 ;
        RECT 1906.360000 91.260000 1909.720000 97.980000 ;
        RECT 1879.160000 91.260000 1882.520000 97.980000 ;
        RECT 1960.760000 91.260000 1964.120000 97.980000 ;
        RECT 1933.560000 91.260000 1936.920000 97.980000 ;
        RECT 2042.360000 6.720000 2045.720000 94.620000 ;
        RECT 1987.960000 6.720000 1991.320000 94.620000 ;
        RECT 2015.160000 91.260000 2018.520000 97.980000 ;
        RECT 1987.960000 91.260000 1991.320000 97.980000 ;
        RECT 2069.560000 91.260000 2072.920000 97.980000 ;
        RECT 2042.360000 91.260000 2045.720000 97.980000 ;
        RECT 2148.220000 6.720000 2151.580000 94.620000 ;
        RECT 2096.760000 6.720000 2100.120000 94.620000 ;
        RECT 2123.960000 91.260000 2127.320000 97.980000 ;
        RECT 2096.760000 91.260000 2100.120000 97.980000 ;
        RECT 2175.420000 91.260000 2178.780000 97.980000 ;
        RECT 2257.020000 6.720000 2260.380000 94.620000 ;
        RECT 2202.620000 6.720000 2205.980000 94.620000 ;
        RECT 2229.820000 91.260000 2233.180000 97.980000 ;
        RECT 2202.620000 91.260000 2205.980000 97.980000 ;
        RECT 2284.220000 91.260000 2287.580000 97.980000 ;
        RECT 2257.020000 91.260000 2260.380000 97.980000 ;
        RECT 2365.820000 6.720000 2369.180000 94.620000 ;
        RECT 2311.420000 6.720000 2314.780000 94.620000 ;
        RECT 2338.620000 91.260000 2341.980000 97.980000 ;
        RECT 2311.420000 91.260000 2314.780000 97.980000 ;
        RECT 2393.020000 91.260000 2396.380000 97.980000 ;
        RECT 2365.820000 91.260000 2369.180000 97.980000 ;
        RECT 2474.620000 6.720000 2477.980000 94.620000 ;
        RECT 2420.220000 6.720000 2423.580000 94.620000 ;
        RECT 2447.420000 91.260000 2450.780000 97.980000 ;
        RECT 2420.220000 91.260000 2423.580000 97.980000 ;
        RECT 2501.820000 91.260000 2505.180000 97.980000 ;
        RECT 2474.620000 91.260000 2477.980000 97.980000 ;
        RECT 2583.420000 6.720000 2586.780000 94.620000 ;
        RECT 2529.020000 6.720000 2532.380000 94.620000 ;
        RECT 2556.220000 91.260000 2559.580000 97.980000 ;
        RECT 2529.020000 91.260000 2532.380000 97.980000 ;
        RECT 2610.620000 91.260000 2613.980000 97.980000 ;
        RECT 2583.420000 91.260000 2586.780000 97.980000 ;
        RECT 2692.220000 6.720000 2695.580000 94.620000 ;
        RECT 2637.820000 6.720000 2641.180000 94.620000 ;
        RECT 2665.020000 91.260000 2668.380000 97.980000 ;
        RECT 2637.820000 91.260000 2641.180000 97.980000 ;
        RECT 2692.220000 91.260000 2695.580000 97.980000 ;
        RECT 2719.420000 91.260000 2722.780000 97.980000 ;
        RECT 2801.020000 6.720000 2804.380000 94.620000 ;
        RECT 2746.620000 6.720000 2749.980000 94.620000 ;
        RECT 2746.620000 91.260000 2749.980000 97.980000 ;
        RECT 2773.820000 91.260000 2777.180000 97.980000 ;
        RECT 2801.020000 91.260000 2804.380000 97.980000 ;
        RECT 2828.220000 91.260000 2831.580000 97.980000 ;
        RECT 2854.160000 6.720000 2857.520000 94.620000 ;
        RECT 579.440000 3351.100000 582.800000 3438.840000 ;
        RECT 579.440000 3347.740000 582.800000 3354.460000 ;
        RECT 35.440000 3351.100000 38.800000 3438.840000 ;
        RECT 144.240000 3351.100000 147.600000 3438.840000 ;
        RECT 89.840000 3351.100000 93.200000 3438.840000 ;
        RECT 89.840000 3347.740000 93.200000 3354.460000 ;
        RECT 62.640000 3347.740000 66.000000 3354.460000 ;
        RECT 144.240000 3347.740000 147.600000 3354.460000 ;
        RECT 117.040000 3347.740000 120.400000 3354.460000 ;
        RECT 253.040000 3351.100000 256.400000 3438.840000 ;
        RECT 198.640000 3351.100000 202.000000 3438.840000 ;
        RECT 198.640000 3347.740000 202.000000 3354.460000 ;
        RECT 171.440000 3347.740000 174.800000 3354.460000 ;
        RECT 253.040000 3347.740000 256.400000 3354.460000 ;
        RECT 225.840000 3347.740000 229.200000 3354.460000 ;
        RECT 361.840000 3351.100000 365.200000 3438.840000 ;
        RECT 307.440000 3351.100000 310.800000 3438.840000 ;
        RECT 307.440000 3347.740000 310.800000 3354.460000 ;
        RECT 280.240000 3347.740000 283.600000 3354.460000 ;
        RECT 361.840000 3347.740000 365.200000 3354.460000 ;
        RECT 334.640000 3347.740000 338.000000 3354.460000 ;
        RECT 470.640000 3351.100000 474.000000 3438.840000 ;
        RECT 416.240000 3351.100000 419.600000 3438.840000 ;
        RECT 416.240000 3347.740000 419.600000 3354.460000 ;
        RECT 389.040000 3347.740000 392.400000 3354.460000 ;
        RECT 470.640000 3347.740000 474.000000 3354.460000 ;
        RECT 443.440000 3347.740000 446.800000 3354.460000 ;
        RECT 525.040000 3351.100000 528.400000 3438.840000 ;
        RECT 525.040000 3347.740000 528.400000 3354.460000 ;
        RECT 497.840000 3347.740000 501.200000 3354.460000 ;
        RECT 552.240000 3347.740000 555.600000 3354.460000 ;
        RECT 1011.700000 3351.100000 1015.060000 3438.840000 ;
        RECT 1011.700000 3347.740000 1015.060000 3354.460000 ;
        RECT 688.240000 3351.100000 691.600000 3438.840000 ;
        RECT 688.240000 3347.740000 691.600000 3354.460000 ;
        RECT 633.840000 3351.100000 637.200000 3438.840000 ;
        RECT 633.840000 3347.740000 637.200000 3354.460000 ;
        RECT 606.640000 3347.740000 610.000000 3354.460000 ;
        RECT 661.040000 3347.740000 664.400000 3354.460000 ;
        RECT 794.100000 3351.100000 797.460000 3438.840000 ;
        RECT 739.700000 3351.100000 743.060000 3438.840000 ;
        RECT 715.440000 3347.740000 718.800000 3354.460000 ;
        RECT 794.100000 3347.740000 797.460000 3354.460000 ;
        RECT 766.900000 3347.740000 770.260000 3354.460000 ;
        RECT 902.900000 3351.100000 906.260000 3438.840000 ;
        RECT 902.900000 3347.740000 906.260000 3354.460000 ;
        RECT 848.500000 3351.100000 851.860000 3438.840000 ;
        RECT 848.500000 3347.740000 851.860000 3354.460000 ;
        RECT 821.300000 3347.740000 824.660000 3354.460000 ;
        RECT 875.700000 3347.740000 879.060000 3354.460000 ;
        RECT 957.300000 3351.100000 960.660000 3438.840000 ;
        RECT 957.300000 3347.740000 960.660000 3354.460000 ;
        RECT 930.100000 3347.740000 933.460000 3354.460000 ;
        RECT 984.500000 3347.740000 987.860000 3354.460000 ;
        RECT 1120.500000 3351.100000 1123.860000 3438.840000 ;
        RECT 1120.500000 3347.740000 1123.860000 3354.460000 ;
        RECT 1066.100000 3351.100000 1069.460000 3438.840000 ;
        RECT 1066.100000 3347.740000 1069.460000 3354.460000 ;
        RECT 1038.900000 3347.740000 1042.260000 3354.460000 ;
        RECT 1093.300000 3347.740000 1096.660000 3354.460000 ;
        RECT 1174.900000 3351.100000 1178.260000 3438.840000 ;
        RECT 1147.700000 3347.740000 1151.060000 3354.460000 ;
        RECT 1202.100000 3347.740000 1205.460000 3354.460000 ;
        RECT 1174.900000 3347.740000 1178.260000 3354.460000 ;
        RECT 1283.700000 3351.100000 1287.060000 3438.840000 ;
        RECT 1229.300000 3351.100000 1232.660000 3438.840000 ;
        RECT 1256.500000 3347.740000 1259.860000 3354.460000 ;
        RECT 1229.300000 3347.740000 1232.660000 3354.460000 ;
        RECT 1310.900000 3347.740000 1314.260000 3354.460000 ;
        RECT 1283.700000 3347.740000 1287.060000 3354.460000 ;
        RECT 1392.500000 3351.100000 1395.860000 3438.840000 ;
        RECT 1338.100000 3351.100000 1341.460000 3438.840000 ;
        RECT 1365.300000 3347.740000 1368.660000 3354.460000 ;
        RECT 1338.100000 3347.740000 1341.460000 3354.460000 ;
        RECT 1419.700000 3347.740000 1423.060000 3354.460000 ;
        RECT 1392.500000 3347.740000 1395.860000 3354.460000 ;
        RECT 1498.360000 3351.100000 1501.720000 3438.840000 ;
        RECT 1443.960000 3351.100000 1447.320000 3438.840000 ;
        RECT 1471.160000 3347.740000 1474.520000 3354.460000 ;
        RECT 1525.560000 3347.740000 1528.920000 3354.460000 ;
        RECT 1498.360000 3347.740000 1501.720000 3354.460000 ;
        RECT 1607.160000 3351.100000 1610.520000 3438.840000 ;
        RECT 1552.760000 3351.100000 1556.120000 3438.840000 ;
        RECT 1579.960000 3347.740000 1583.320000 3354.460000 ;
        RECT 1552.760000 3347.740000 1556.120000 3354.460000 ;
        RECT 1634.360000 3347.740000 1637.720000 3354.460000 ;
        RECT 1607.160000 3347.740000 1610.520000 3354.460000 ;
        RECT 1715.960000 3351.100000 1719.320000 3438.840000 ;
        RECT 1661.560000 3351.100000 1664.920000 3438.840000 ;
        RECT 1688.760000 3347.740000 1692.120000 3354.460000 ;
        RECT 1661.560000 3347.740000 1664.920000 3354.460000 ;
        RECT 1743.160000 3347.740000 1746.520000 3354.460000 ;
        RECT 1715.960000 3347.740000 1719.320000 3354.460000 ;
        RECT 1824.760000 3351.100000 1828.120000 3438.840000 ;
        RECT 1770.360000 3351.100000 1773.720000 3438.840000 ;
        RECT 1797.560000 3347.740000 1800.920000 3354.460000 ;
        RECT 1770.360000 3347.740000 1773.720000 3354.460000 ;
        RECT 1851.960000 3347.740000 1855.320000 3354.460000 ;
        RECT 1824.760000 3347.740000 1828.120000 3354.460000 ;
        RECT 1933.560000 3351.100000 1936.920000 3438.840000 ;
        RECT 1879.160000 3351.100000 1882.520000 3438.840000 ;
        RECT 1906.360000 3347.740000 1909.720000 3354.460000 ;
        RECT 1879.160000 3347.740000 1882.520000 3354.460000 ;
        RECT 1960.760000 3347.740000 1964.120000 3354.460000 ;
        RECT 1933.560000 3347.740000 1936.920000 3354.460000 ;
        RECT 2042.360000 3351.100000 2045.720000 3438.840000 ;
        RECT 1987.960000 3351.100000 1991.320000 3438.840000 ;
        RECT 2015.160000 3347.740000 2018.520000 3354.460000 ;
        RECT 1987.960000 3347.740000 1991.320000 3354.460000 ;
        RECT 2069.560000 3347.740000 2072.920000 3354.460000 ;
        RECT 2042.360000 3347.740000 2045.720000 3354.460000 ;
        RECT 2148.220000 3351.100000 2151.580000 3438.840000 ;
        RECT 2096.760000 3351.100000 2100.120000 3438.840000 ;
        RECT 2123.960000 3347.740000 2127.320000 3354.460000 ;
        RECT 2096.760000 3347.740000 2100.120000 3354.460000 ;
        RECT 2175.420000 3347.740000 2178.780000 3354.460000 ;
        RECT 2257.020000 3351.100000 2260.380000 3438.840000 ;
        RECT 2202.620000 3351.100000 2205.980000 3438.840000 ;
        RECT 2229.820000 3347.740000 2233.180000 3354.460000 ;
        RECT 2202.620000 3347.740000 2205.980000 3354.460000 ;
        RECT 2284.220000 3347.740000 2287.580000 3354.460000 ;
        RECT 2257.020000 3347.740000 2260.380000 3354.460000 ;
        RECT 2365.820000 3351.100000 2369.180000 3438.840000 ;
        RECT 2311.420000 3351.100000 2314.780000 3438.840000 ;
        RECT 2338.620000 3347.740000 2341.980000 3354.460000 ;
        RECT 2311.420000 3347.740000 2314.780000 3354.460000 ;
        RECT 2393.020000 3347.740000 2396.380000 3354.460000 ;
        RECT 2365.820000 3347.740000 2369.180000 3354.460000 ;
        RECT 2474.620000 3351.100000 2477.980000 3438.840000 ;
        RECT 2420.220000 3351.100000 2423.580000 3438.840000 ;
        RECT 2447.420000 3347.740000 2450.780000 3354.460000 ;
        RECT 2420.220000 3347.740000 2423.580000 3354.460000 ;
        RECT 2501.820000 3347.740000 2505.180000 3354.460000 ;
        RECT 2474.620000 3347.740000 2477.980000 3354.460000 ;
        RECT 2583.420000 3351.100000 2586.780000 3438.840000 ;
        RECT 2529.020000 3351.100000 2532.380000 3438.840000 ;
        RECT 2556.220000 3347.740000 2559.580000 3354.460000 ;
        RECT 2529.020000 3347.740000 2532.380000 3354.460000 ;
        RECT 2610.620000 3347.740000 2613.980000 3354.460000 ;
        RECT 2583.420000 3347.740000 2586.780000 3354.460000 ;
        RECT 2692.220000 3351.100000 2695.580000 3438.840000 ;
        RECT 2637.820000 3351.100000 2641.180000 3438.840000 ;
        RECT 2665.020000 3347.740000 2668.380000 3354.460000 ;
        RECT 2637.820000 3347.740000 2641.180000 3354.460000 ;
        RECT 2692.220000 3347.740000 2695.580000 3354.460000 ;
        RECT 2719.420000 3347.740000 2722.780000 3354.460000 ;
        RECT 2801.020000 3351.100000 2804.380000 3438.840000 ;
        RECT 2746.620000 3351.100000 2749.980000 3438.840000 ;
        RECT 2746.620000 3347.740000 2749.980000 3354.460000 ;
        RECT 2773.820000 3347.740000 2777.180000 3354.460000 ;
        RECT 2801.020000 3347.740000 2804.380000 3354.460000 ;
        RECT 2828.220000 3347.740000 2831.580000 3354.460000 ;
        RECT 2854.160000 3351.100000 2857.520000 3438.840000 ;
      LAYER met5 ;
        RECT 0.000000 6.720000 2887.880000 10.080000 ;
        RECT 30.400000 91.260000 2857.520000 94.620000 ;
        RECT 6.720000 65.620000 2881.160000 68.980000 ;
        RECT 30.400000 428.140000 37.120000 431.500000 ;
        RECT 6.720000 96.300000 33.760000 99.660000 ;
        RECT 30.400000 123.500000 37.120000 126.860000 ;
        RECT 6.720000 150.700000 33.760000 154.060000 ;
        RECT 30.400000 150.700000 37.120000 154.060000 ;
        RECT 30.400000 177.900000 37.120000 181.260000 ;
        RECT 6.720000 205.100000 33.760000 208.460000 ;
        RECT 30.400000 205.100000 37.120000 208.460000 ;
        RECT 30.400000 232.300000 37.120000 235.660000 ;
        RECT 6.720000 259.500000 33.760000 262.860000 ;
        RECT 30.400000 259.500000 37.120000 262.860000 ;
        RECT 6.720000 292.140000 33.760000 295.500000 ;
        RECT 30.400000 319.340000 37.120000 322.700000 ;
        RECT 30.400000 373.740000 37.120000 377.100000 ;
        RECT 6.720000 346.540000 33.760000 349.900000 ;
        RECT 30.400000 346.540000 37.120000 349.900000 ;
        RECT 30.400000 400.940000 37.120000 404.300000 ;
        RECT 6.720000 400.940000 33.760000 404.300000 ;
        RECT 30.400000 455.340000 37.120000 458.700000 ;
        RECT 6.720000 455.340000 33.760000 458.700000 ;
        RECT 6.720000 487.980000 33.760000 491.340000 ;
        RECT 30.400000 515.180000 37.120000 518.540000 ;
        RECT 6.720000 542.380000 33.760000 545.740000 ;
        RECT 30.400000 542.380000 37.120000 545.740000 ;
        RECT 30.400000 569.580000 37.120000 572.940000 ;
        RECT 6.720000 596.780000 33.760000 600.140000 ;
        RECT 30.400000 596.780000 37.120000 600.140000 ;
        RECT 30.400000 623.980000 37.120000 627.340000 ;
        RECT 6.720000 651.180000 33.760000 654.540000 ;
        RECT 30.400000 651.180000 37.120000 654.540000 ;
        RECT 6.720000 683.820000 33.760000 687.180000 ;
        RECT 30.400000 711.020000 37.120000 714.380000 ;
        RECT 6.720000 738.220000 33.760000 741.580000 ;
        RECT 30.400000 738.220000 37.120000 741.580000 ;
        RECT 30.400000 765.420000 37.120000 768.780000 ;
        RECT 6.720000 792.620000 33.760000 795.980000 ;
        RECT 30.400000 792.620000 37.120000 795.980000 ;
        RECT 30.400000 819.820000 37.120000 823.180000 ;
        RECT 6.720000 847.020000 33.760000 850.380000 ;
        RECT 30.400000 847.020000 37.120000 850.380000 ;
        RECT 30.400000 874.220000 37.120000 877.580000 ;
        RECT 6.720000 901.420000 33.760000 904.780000 ;
        RECT 30.400000 901.420000 37.120000 904.780000 ;
        RECT 30.400000 928.620000 37.120000 931.980000 ;
        RECT 6.720000 955.820000 33.760000 959.180000 ;
        RECT 30.400000 955.820000 37.120000 959.180000 ;
        RECT 30.400000 983.020000 37.120000 986.380000 ;
        RECT 6.720000 1010.220000 33.760000 1013.580000 ;
        RECT 30.400000 1010.220000 37.120000 1013.580000 ;
        RECT 30.400000 1037.420000 37.120000 1040.780000 ;
        RECT 6.720000 1064.620000 33.760000 1067.980000 ;
        RECT 30.400000 1064.620000 37.120000 1067.980000 ;
        RECT 30.400000 1091.820000 37.120000 1095.180000 ;
        RECT 6.720000 1119.020000 33.760000 1122.380000 ;
        RECT 30.400000 1119.020000 37.120000 1122.380000 ;
        RECT 30.400000 1146.220000 37.120000 1149.580000 ;
        RECT 6.720000 1173.420000 33.760000 1176.780000 ;
        RECT 30.400000 1173.420000 37.120000 1176.780000 ;
        RECT 30.400000 1200.620000 37.120000 1203.980000 ;
        RECT 6.720000 1227.820000 33.760000 1231.180000 ;
        RECT 30.400000 1227.820000 37.120000 1231.180000 ;
        RECT 30.400000 1255.020000 37.120000 1258.380000 ;
        RECT 6.720000 1282.220000 33.760000 1285.580000 ;
        RECT 30.400000 1282.220000 37.120000 1285.580000 ;
        RECT 30.400000 1309.420000 37.120000 1312.780000 ;
        RECT 6.720000 1336.620000 33.760000 1339.980000 ;
        RECT 30.400000 1336.620000 37.120000 1339.980000 ;
        RECT 30.400000 1363.820000 37.120000 1367.180000 ;
        RECT 6.720000 1391.020000 33.760000 1394.380000 ;
        RECT 30.400000 1391.020000 37.120000 1394.380000 ;
        RECT 30.400000 1418.220000 37.120000 1421.580000 ;
        RECT 6.720000 1445.420000 33.760000 1448.780000 ;
        RECT 30.400000 1445.420000 37.120000 1448.780000 ;
        RECT 30.400000 1472.620000 37.120000 1475.980000 ;
        RECT 6.720000 1499.820000 33.760000 1503.180000 ;
        RECT 30.400000 1499.820000 37.120000 1503.180000 ;
        RECT 30.400000 1527.020000 37.120000 1530.380000 ;
        RECT 6.720000 1554.220000 33.760000 1557.580000 ;
        RECT 30.400000 1554.220000 37.120000 1557.580000 ;
        RECT 30.400000 1581.420000 37.120000 1584.780000 ;
        RECT 6.720000 1608.620000 33.760000 1611.980000 ;
        RECT 30.400000 1608.620000 37.120000 1611.980000 ;
        RECT 30.400000 1635.820000 37.120000 1639.180000 ;
        RECT 6.720000 1663.020000 33.760000 1666.380000 ;
        RECT 30.400000 1663.020000 37.120000 1666.380000 ;
        RECT 30.400000 1690.220000 37.120000 1693.580000 ;
        RECT 6.720000 1717.420000 33.760000 1720.780000 ;
        RECT 2850.800000 428.140000 2857.520000 431.500000 ;
        RECT 2854.160000 96.300000 2881.160000 99.660000 ;
        RECT 2850.800000 123.500000 2857.520000 126.860000 ;
        RECT 2854.160000 150.700000 2881.160000 154.060000 ;
        RECT 2850.800000 150.700000 2857.520000 154.060000 ;
        RECT 2850.800000 177.900000 2857.520000 181.260000 ;
        RECT 2854.160000 205.100000 2881.160000 208.460000 ;
        RECT 2850.800000 205.100000 2857.520000 208.460000 ;
        RECT 2850.800000 232.300000 2857.520000 235.660000 ;
        RECT 2854.160000 259.500000 2881.160000 262.860000 ;
        RECT 2850.800000 259.500000 2857.520000 262.860000 ;
        RECT 2854.160000 292.140000 2881.160000 295.500000 ;
        RECT 2850.800000 319.340000 2857.520000 322.700000 ;
        RECT 2850.800000 373.740000 2857.520000 377.100000 ;
        RECT 2854.160000 346.540000 2881.160000 349.900000 ;
        RECT 2850.800000 346.540000 2857.520000 349.900000 ;
        RECT 2850.800000 400.940000 2857.520000 404.300000 ;
        RECT 2854.160000 400.940000 2881.160000 404.300000 ;
        RECT 2850.800000 455.340000 2857.520000 458.700000 ;
        RECT 2854.160000 455.340000 2881.160000 458.700000 ;
        RECT 2854.160000 487.980000 2881.160000 491.340000 ;
        RECT 2850.800000 515.180000 2857.520000 518.540000 ;
        RECT 2854.160000 542.380000 2881.160000 545.740000 ;
        RECT 2850.800000 542.380000 2857.520000 545.740000 ;
        RECT 2850.800000 569.580000 2857.520000 572.940000 ;
        RECT 2854.160000 596.780000 2881.160000 600.140000 ;
        RECT 2850.800000 596.780000 2857.520000 600.140000 ;
        RECT 2850.800000 623.980000 2857.520000 627.340000 ;
        RECT 2854.160000 651.180000 2881.160000 654.540000 ;
        RECT 2850.800000 651.180000 2857.520000 654.540000 ;
        RECT 2854.160000 683.820000 2881.160000 687.180000 ;
        RECT 2850.800000 711.020000 2857.520000 714.380000 ;
        RECT 2854.160000 738.220000 2881.160000 741.580000 ;
        RECT 2850.800000 738.220000 2857.520000 741.580000 ;
        RECT 2850.800000 765.420000 2857.520000 768.780000 ;
        RECT 2854.160000 792.620000 2881.160000 795.980000 ;
        RECT 2850.800000 792.620000 2857.520000 795.980000 ;
        RECT 2850.800000 819.820000 2857.520000 823.180000 ;
        RECT 2854.160000 847.020000 2881.160000 850.380000 ;
        RECT 2850.800000 847.020000 2857.520000 850.380000 ;
        RECT 2850.800000 874.220000 2857.520000 877.580000 ;
        RECT 2854.160000 901.420000 2881.160000 904.780000 ;
        RECT 2850.800000 901.420000 2857.520000 904.780000 ;
        RECT 2850.800000 928.620000 2857.520000 931.980000 ;
        RECT 2854.160000 955.820000 2881.160000 959.180000 ;
        RECT 2850.800000 955.820000 2857.520000 959.180000 ;
        RECT 2850.800000 983.020000 2857.520000 986.380000 ;
        RECT 2854.160000 1010.220000 2881.160000 1013.580000 ;
        RECT 2850.800000 1010.220000 2857.520000 1013.580000 ;
        RECT 2850.800000 1037.420000 2857.520000 1040.780000 ;
        RECT 2854.160000 1064.620000 2881.160000 1067.980000 ;
        RECT 2850.800000 1064.620000 2857.520000 1067.980000 ;
        RECT 2850.800000 1091.820000 2857.520000 1095.180000 ;
        RECT 2854.160000 1119.020000 2881.160000 1122.380000 ;
        RECT 2850.800000 1119.020000 2857.520000 1122.380000 ;
        RECT 2850.800000 1146.220000 2857.520000 1149.580000 ;
        RECT 2854.160000 1173.420000 2881.160000 1176.780000 ;
        RECT 2850.800000 1173.420000 2857.520000 1176.780000 ;
        RECT 2850.800000 1200.620000 2857.520000 1203.980000 ;
        RECT 2854.160000 1227.820000 2881.160000 1231.180000 ;
        RECT 2850.800000 1227.820000 2857.520000 1231.180000 ;
        RECT 2850.800000 1255.020000 2857.520000 1258.380000 ;
        RECT 2854.160000 1282.220000 2881.160000 1285.580000 ;
        RECT 2850.800000 1282.220000 2857.520000 1285.580000 ;
        RECT 2850.800000 1309.420000 2857.520000 1312.780000 ;
        RECT 2854.160000 1336.620000 2881.160000 1339.980000 ;
        RECT 2850.800000 1336.620000 2857.520000 1339.980000 ;
        RECT 2850.800000 1363.820000 2857.520000 1367.180000 ;
        RECT 2854.160000 1391.020000 2881.160000 1394.380000 ;
        RECT 2850.800000 1391.020000 2857.520000 1394.380000 ;
        RECT 2850.800000 1418.220000 2857.520000 1421.580000 ;
        RECT 2854.160000 1445.420000 2881.160000 1448.780000 ;
        RECT 2850.800000 1445.420000 2857.520000 1448.780000 ;
        RECT 2850.800000 1472.620000 2857.520000 1475.980000 ;
        RECT 2854.160000 1499.820000 2881.160000 1503.180000 ;
        RECT 2850.800000 1499.820000 2857.520000 1503.180000 ;
        RECT 2850.800000 1527.020000 2857.520000 1530.380000 ;
        RECT 2854.160000 1554.220000 2881.160000 1557.580000 ;
        RECT 2850.800000 1554.220000 2857.520000 1557.580000 ;
        RECT 2850.800000 1581.420000 2857.520000 1584.780000 ;
        RECT 2854.160000 1608.620000 2881.160000 1611.980000 ;
        RECT 2850.800000 1608.620000 2857.520000 1611.980000 ;
        RECT 2850.800000 1635.820000 2857.520000 1639.180000 ;
        RECT 2854.160000 1663.020000 2881.160000 1666.380000 ;
        RECT 2850.800000 1663.020000 2857.520000 1666.380000 ;
        RECT 2850.800000 1690.220000 2857.520000 1693.580000 ;
        RECT 2854.160000 1717.420000 2881.160000 1720.780000 ;
        RECT 30.400000 3351.100000 2857.520000 3354.460000 ;
        RECT 0.000000 3435.480000 2887.880000 3438.840000 ;
        RECT 6.720000 3405.500000 2881.160000 3408.860000 ;
        RECT 30.400000 2582.380000 37.120000 2585.740000 ;
        RECT 6.720000 2582.380000 33.760000 2585.740000 ;
        RECT 6.720000 1722.860000 33.760000 1726.220000 ;
        RECT 30.400000 1750.060000 37.120000 1753.420000 ;
        RECT 6.720000 1777.260000 33.760000 1780.620000 ;
        RECT 30.400000 1777.260000 37.120000 1780.620000 ;
        RECT 30.400000 1804.460000 37.120000 1807.820000 ;
        RECT 6.720000 1831.660000 33.760000 1835.020000 ;
        RECT 30.400000 1831.660000 37.120000 1835.020000 ;
        RECT 30.400000 1858.860000 37.120000 1862.220000 ;
        RECT 6.720000 1886.060000 33.760000 1889.420000 ;
        RECT 30.400000 1886.060000 37.120000 1889.420000 ;
        RECT 6.720000 1918.700000 33.760000 1922.060000 ;
        RECT 30.400000 1945.900000 37.120000 1949.260000 ;
        RECT 6.720000 1973.100000 33.760000 1976.460000 ;
        RECT 30.400000 1973.100000 37.120000 1976.460000 ;
        RECT 30.400000 2000.300000 37.120000 2003.660000 ;
        RECT 6.720000 2027.500000 33.760000 2030.860000 ;
        RECT 30.400000 2027.500000 37.120000 2030.860000 ;
        RECT 30.400000 2054.700000 37.120000 2058.060000 ;
        RECT 6.720000 2081.900000 33.760000 2085.260000 ;
        RECT 30.400000 2081.900000 37.120000 2085.260000 ;
        RECT 6.720000 2114.540000 33.760000 2117.900000 ;
        RECT 30.400000 2141.740000 37.120000 2145.100000 ;
        RECT 6.720000 2168.940000 33.760000 2172.300000 ;
        RECT 30.400000 2168.940000 37.120000 2172.300000 ;
        RECT 30.400000 2196.140000 37.120000 2199.500000 ;
        RECT 6.720000 2223.340000 33.760000 2226.700000 ;
        RECT 30.400000 2223.340000 37.120000 2226.700000 ;
        RECT 30.400000 2250.540000 37.120000 2253.900000 ;
        RECT 6.720000 2277.740000 33.760000 2281.100000 ;
        RECT 30.400000 2277.740000 37.120000 2281.100000 ;
        RECT 6.720000 2310.380000 33.760000 2313.740000 ;
        RECT 30.400000 2337.580000 37.120000 2340.940000 ;
        RECT 6.720000 2364.780000 33.760000 2368.140000 ;
        RECT 30.400000 2364.780000 37.120000 2368.140000 ;
        RECT 30.400000 2473.580000 37.120000 2476.940000 ;
        RECT 6.720000 2473.580000 33.760000 2476.940000 ;
        RECT 30.400000 2391.980000 37.120000 2395.340000 ;
        RECT 6.720000 2419.180000 33.760000 2422.540000 ;
        RECT 30.400000 2419.180000 37.120000 2422.540000 ;
        RECT 30.400000 2446.380000 37.120000 2449.740000 ;
        RECT 30.400000 2527.980000 37.120000 2531.340000 ;
        RECT 6.720000 2527.980000 33.760000 2531.340000 ;
        RECT 30.400000 2500.780000 37.120000 2504.140000 ;
        RECT 30.400000 2555.180000 37.120000 2558.540000 ;
        RECT 30.400000 2691.180000 37.120000 2694.540000 ;
        RECT 6.720000 2691.180000 33.760000 2694.540000 ;
        RECT 30.400000 2636.780000 37.120000 2640.140000 ;
        RECT 6.720000 2636.780000 33.760000 2640.140000 ;
        RECT 30.400000 2609.580000 37.120000 2612.940000 ;
        RECT 30.400000 2663.980000 37.120000 2667.340000 ;
        RECT 30.400000 2745.580000 37.120000 2748.940000 ;
        RECT 6.720000 2745.580000 33.760000 2748.940000 ;
        RECT 30.400000 2718.380000 37.120000 2721.740000 ;
        RECT 30.400000 2772.780000 37.120000 2776.140000 ;
        RECT 6.720000 2799.980000 33.760000 2803.340000 ;
        RECT 30.400000 2799.980000 37.120000 2803.340000 ;
        RECT 30.400000 2827.180000 37.120000 2830.540000 ;
        RECT 6.720000 2854.380000 33.760000 2857.740000 ;
        RECT 30.400000 2854.380000 37.120000 2857.740000 ;
        RECT 30.400000 2881.580000 37.120000 2884.940000 ;
        RECT 6.720000 2908.780000 33.760000 2912.140000 ;
        RECT 30.400000 2908.780000 37.120000 2912.140000 ;
        RECT 30.400000 2935.980000 37.120000 2939.340000 ;
        RECT 6.720000 2963.180000 33.760000 2966.540000 ;
        RECT 30.400000 2963.180000 37.120000 2966.540000 ;
        RECT 30.400000 2990.380000 37.120000 2993.740000 ;
        RECT 6.720000 3017.580000 33.760000 3020.940000 ;
        RECT 30.400000 3017.580000 37.120000 3020.940000 ;
        RECT 30.400000 3044.780000 37.120000 3048.140000 ;
        RECT 6.720000 3071.980000 33.760000 3075.340000 ;
        RECT 30.400000 3071.980000 37.120000 3075.340000 ;
        RECT 30.400000 3099.180000 37.120000 3102.540000 ;
        RECT 6.720000 3126.380000 33.760000 3129.740000 ;
        RECT 30.400000 3126.380000 37.120000 3129.740000 ;
        RECT 30.400000 3153.580000 37.120000 3156.940000 ;
        RECT 6.720000 3180.780000 33.760000 3184.140000 ;
        RECT 30.400000 3180.780000 37.120000 3184.140000 ;
        RECT 30.400000 3207.980000 37.120000 3211.340000 ;
        RECT 6.720000 3235.180000 33.760000 3238.540000 ;
        RECT 30.400000 3235.180000 37.120000 3238.540000 ;
        RECT 30.400000 3262.380000 37.120000 3265.740000 ;
        RECT 6.720000 3289.580000 33.760000 3292.940000 ;
        RECT 30.400000 3289.580000 37.120000 3292.940000 ;
        RECT 30.400000 3316.780000 37.120000 3320.140000 ;
        RECT 6.720000 3343.980000 33.760000 3347.340000 ;
        RECT 6.720000 3351.100000 33.760000 3354.460000 ;
        RECT 2850.800000 2582.380000 2857.520000 2585.740000 ;
        RECT 2854.160000 2582.380000 2881.160000 2585.740000 ;
        RECT 2854.160000 1722.860000 2881.160000 1726.220000 ;
        RECT 2850.800000 1750.060000 2857.520000 1753.420000 ;
        RECT 2854.160000 1777.260000 2881.160000 1780.620000 ;
        RECT 2850.800000 1777.260000 2857.520000 1780.620000 ;
        RECT 2850.800000 1804.460000 2857.520000 1807.820000 ;
        RECT 2854.160000 1831.660000 2881.160000 1835.020000 ;
        RECT 2850.800000 1831.660000 2857.520000 1835.020000 ;
        RECT 2850.800000 1858.860000 2857.520000 1862.220000 ;
        RECT 2854.160000 1886.060000 2881.160000 1889.420000 ;
        RECT 2850.800000 1886.060000 2857.520000 1889.420000 ;
        RECT 2854.160000 1918.700000 2881.160000 1922.060000 ;
        RECT 2850.800000 1945.900000 2857.520000 1949.260000 ;
        RECT 2854.160000 1973.100000 2881.160000 1976.460000 ;
        RECT 2850.800000 1973.100000 2857.520000 1976.460000 ;
        RECT 2850.800000 2000.300000 2857.520000 2003.660000 ;
        RECT 2854.160000 2027.500000 2881.160000 2030.860000 ;
        RECT 2850.800000 2027.500000 2857.520000 2030.860000 ;
        RECT 2850.800000 2054.700000 2857.520000 2058.060000 ;
        RECT 2854.160000 2081.900000 2881.160000 2085.260000 ;
        RECT 2850.800000 2081.900000 2857.520000 2085.260000 ;
        RECT 2854.160000 2114.540000 2881.160000 2117.900000 ;
        RECT 2850.800000 2141.740000 2857.520000 2145.100000 ;
        RECT 2854.160000 2168.940000 2881.160000 2172.300000 ;
        RECT 2850.800000 2168.940000 2857.520000 2172.300000 ;
        RECT 2850.800000 2196.140000 2857.520000 2199.500000 ;
        RECT 2854.160000 2223.340000 2881.160000 2226.700000 ;
        RECT 2850.800000 2223.340000 2857.520000 2226.700000 ;
        RECT 2850.800000 2250.540000 2857.520000 2253.900000 ;
        RECT 2854.160000 2277.740000 2881.160000 2281.100000 ;
        RECT 2850.800000 2277.740000 2857.520000 2281.100000 ;
        RECT 2854.160000 2310.380000 2881.160000 2313.740000 ;
        RECT 2850.800000 2337.580000 2857.520000 2340.940000 ;
        RECT 2854.160000 2364.780000 2881.160000 2368.140000 ;
        RECT 2850.800000 2364.780000 2857.520000 2368.140000 ;
        RECT 2850.800000 2473.580000 2857.520000 2476.940000 ;
        RECT 2854.160000 2473.580000 2881.160000 2476.940000 ;
        RECT 2850.800000 2391.980000 2857.520000 2395.340000 ;
        RECT 2854.160000 2419.180000 2881.160000 2422.540000 ;
        RECT 2850.800000 2419.180000 2857.520000 2422.540000 ;
        RECT 2850.800000 2446.380000 2857.520000 2449.740000 ;
        RECT 2850.800000 2527.980000 2857.520000 2531.340000 ;
        RECT 2854.160000 2527.980000 2881.160000 2531.340000 ;
        RECT 2850.800000 2500.780000 2857.520000 2504.140000 ;
        RECT 2850.800000 2555.180000 2857.520000 2558.540000 ;
        RECT 2850.800000 2691.180000 2857.520000 2694.540000 ;
        RECT 2854.160000 2691.180000 2881.160000 2694.540000 ;
        RECT 2850.800000 2636.780000 2857.520000 2640.140000 ;
        RECT 2854.160000 2636.780000 2881.160000 2640.140000 ;
        RECT 2850.800000 2609.580000 2857.520000 2612.940000 ;
        RECT 2850.800000 2663.980000 2857.520000 2667.340000 ;
        RECT 2850.800000 2745.580000 2857.520000 2748.940000 ;
        RECT 2854.160000 2745.580000 2881.160000 2748.940000 ;
        RECT 2850.800000 2718.380000 2857.520000 2721.740000 ;
        RECT 2850.800000 2772.780000 2857.520000 2776.140000 ;
        RECT 2854.160000 2799.980000 2881.160000 2803.340000 ;
        RECT 2850.800000 2799.980000 2857.520000 2803.340000 ;
        RECT 2850.800000 2827.180000 2857.520000 2830.540000 ;
        RECT 2854.160000 2854.380000 2881.160000 2857.740000 ;
        RECT 2850.800000 2854.380000 2857.520000 2857.740000 ;
        RECT 2850.800000 2881.580000 2857.520000 2884.940000 ;
        RECT 2854.160000 2908.780000 2881.160000 2912.140000 ;
        RECT 2850.800000 2908.780000 2857.520000 2912.140000 ;
        RECT 2850.800000 2935.980000 2857.520000 2939.340000 ;
        RECT 2854.160000 2963.180000 2881.160000 2966.540000 ;
        RECT 2850.800000 2963.180000 2857.520000 2966.540000 ;
        RECT 2850.800000 2990.380000 2857.520000 2993.740000 ;
        RECT 2854.160000 3017.580000 2881.160000 3020.940000 ;
        RECT 2850.800000 3017.580000 2857.520000 3020.940000 ;
        RECT 2850.800000 3044.780000 2857.520000 3048.140000 ;
        RECT 2854.160000 3071.980000 2881.160000 3075.340000 ;
        RECT 2850.800000 3071.980000 2857.520000 3075.340000 ;
        RECT 2850.800000 3099.180000 2857.520000 3102.540000 ;
        RECT 2854.160000 3126.380000 2881.160000 3129.740000 ;
        RECT 2850.800000 3126.380000 2857.520000 3129.740000 ;
        RECT 2850.800000 3153.580000 2857.520000 3156.940000 ;
        RECT 2854.160000 3180.780000 2881.160000 3184.140000 ;
        RECT 2850.800000 3180.780000 2857.520000 3184.140000 ;
        RECT 2850.800000 3207.980000 2857.520000 3211.340000 ;
        RECT 2854.160000 3235.180000 2881.160000 3238.540000 ;
        RECT 2850.800000 3235.180000 2857.520000 3238.540000 ;
        RECT 2850.800000 3262.380000 2857.520000 3265.740000 ;
        RECT 2854.160000 3289.580000 2881.160000 3292.940000 ;
        RECT 2850.800000 3289.580000 2857.520000 3292.940000 ;
        RECT 2850.800000 3316.780000 2857.520000 3320.140000 ;
        RECT 2854.160000 3351.100000 2881.160000 3354.460000 ;
        RECT 2854.160000 3343.980000 2881.160000 3347.340000 ;
    END
# end of P/G power stripe data as pin

  END VDD
  OBS
    LAYER li1 ;
      RECT 0.000000 0.000000 2887.880000 3445.560000 ;
    LAYER met1 ;
      RECT 0.000000 0.000000 2887.880000 3445.560000 ;
    LAYER met2 ;
      RECT 0.000000 0.000000 2887.880000 3445.560000 ;
    LAYER met3 ;
      RECT 0.000000 0.000000 2887.880000 3445.560000 ;
    LAYER met4 ;
      RECT 0.000000 0.000000 2887.880000 3445.560000 ;
    LAYER met5 ;
      RECT 0.000000 0.000000 2887.880000 3445.560000 ;
  END
END user_proj_example

END LIBRARY
